VERSION 5.8 ;
BUSBITCHARS "[]" ;
DIVIDERCHAR "/" ;
UNITS
    DATABASE MICRONS 1000 ;
END UNITS

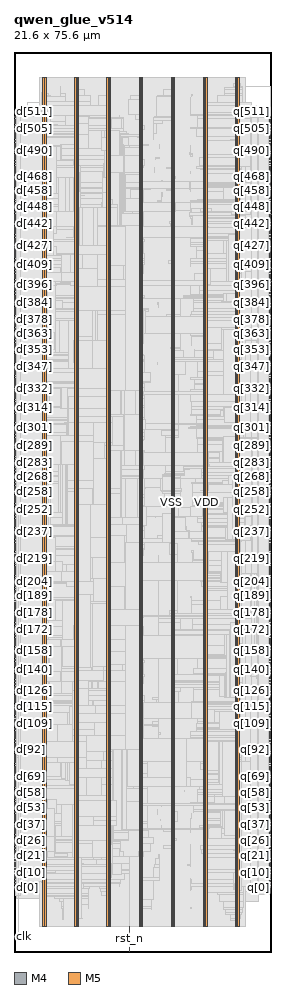
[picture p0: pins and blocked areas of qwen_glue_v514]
MACRO qwen_glue_v514
  FOREIGN qwen_glue_v514 0 0 ;
  CLASS BLOCK ;
  SIZE 21.6 BY 75.6 ;
  PIN clk
    DIRECTION INPUT ;
    USE SIGNAL ;
    PORT
      LAYER M4 ;
        RECT  0.054 1.296 0.138 1.32 ;
    END
    PORT
      LAYER M4 ;
        RECT  0.108 1.296 0.371 1.32 ;
    END
  END clk
  PIN d[0]
    DIRECTION INPUT ;
    USE SIGNAL ;
    PORT
      LAYER M4 ;
        RECT  0.054 5.424 0.138 5.448 ;
    END
  END d[0]
  PIN d[100]
    DIRECTION INPUT ;
    USE SIGNAL ;
    PORT
      LAYER M4 ;
        RECT  0.054 18 0.138 18.024 ;
    END
  END d[100]
  PIN d[101]
    DIRECTION INPUT ;
    USE SIGNAL ;
    PORT
      LAYER M4 ;
        RECT  0.054 18.144 0.138 18.168 ;
    END
  END d[101]
  PIN d[102]
    DIRECTION INPUT ;
    USE SIGNAL ;
    PORT
      LAYER M4 ;
        RECT  0.054 18.288 0.138 18.312 ;
    END
  END d[102]
  PIN d[103]
    DIRECTION INPUT ;
    USE SIGNAL ;
    PORT
      LAYER M4 ;
        RECT  0.054 18.384 0.138 18.408 ;
    END
  END d[103]
  PIN d[104]
    DIRECTION INPUT ;
    USE SIGNAL ;
    PORT
      LAYER M4 ;
        RECT  0.054 18.528 0.138 18.552 ;
    END
  END d[104]
  PIN d[105]
    DIRECTION INPUT ;
    USE SIGNAL ;
    PORT
      LAYER M4 ;
        RECT  0.054 18.672 0.138 18.696 ;
    END
  END d[105]
  PIN d[106]
    DIRECTION INPUT ;
    USE SIGNAL ;
    PORT
      LAYER M4 ;
        RECT  0.054 18.768 0.138 18.792 ;
    END
  END d[106]
  PIN d[107]
    DIRECTION INPUT ;
    USE SIGNAL ;
    PORT
      LAYER M4 ;
        RECT  0.054 18.912 0.138 18.936 ;
    END
  END d[107]
  PIN d[108]
    DIRECTION INPUT ;
    USE SIGNAL ;
    PORT
      LAYER M4 ;
        RECT  0.054 19.008 0.138 19.032 ;
    END
  END d[108]
  PIN d[109]
    DIRECTION INPUT ;
    USE SIGNAL ;
    PORT
      LAYER M4 ;
        RECT  0.054 19.152 0.138 19.176 ;
    END
  END d[109]
  PIN d[10]
    DIRECTION INPUT ;
    USE SIGNAL ;
    PORT
      LAYER M4 ;
        RECT  0.054 6.672 0.138 6.696 ;
    END
  END d[10]
  PIN d[110]
    DIRECTION INPUT ;
    USE SIGNAL ;
    PORT
      LAYER M4 ;
        RECT  0.054 19.296 0.138 19.32 ;
    END
  END d[110]
  PIN d[111]
    DIRECTION INPUT ;
    USE SIGNAL ;
    PORT
      LAYER M4 ;
        RECT  0.054 19.392 0.138 19.416 ;
    END
  END d[111]
  PIN d[112]
    DIRECTION INPUT ;
    USE SIGNAL ;
    PORT
      LAYER M4 ;
        RECT  0.054 19.536 0.138 19.56 ;
    END
    PORT
      LAYER M4 ;
        RECT  0.025 19.536 0.108 19.56 ;
    END
  END d[112]
  PIN d[113]
    DIRECTION INPUT ;
    USE SIGNAL ;
    PORT
      LAYER M4 ;
        RECT  0.054 19.68 0.138 19.704 ;
    END
  END d[113]
  PIN d[114]
    DIRECTION INPUT ;
    USE SIGNAL ;
    PORT
      LAYER M4 ;
        RECT  0.054 19.776 0.138 19.8 ;
    END
  END d[114]
  PIN d[115]
    DIRECTION INPUT ;
    USE SIGNAL ;
    PORT
      LAYER M4 ;
        RECT  0.054 19.92 0.138 19.944 ;
    END
  END d[115]
  PIN d[116]
    DIRECTION INPUT ;
    USE SIGNAL ;
    PORT
      LAYER M4 ;
        RECT  0.054 20.064 0.138 20.088 ;
    END
  END d[116]
  PIN d[117]
    DIRECTION INPUT ;
    USE SIGNAL ;
    PORT
      LAYER M4 ;
        RECT  0.054 20.16 0.138 20.184 ;
    END
  END d[117]
  PIN d[118]
    DIRECTION INPUT ;
    USE SIGNAL ;
    PORT
      LAYER M4 ;
        RECT  0.054 20.304 0.138 20.328 ;
    END
  END d[118]
  PIN d[119]
    DIRECTION INPUT ;
    USE SIGNAL ;
    PORT
      LAYER M4 ;
        RECT  0.054 20.4 0.138 20.424 ;
    END
  END d[119]
  PIN d[11]
    DIRECTION INPUT ;
    USE SIGNAL ;
    PORT
      LAYER M4 ;
        RECT  0.054 6.768 0.138 6.792 ;
    END
  END d[11]
  PIN d[120]
    DIRECTION INPUT ;
    USE SIGNAL ;
    PORT
      LAYER M4 ;
        RECT  0.054 20.544 0.138 20.568 ;
    END
  END d[120]
  PIN d[121]
    DIRECTION INPUT ;
    USE SIGNAL ;
    PORT
      LAYER M4 ;
        RECT  0.054 20.688 0.138 20.712 ;
    END
  END d[121]
  PIN d[122]
    DIRECTION INPUT ;
    USE SIGNAL ;
    PORT
      LAYER M4 ;
        RECT  0.054 20.784 0.138 20.808 ;
    END
  END d[122]
  PIN d[123]
    DIRECTION INPUT ;
    USE SIGNAL ;
    PORT
      LAYER M4 ;
        RECT  0.054 20.928 0.138 20.952 ;
    END
  END d[123]
  PIN d[124]
    DIRECTION INPUT ;
    USE SIGNAL ;
    PORT
      LAYER M4 ;
        RECT  0.054 21.072 0.138 21.096 ;
    END
  END d[124]
  PIN d[125]
    DIRECTION INPUT ;
    USE SIGNAL ;
    PORT
      LAYER M4 ;
        RECT  0.054 21.168 0.138 21.192 ;
    END
  END d[125]
  PIN d[126]
    DIRECTION INPUT ;
    USE SIGNAL ;
    PORT
      LAYER M4 ;
        RECT  0.054 21.312 0.138 21.336 ;
    END
  END d[126]
  PIN d[127]
    DIRECTION INPUT ;
    USE SIGNAL ;
    PORT
      LAYER M4 ;
        RECT  0.054 21.408 0.138 21.432 ;
    END
  END d[127]
  PIN d[128]
    DIRECTION INPUT ;
    USE SIGNAL ;
    PORT
      LAYER M4 ;
        RECT  0.054 21.552 0.138 21.576 ;
    END
  END d[128]
  PIN d[129]
    DIRECTION INPUT ;
    USE SIGNAL ;
    PORT
      LAYER M4 ;
        RECT  0.054 21.696 0.138 21.72 ;
    END
  END d[129]
  PIN d[12]
    DIRECTION INPUT ;
    USE SIGNAL ;
    PORT
      LAYER M4 ;
        RECT  0.054 6.912 0.138 6.936 ;
    END
  END d[12]
  PIN d[130]
    DIRECTION INPUT ;
    USE SIGNAL ;
    PORT
      LAYER M4 ;
        RECT  0.054 21.792 0.138 21.816 ;
    END
  END d[130]
  PIN d[131]
    DIRECTION INPUT ;
    USE SIGNAL ;
    PORT
      LAYER M4 ;
        RECT  0.054 21.936 0.138 21.96 ;
    END
  END d[131]
  PIN d[132]
    DIRECTION INPUT ;
    USE SIGNAL ;
    PORT
      LAYER M4 ;
        RECT  0.054 22.08 0.138 22.104 ;
    END
  END d[132]
  PIN d[133]
    DIRECTION INPUT ;
    USE SIGNAL ;
    PORT
      LAYER M4 ;
        RECT  0.054 22.176 0.138 22.2 ;
    END
  END d[133]
  PIN d[134]
    DIRECTION INPUT ;
    USE SIGNAL ;
    PORT
      LAYER M4 ;
        RECT  0.054 22.32 0.138 22.344 ;
    END
  END d[134]
  PIN d[135]
    DIRECTION INPUT ;
    USE SIGNAL ;
    PORT
      LAYER M4 ;
        RECT  0.054 22.464 0.138 22.488 ;
    END
  END d[135]
  PIN d[136]
    DIRECTION INPUT ;
    USE SIGNAL ;
    PORT
      LAYER M4 ;
        RECT  0.054 22.56 0.138 22.584 ;
    END
  END d[136]
  PIN d[137]
    DIRECTION INPUT ;
    USE SIGNAL ;
    PORT
      LAYER M4 ;
        RECT  0.054 22.704 0.138 22.728 ;
    END
  END d[137]
  PIN d[138]
    DIRECTION INPUT ;
    USE SIGNAL ;
    PORT
      LAYER M4 ;
        RECT  0.054 22.8 0.138 22.824 ;
    END
  END d[138]
  PIN d[139]
    DIRECTION INPUT ;
    USE SIGNAL ;
    PORT
      LAYER M4 ;
        RECT  0.054 22.944 0.138 22.968 ;
    END
  END d[139]
  PIN d[13]
    DIRECTION INPUT ;
    USE SIGNAL ;
    PORT
      LAYER M4 ;
        RECT  0.054 7.008 0.138 7.032 ;
    END
  END d[13]
  PIN d[140]
    DIRECTION INPUT ;
    USE SIGNAL ;
    PORT
      LAYER M4 ;
        RECT  0.054 23.088 0.138 23.112 ;
    END
  END d[140]
  PIN d[141]
    DIRECTION INPUT ;
    USE SIGNAL ;
    PORT
      LAYER M4 ;
        RECT  0.054 23.184 0.138 23.208 ;
    END
  END d[141]
  PIN d[142]
    DIRECTION INPUT ;
    USE SIGNAL ;
    PORT
      LAYER M4 ;
        RECT  0.054 23.328 0.138 23.352 ;
    END
  END d[142]
  PIN d[143]
    DIRECTION INPUT ;
    USE SIGNAL ;
    PORT
      LAYER M4 ;
        RECT  0.054 23.472 0.138 23.496 ;
    END
  END d[143]
  PIN d[144]
    DIRECTION INPUT ;
    USE SIGNAL ;
    PORT
      LAYER M4 ;
        RECT  0.054 23.568 0.138 23.592 ;
    END
  END d[144]
  PIN d[145]
    DIRECTION INPUT ;
    USE SIGNAL ;
    PORT
      LAYER M4 ;
        RECT  0.054 23.712 0.138 23.736 ;
    END
  END d[145]
  PIN d[146]
    DIRECTION INPUT ;
    USE SIGNAL ;
    PORT
      LAYER M4 ;
        RECT  0.054 23.808 0.138 23.832 ;
    END
  END d[146]
  PIN d[147]
    DIRECTION INPUT ;
    USE SIGNAL ;
    PORT
      LAYER M4 ;
        RECT  0.054 23.952 0.138 23.976 ;
    END
  END d[147]
  PIN d[148]
    DIRECTION INPUT ;
    USE SIGNAL ;
    PORT
      LAYER M4 ;
        RECT  0.054 24.096 0.138 24.12 ;
    END
  END d[148]
  PIN d[149]
    DIRECTION INPUT ;
    USE SIGNAL ;
    PORT
      LAYER M4 ;
        RECT  0.054 24.192 0.138 24.216 ;
    END
  END d[149]
  PIN d[14]
    DIRECTION INPUT ;
    USE SIGNAL ;
    PORT
      LAYER M4 ;
        RECT  0.054 7.152 0.138 7.176 ;
    END
  END d[14]
  PIN d[150]
    DIRECTION INPUT ;
    USE SIGNAL ;
    PORT
      LAYER M4 ;
        RECT  0.054 24.336 0.138 24.36 ;
    END
  END d[150]
  PIN d[151]
    DIRECTION INPUT ;
    USE SIGNAL ;
    PORT
      LAYER M4 ;
        RECT  0.054 24.48 0.138 24.504 ;
    END
  END d[151]
  PIN d[152]
    DIRECTION INPUT ;
    USE SIGNAL ;
    PORT
      LAYER M4 ;
        RECT  0.054 24.576 0.138 24.6 ;
    END
  END d[152]
  PIN d[153]
    DIRECTION INPUT ;
    USE SIGNAL ;
    PORT
      LAYER M4 ;
        RECT  0.054 24.72 0.138 24.744 ;
    END
  END d[153]
  PIN d[154]
    DIRECTION INPUT ;
    USE SIGNAL ;
    PORT
      LAYER M4 ;
        RECT  0.054 24.864 0.138 24.888 ;
    END
  END d[154]
  PIN d[155]
    DIRECTION INPUT ;
    USE SIGNAL ;
    PORT
      LAYER M4 ;
        RECT  0.054 24.96 0.138 24.984 ;
    END
    PORT
      LAYER M4 ;
        RECT  0.025 24.96 0.108 24.984 ;
    END
  END d[155]
  PIN d[156]
    DIRECTION INPUT ;
    USE SIGNAL ;
    PORT
      LAYER M4 ;
        RECT  0.054 25.104 0.138 25.128 ;
    END
  END d[156]
  PIN d[157]
    DIRECTION INPUT ;
    USE SIGNAL ;
    PORT
      LAYER M4 ;
        RECT  0.054 25.2 0.138 25.224 ;
    END
  END d[157]
  PIN d[158]
    DIRECTION INPUT ;
    USE SIGNAL ;
    PORT
      LAYER M4 ;
        RECT  0.054 25.344 0.138 25.368 ;
    END
  END d[158]
  PIN d[159]
    DIRECTION INPUT ;
    USE SIGNAL ;
    PORT
      LAYER M4 ;
        RECT  0.054 25.488 0.138 25.512 ;
    END
  END d[159]
  PIN d[15]
    DIRECTION INPUT ;
    USE SIGNAL ;
    PORT
      LAYER M4 ;
        RECT  0.054 7.296 0.138 7.32 ;
    END
  END d[15]
  PIN d[160]
    DIRECTION INPUT ;
    USE SIGNAL ;
    PORT
      LAYER M4 ;
        RECT  0.054 25.584 0.138 25.608 ;
    END
  END d[160]
  PIN d[161]
    DIRECTION INPUT ;
    USE SIGNAL ;
    PORT
      LAYER M4 ;
        RECT  0.054 25.728 0.138 25.752 ;
    END
  END d[161]
  PIN d[162]
    DIRECTION INPUT ;
    USE SIGNAL ;
    PORT
      LAYER M4 ;
        RECT  0.054 25.872 0.138 25.896 ;
    END
  END d[162]
  PIN d[163]
    DIRECTION INPUT ;
    USE SIGNAL ;
    PORT
      LAYER M4 ;
        RECT  0.054 25.968 0.138 25.992 ;
    END
  END d[163]
  PIN d[164]
    DIRECTION INPUT ;
    USE SIGNAL ;
    PORT
      LAYER M4 ;
        RECT  0.054 26.112 0.138 26.136 ;
    END
  END d[164]
  PIN d[165]
    DIRECTION INPUT ;
    USE SIGNAL ;
    PORT
      LAYER M4 ;
        RECT  0.054 26.208 0.138 26.232 ;
    END
  END d[165]
  PIN d[166]
    DIRECTION INPUT ;
    USE SIGNAL ;
    PORT
      LAYER M4 ;
        RECT  0.054 26.352 0.138 26.376 ;
    END
  END d[166]
  PIN d[167]
    DIRECTION INPUT ;
    USE SIGNAL ;
    PORT
      LAYER M4 ;
        RECT  0.054 26.496 0.138 26.52 ;
    END
  END d[167]
  PIN d[168]
    DIRECTION INPUT ;
    USE SIGNAL ;
    PORT
      LAYER M4 ;
        RECT  0.054 26.592 0.138 26.616 ;
    END
  END d[168]
  PIN d[169]
    DIRECTION INPUT ;
    USE SIGNAL ;
    PORT
      LAYER M4 ;
        RECT  0.054 26.736 0.138 26.76 ;
    END
  END d[169]
  PIN d[16]
    DIRECTION INPUT ;
    USE SIGNAL ;
    PORT
      LAYER M4 ;
        RECT  0.054 7.392 0.138 7.416 ;
    END
  END d[16]
  PIN d[170]
    DIRECTION INPUT ;
    USE SIGNAL ;
    PORT
      LAYER M4 ;
        RECT  0.054 26.88 0.138 26.904 ;
    END
  END d[170]
  PIN d[171]
    DIRECTION INPUT ;
    USE SIGNAL ;
    PORT
      LAYER M4 ;
        RECT  0.054 26.976 0.138 27 ;
    END
  END d[171]
  PIN d[172]
    DIRECTION INPUT ;
    USE SIGNAL ;
    PORT
      LAYER M4 ;
        RECT  0.054 27.12 0.138 27.144 ;
    END
  END d[172]
  PIN d[173]
    DIRECTION INPUT ;
    USE SIGNAL ;
    PORT
      LAYER M4 ;
        RECT  0.054 27.264 0.138 27.288 ;
    END
  END d[173]
  PIN d[174]
    DIRECTION INPUT ;
    USE SIGNAL ;
    PORT
      LAYER M4 ;
        RECT  0.054 27.36 0.138 27.384 ;
    END
  END d[174]
  PIN d[175]
    DIRECTION INPUT ;
    USE SIGNAL ;
    PORT
      LAYER M4 ;
        RECT  0.054 27.504 0.138 27.528 ;
    END
  END d[175]
  PIN d[176]
    DIRECTION INPUT ;
    USE SIGNAL ;
    PORT
      LAYER M4 ;
        RECT  0.054 27.6 0.138 27.624 ;
    END
  END d[176]
  PIN d[177]
    DIRECTION INPUT ;
    USE SIGNAL ;
    PORT
      LAYER M4 ;
        RECT  0.054 27.744 0.138 27.768 ;
    END
  END d[177]
  PIN d[178]
    DIRECTION INPUT ;
    USE SIGNAL ;
    PORT
      LAYER M4 ;
        RECT  0.054 27.888 0.138 27.912 ;
    END
  END d[178]
  PIN d[179]
    DIRECTION INPUT ;
    USE SIGNAL ;
    PORT
      LAYER M4 ;
        RECT  0.054 27.984 0.138 28.008 ;
    END
  END d[179]
  PIN d[17]
    DIRECTION INPUT ;
    USE SIGNAL ;
    PORT
      LAYER M4 ;
        RECT  0.054 7.536 0.138 7.56 ;
    END
  END d[17]
  PIN d[180]
    DIRECTION INPUT ;
    USE SIGNAL ;
    PORT
      LAYER M4 ;
        RECT  0.054 28.128 0.138 28.152 ;
    END
  END d[180]
  PIN d[181]
    DIRECTION INPUT ;
    USE SIGNAL ;
    PORT
      LAYER M4 ;
        RECT  0.054 28.272 0.138 28.296 ;
    END
  END d[181]
  PIN d[182]
    DIRECTION INPUT ;
    USE SIGNAL ;
    PORT
      LAYER M4 ;
        RECT  0.054 28.368 0.138 28.392 ;
    END
  END d[182]
  PIN d[183]
    DIRECTION INPUT ;
    USE SIGNAL ;
    PORT
      LAYER M4 ;
        RECT  0.054 28.512 0.138 28.536 ;
    END
  END d[183]
  PIN d[184]
    DIRECTION INPUT ;
    USE SIGNAL ;
    PORT
      LAYER M4 ;
        RECT  0.054 28.608 0.138 28.632 ;
    END
  END d[184]
  PIN d[185]
    DIRECTION INPUT ;
    USE SIGNAL ;
    PORT
      LAYER M4 ;
        RECT  0.054 28.752 0.138 28.776 ;
    END
  END d[185]
  PIN d[186]
    DIRECTION INPUT ;
    USE SIGNAL ;
    PORT
      LAYER M4 ;
        RECT  0.054 28.896 0.138 28.92 ;
    END
  END d[186]
  PIN d[187]
    DIRECTION INPUT ;
    USE SIGNAL ;
    PORT
      LAYER M4 ;
        RECT  0.054 28.992 0.138 29.016 ;
    END
  END d[187]
  PIN d[188]
    DIRECTION INPUT ;
    USE SIGNAL ;
    PORT
      LAYER M4 ;
        RECT  0.054 29.136 0.138 29.16 ;
    END
  END d[188]
  PIN d[189]
    DIRECTION INPUT ;
    USE SIGNAL ;
    PORT
      LAYER M4 ;
        RECT  0.054 29.28 0.138 29.304 ;
    END
  END d[189]
  PIN d[18]
    DIRECTION INPUT ;
    USE SIGNAL ;
    PORT
      LAYER M4 ;
        RECT  0.054 7.68 0.138 7.704 ;
    END
  END d[18]
  PIN d[190]
    DIRECTION INPUT ;
    USE SIGNAL ;
    PORT
      LAYER M4 ;
        RECT  0.054 29.376 0.138 29.4 ;
    END
  END d[190]
  PIN d[191]
    DIRECTION INPUT ;
    USE SIGNAL ;
    PORT
      LAYER M4 ;
        RECT  0.054 29.52 0.138 29.544 ;
    END
  END d[191]
  PIN d[192]
    DIRECTION INPUT ;
    USE SIGNAL ;
    PORT
      LAYER M4 ;
        RECT  0.054 29.664 0.138 29.688 ;
    END
  END d[192]
  PIN d[193]
    DIRECTION INPUT ;
    USE SIGNAL ;
    PORT
      LAYER M4 ;
        RECT  0.054 29.76 0.138 29.784 ;
    END
  END d[193]
  PIN d[194]
    DIRECTION INPUT ;
    USE SIGNAL ;
    PORT
      LAYER M4 ;
        RECT  0.054 29.904 0.138 29.928 ;
    END
  END d[194]
  PIN d[195]
    DIRECTION INPUT ;
    USE SIGNAL ;
    PORT
      LAYER M4 ;
        RECT  0.054 30 0.138 30.024 ;
    END
  END d[195]
  PIN d[196]
    DIRECTION INPUT ;
    USE SIGNAL ;
    PORT
      LAYER M4 ;
        RECT  0.054 30.144 0.138 30.168 ;
    END
  END d[196]
  PIN d[197]
    DIRECTION INPUT ;
    USE SIGNAL ;
    PORT
      LAYER M4 ;
        RECT  0.054 30.288 0.138 30.312 ;
    END
  END d[197]
  PIN d[198]
    DIRECTION INPUT ;
    USE SIGNAL ;
    PORT
      LAYER M4 ;
        RECT  0.054 30.384 0.138 30.408 ;
    END
  END d[198]
  PIN d[199]
    DIRECTION INPUT ;
    USE SIGNAL ;
    PORT
      LAYER M4 ;
        RECT  0.054 30.528 0.138 30.552 ;
    END
  END d[199]
  PIN d[19]
    DIRECTION INPUT ;
    USE SIGNAL ;
    PORT
      LAYER M4 ;
        RECT  0.054 7.776 0.138 7.8 ;
    END
  END d[19]
  PIN d[1]
    DIRECTION INPUT ;
    USE SIGNAL ;
    PORT
      LAYER M4 ;
        RECT  0.054 5.52 0.138 5.544 ;
    END
  END d[1]
  PIN d[200]
    DIRECTION INPUT ;
    USE SIGNAL ;
    PORT
      LAYER M4 ;
        RECT  0.054 30.672 0.138 30.696 ;
    END
  END d[200]
  PIN d[201]
    DIRECTION INPUT ;
    USE SIGNAL ;
    PORT
      LAYER M4 ;
        RECT  0.054 30.768 0.138 30.792 ;
    END
  END d[201]
  PIN d[202]
    DIRECTION INPUT ;
    USE SIGNAL ;
    PORT
      LAYER M4 ;
        RECT  0.054 30.912 0.138 30.936 ;
    END
  END d[202]
  PIN d[203]
    DIRECTION INPUT ;
    USE SIGNAL ;
    PORT
      LAYER M4 ;
        RECT  0.054 31.008 0.138 31.032 ;
    END
  END d[203]
  PIN d[204]
    DIRECTION INPUT ;
    USE SIGNAL ;
    PORT
      LAYER M4 ;
        RECT  0.054 31.152 0.138 31.176 ;
    END
  END d[204]
  PIN d[205]
    DIRECTION INPUT ;
    USE SIGNAL ;
    PORT
      LAYER M4 ;
        RECT  0.054 31.296 0.138 31.32 ;
    END
  END d[205]
  PIN d[206]
    DIRECTION INPUT ;
    USE SIGNAL ;
    PORT
      LAYER M4 ;
        RECT  0.054 31.392 0.138 31.416 ;
    END
  END d[206]
  PIN d[207]
    DIRECTION INPUT ;
    USE SIGNAL ;
    PORT
      LAYER M4 ;
        RECT  0.054 31.536 0.138 31.56 ;
    END
  END d[207]
  PIN d[208]
    DIRECTION INPUT ;
    USE SIGNAL ;
    PORT
      LAYER M4 ;
        RECT  0.054 31.68 0.138 31.704 ;
    END
  END d[208]
  PIN d[209]
    DIRECTION INPUT ;
    USE SIGNAL ;
    PORT
      LAYER M4 ;
        RECT  0.054 31.776 0.138 31.8 ;
    END
  END d[209]
  PIN d[20]
    DIRECTION INPUT ;
    USE SIGNAL ;
    PORT
      LAYER M4 ;
        RECT  0.054 7.92 0.138 7.944 ;
    END
    PORT
      LAYER M4 ;
        RECT  0.025 7.92 0.108 7.944 ;
    END
  END d[20]
  PIN d[210]
    DIRECTION INPUT ;
    USE SIGNAL ;
    PORT
      LAYER M4 ;
        RECT  0.054 31.92 0.138 31.944 ;
    END
  END d[210]
  PIN d[211]
    DIRECTION INPUT ;
    USE SIGNAL ;
    PORT
      LAYER M4 ;
        RECT  0.054 32.064 0.138 32.088 ;
    END
  END d[211]
  PIN d[212]
    DIRECTION INPUT ;
    USE SIGNAL ;
    PORT
      LAYER M4 ;
        RECT  0.054 32.16 0.138 32.184 ;
    END
  END d[212]
  PIN d[213]
    DIRECTION INPUT ;
    USE SIGNAL ;
    PORT
      LAYER M4 ;
        RECT  0.054 32.304 0.138 32.328 ;
    END
  END d[213]
  PIN d[214]
    DIRECTION INPUT ;
    USE SIGNAL ;
    PORT
      LAYER M4 ;
        RECT  0.054 32.4 0.138 32.424 ;
    END
  END d[214]
  PIN d[215]
    DIRECTION INPUT ;
    USE SIGNAL ;
    PORT
      LAYER M4 ;
        RECT  0.054 32.544 0.138 32.568 ;
    END
  END d[215]
  PIN d[216]
    DIRECTION INPUT ;
    USE SIGNAL ;
    PORT
      LAYER M4 ;
        RECT  0.054 32.688 0.138 32.712 ;
    END
  END d[216]
  PIN d[217]
    DIRECTION INPUT ;
    USE SIGNAL ;
    PORT
      LAYER M4 ;
        RECT  0.054 32.784 0.138 32.808 ;
    END
  END d[217]
  PIN d[218]
    DIRECTION INPUT ;
    USE SIGNAL ;
    PORT
      LAYER M4 ;
        RECT  0.054 32.928 0.138 32.952 ;
    END
  END d[218]
  PIN d[219]
    DIRECTION INPUT ;
    USE SIGNAL ;
    PORT
      LAYER M4 ;
        RECT  0.054 33.072 0.138 33.096 ;
    END
  END d[219]
  PIN d[21]
    DIRECTION INPUT ;
    USE SIGNAL ;
    PORT
      LAYER M4 ;
        RECT  0.054 8.064 0.138 8.088 ;
    END
  END d[21]
  PIN d[220]
    DIRECTION INPUT ;
    USE SIGNAL ;
    PORT
      LAYER M4 ;
        RECT  0.054 33.168 0.138 33.192 ;
    END
  END d[220]
  PIN d[221]
    DIRECTION INPUT ;
    USE SIGNAL ;
    PORT
      LAYER M4 ;
        RECT  0.054 33.312 0.138 33.336 ;
    END
  END d[221]
  PIN d[222]
    DIRECTION INPUT ;
    USE SIGNAL ;
    PORT
      LAYER M4 ;
        RECT  0.054 33.408 0.138 33.432 ;
    END
  END d[222]
  PIN d[223]
    DIRECTION INPUT ;
    USE SIGNAL ;
    PORT
      LAYER M4 ;
        RECT  0.054 33.552 0.138 33.576 ;
    END
  END d[223]
  PIN d[224]
    DIRECTION INPUT ;
    USE SIGNAL ;
    PORT
      LAYER M4 ;
        RECT  0.054 33.696 0.138 33.72 ;
    END
  END d[224]
  PIN d[225]
    DIRECTION INPUT ;
    USE SIGNAL ;
    PORT
      LAYER M4 ;
        RECT  0.054 33.792 0.138 33.816 ;
    END
  END d[225]
  PIN d[226]
    DIRECTION INPUT ;
    USE SIGNAL ;
    PORT
      LAYER M4 ;
        RECT  0.054 33.936 0.138 33.96 ;
    END
  END d[226]
  PIN d[227]
    DIRECTION INPUT ;
    USE SIGNAL ;
    PORT
      LAYER M4 ;
        RECT  0.054 34.08 0.138 34.104 ;
    END
  END d[227]
  PIN d[228]
    DIRECTION INPUT ;
    USE SIGNAL ;
    PORT
      LAYER M4 ;
        RECT  0.054 34.176 0.138 34.2 ;
    END
  END d[228]
  PIN d[229]
    DIRECTION INPUT ;
    USE SIGNAL ;
    PORT
      LAYER M4 ;
        RECT  0.054 34.32 0.138 34.344 ;
    END
  END d[229]
  PIN d[22]
    DIRECTION INPUT ;
    USE SIGNAL ;
    PORT
      LAYER M4 ;
        RECT  0.054 8.16 0.138 8.184 ;
    END
  END d[22]
  PIN d[230]
    DIRECTION INPUT ;
    USE SIGNAL ;
    PORT
      LAYER M4 ;
        RECT  0.054 34.464 0.138 34.488 ;
    END
  END d[230]
  PIN d[231]
    DIRECTION INPUT ;
    USE SIGNAL ;
    PORT
      LAYER M4 ;
        RECT  0.054 34.56 0.138 34.584 ;
    END
  END d[231]
  PIN d[232]
    DIRECTION INPUT ;
    USE SIGNAL ;
    PORT
      LAYER M4 ;
        RECT  0.054 34.704 0.138 34.728 ;
    END
  END d[232]
  PIN d[233]
    DIRECTION INPUT ;
    USE SIGNAL ;
    PORT
      LAYER M4 ;
        RECT  0.054 34.8 0.138 34.824 ;
    END
  END d[233]
  PIN d[234]
    DIRECTION INPUT ;
    USE SIGNAL ;
    PORT
      LAYER M4 ;
        RECT  0.054 34.944 0.138 34.968 ;
    END
  END d[234]
  PIN d[235]
    DIRECTION INPUT ;
    USE SIGNAL ;
    PORT
      LAYER M4 ;
        RECT  0.054 35.088 0.138 35.112 ;
    END
  END d[235]
  PIN d[236]
    DIRECTION INPUT ;
    USE SIGNAL ;
    PORT
      LAYER M4 ;
        RECT  0.054 35.184 0.138 35.208 ;
    END
  END d[236]
  PIN d[237]
    DIRECTION INPUT ;
    USE SIGNAL ;
    PORT
      LAYER M4 ;
        RECT  0.054 35.328 0.138 35.352 ;
    END
  END d[237]
  PIN d[238]
    DIRECTION INPUT ;
    USE SIGNAL ;
    PORT
      LAYER M4 ;
        RECT  0.054 35.472 0.138 35.496 ;
    END
  END d[238]
  PIN d[239]
    DIRECTION INPUT ;
    USE SIGNAL ;
    PORT
      LAYER M4 ;
        RECT  0.054 35.568 0.138 35.592 ;
    END
  END d[239]
  PIN d[23]
    DIRECTION INPUT ;
    USE SIGNAL ;
    PORT
      LAYER M4 ;
        RECT  0.054 8.304 0.138 8.328 ;
    END
  END d[23]
  PIN d[240]
    DIRECTION INPUT ;
    USE SIGNAL ;
    PORT
      LAYER M4 ;
        RECT  0.054 35.712 0.138 35.736 ;
    END
  END d[240]
  PIN d[241]
    DIRECTION INPUT ;
    USE SIGNAL ;
    PORT
      LAYER M4 ;
        RECT  0.054 35.808 0.138 35.832 ;
    END
  END d[241]
  PIN d[242]
    DIRECTION INPUT ;
    USE SIGNAL ;
    PORT
      LAYER M4 ;
        RECT  0.054 35.952 0.138 35.976 ;
    END
  END d[242]
  PIN d[243]
    DIRECTION INPUT ;
    USE SIGNAL ;
    PORT
      LAYER M4 ;
        RECT  0.054 36.096 0.138 36.12 ;
    END
  END d[243]
  PIN d[244]
    DIRECTION INPUT ;
    USE SIGNAL ;
    PORT
      LAYER M4 ;
        RECT  0.054 36.192 0.138 36.216 ;
    END
  END d[244]
  PIN d[245]
    DIRECTION INPUT ;
    USE SIGNAL ;
    PORT
      LAYER M4 ;
        RECT  0.054 36.336 0.138 36.36 ;
    END
  END d[245]
  PIN d[246]
    DIRECTION INPUT ;
    USE SIGNAL ;
    PORT
      LAYER M4 ;
        RECT  0.054 36.48 0.138 36.504 ;
    END
  END d[246]
  PIN d[247]
    DIRECTION INPUT ;
    USE SIGNAL ;
    PORT
      LAYER M4 ;
        RECT  0.054 36.576 0.138 36.6 ;
    END
  END d[247]
  PIN d[248]
    DIRECTION INPUT ;
    USE SIGNAL ;
    PORT
      LAYER M4 ;
        RECT  0.054 36.72 0.138 36.744 ;
    END
  END d[248]
  PIN d[249]
    DIRECTION INPUT ;
    USE SIGNAL ;
    PORT
      LAYER M4 ;
        RECT  0.054 36.864 0.138 36.888 ;
    END
  END d[249]
  PIN d[24]
    DIRECTION INPUT ;
    USE SIGNAL ;
    PORT
      LAYER M4 ;
        RECT  0.054 8.4 0.138 8.424 ;
    END
  END d[24]
  PIN d[250]
    DIRECTION INPUT ;
    USE SIGNAL ;
    PORT
      LAYER M4 ;
        RECT  0.054 36.96 0.138 36.984 ;
    END
  END d[250]
  PIN d[251]
    DIRECTION INPUT ;
    USE SIGNAL ;
    PORT
      LAYER M4 ;
        RECT  0.054 37.104 0.138 37.128 ;
    END
  END d[251]
  PIN d[252]
    DIRECTION INPUT ;
    USE SIGNAL ;
    PORT
      LAYER M4 ;
        RECT  0.054 37.2 0.138 37.224 ;
    END
  END d[252]
  PIN d[253]
    DIRECTION INPUT ;
    USE SIGNAL ;
    PORT
      LAYER M4 ;
        RECT  0.054 37.344 0.138 37.368 ;
    END
    PORT
      LAYER M4 ;
        RECT  0.025 37.344 0.108 37.368 ;
    END
  END d[253]
  PIN d[254]
    DIRECTION INPUT ;
    USE SIGNAL ;
    PORT
      LAYER M4 ;
        RECT  0.054 37.488 0.138 37.512 ;
    END
  END d[254]
  PIN d[255]
    DIRECTION INPUT ;
    USE SIGNAL ;
    PORT
      LAYER M4 ;
        RECT  0.054 37.584 0.138 37.608 ;
    END
  END d[255]
  PIN d[256]
    DIRECTION INPUT ;
    USE SIGNAL ;
    PORT
      LAYER M4 ;
        RECT  0.054 37.728 0.138 37.752 ;
    END
  END d[256]
  PIN d[257]
    DIRECTION INPUT ;
    USE SIGNAL ;
    PORT
      LAYER M4 ;
        RECT  0.054 37.872 0.138 37.896 ;
    END
  END d[257]
  PIN d[258]
    DIRECTION INPUT ;
    USE SIGNAL ;
    PORT
      LAYER M4 ;
        RECT  0.054 37.968 0.138 37.992 ;
    END
  END d[258]
  PIN d[259]
    DIRECTION INPUT ;
    USE SIGNAL ;
    PORT
      LAYER M4 ;
        RECT  0.054 38.112 0.138 38.136 ;
    END
  END d[259]
  PIN d[25]
    DIRECTION INPUT ;
    USE SIGNAL ;
    PORT
      LAYER M4 ;
        RECT  0.054 8.544 0.138 8.568 ;
    END
  END d[25]
  PIN d[260]
    DIRECTION INPUT ;
    USE SIGNAL ;
    PORT
      LAYER M4 ;
        RECT  0.054 38.208 0.138 38.232 ;
    END
  END d[260]
  PIN d[261]
    DIRECTION INPUT ;
    USE SIGNAL ;
    PORT
      LAYER M4 ;
        RECT  0.054 38.352 0.138 38.376 ;
    END
  END d[261]
  PIN d[262]
    DIRECTION INPUT ;
    USE SIGNAL ;
    PORT
      LAYER M4 ;
        RECT  0.054 38.496 0.138 38.52 ;
    END
  END d[262]
  PIN d[263]
    DIRECTION INPUT ;
    USE SIGNAL ;
    PORT
      LAYER M4 ;
        RECT  0.054 38.592 0.138 38.616 ;
    END
  END d[263]
  PIN d[264]
    DIRECTION INPUT ;
    USE SIGNAL ;
    PORT
      LAYER M4 ;
        RECT  0.054 38.736 0.138 38.76 ;
    END
  END d[264]
  PIN d[265]
    DIRECTION INPUT ;
    USE SIGNAL ;
    PORT
      LAYER M4 ;
        RECT  0.054 38.88 0.138 38.904 ;
    END
  END d[265]
  PIN d[266]
    DIRECTION INPUT ;
    USE SIGNAL ;
    PORT
      LAYER M4 ;
        RECT  0.054 38.976 0.138 39 ;
    END
    PORT
      LAYER M4 ;
        RECT  0.025 38.976 0.108 39 ;
    END
  END d[266]
  PIN d[267]
    DIRECTION INPUT ;
    USE SIGNAL ;
    PORT
      LAYER M4 ;
        RECT  0.054 39.12 0.138 39.144 ;
    END
  END d[267]
  PIN d[268]
    DIRECTION INPUT ;
    USE SIGNAL ;
    PORT
      LAYER M4 ;
        RECT  0.054 39.264 0.138 39.288 ;
    END
  END d[268]
  PIN d[269]
    DIRECTION INPUT ;
    USE SIGNAL ;
    PORT
      LAYER M4 ;
        RECT  0.054 39.36 0.138 39.384 ;
    END
  END d[269]
  PIN d[26]
    DIRECTION INPUT ;
    USE SIGNAL ;
    PORT
      LAYER M4 ;
        RECT  0.054 8.688 0.138 8.712 ;
    END
  END d[26]
  PIN d[270]
    DIRECTION INPUT ;
    USE SIGNAL ;
    PORT
      LAYER M4 ;
        RECT  0.054 39.504 0.138 39.528 ;
    END
  END d[270]
  PIN d[271]
    DIRECTION INPUT ;
    USE SIGNAL ;
    PORT
      LAYER M4 ;
        RECT  0.054 39.6 0.138 39.624 ;
    END
  END d[271]
  PIN d[272]
    DIRECTION INPUT ;
    USE SIGNAL ;
    PORT
      LAYER M4 ;
        RECT  0.054 39.744 0.138 39.768 ;
    END
  END d[272]
  PIN d[273]
    DIRECTION INPUT ;
    USE SIGNAL ;
    PORT
      LAYER M4 ;
        RECT  0.054 39.888 0.138 39.912 ;
    END
  END d[273]
  PIN d[274]
    DIRECTION INPUT ;
    USE SIGNAL ;
    PORT
      LAYER M4 ;
        RECT  0.054 39.984 0.138 40.008 ;
    END
  END d[274]
  PIN d[275]
    DIRECTION INPUT ;
    USE SIGNAL ;
    PORT
      LAYER M4 ;
        RECT  0.054 40.128 0.138 40.152 ;
    END
  END d[275]
  PIN d[276]
    DIRECTION INPUT ;
    USE SIGNAL ;
    PORT
      LAYER M4 ;
        RECT  0.054 40.272 0.138 40.296 ;
    END
  END d[276]
  PIN d[277]
    DIRECTION INPUT ;
    USE SIGNAL ;
    PORT
      LAYER M4 ;
        RECT  0.054 40.368 0.138 40.392 ;
    END
  END d[277]
  PIN d[278]
    DIRECTION INPUT ;
    USE SIGNAL ;
    PORT
      LAYER M4 ;
        RECT  0.054 40.512 0.138 40.536 ;
    END
  END d[278]
  PIN d[279]
    DIRECTION INPUT ;
    USE SIGNAL ;
    PORT
      LAYER M4 ;
        RECT  0.054 40.608 0.138 40.632 ;
    END
  END d[279]
  PIN d[27]
    DIRECTION INPUT ;
    USE SIGNAL ;
    PORT
      LAYER M4 ;
        RECT  0.054 8.784 0.138 8.808 ;
    END
  END d[27]
  PIN d[280]
    DIRECTION INPUT ;
    USE SIGNAL ;
    PORT
      LAYER M4 ;
        RECT  0.054 40.752 0.138 40.776 ;
    END
  END d[280]
  PIN d[281]
    DIRECTION INPUT ;
    USE SIGNAL ;
    PORT
      LAYER M4 ;
        RECT  0.054 40.896 0.138 40.92 ;
    END
  END d[281]
  PIN d[282]
    DIRECTION INPUT ;
    USE SIGNAL ;
    PORT
      LAYER M4 ;
        RECT  0.054 40.992 0.138 41.016 ;
    END
  END d[282]
  PIN d[283]
    DIRECTION INPUT ;
    USE SIGNAL ;
    PORT
      LAYER M4 ;
        RECT  0.054 41.136 0.138 41.16 ;
    END
  END d[283]
  PIN d[284]
    DIRECTION INPUT ;
    USE SIGNAL ;
    PORT
      LAYER M4 ;
        RECT  0.054 41.28 0.138 41.304 ;
    END
  END d[284]
  PIN d[285]
    DIRECTION INPUT ;
    USE SIGNAL ;
    PORT
      LAYER M4 ;
        RECT  0.054 41.376 0.138 41.4 ;
    END
  END d[285]
  PIN d[286]
    DIRECTION INPUT ;
    USE SIGNAL ;
    PORT
      LAYER M4 ;
        RECT  0.054 41.52 0.138 41.544 ;
    END
  END d[286]
  PIN d[287]
    DIRECTION INPUT ;
    USE SIGNAL ;
    PORT
      LAYER M4 ;
        RECT  0.054 41.664 0.138 41.688 ;
    END
  END d[287]
  PIN d[288]
    DIRECTION INPUT ;
    USE SIGNAL ;
    PORT
      LAYER M4 ;
        RECT  0.054 41.76 0.138 41.784 ;
    END
  END d[288]
  PIN d[289]
    DIRECTION INPUT ;
    USE SIGNAL ;
    PORT
      LAYER M4 ;
        RECT  0.054 41.904 0.138 41.928 ;
    END
  END d[289]
  PIN d[28]
    DIRECTION INPUT ;
    USE SIGNAL ;
    PORT
      LAYER M4 ;
        RECT  0.054 8.928 0.138 8.952 ;
    END
  END d[28]
  PIN d[290]
    DIRECTION INPUT ;
    USE SIGNAL ;
    PORT
      LAYER M4 ;
        RECT  0.054 42 0.138 42.024 ;
    END
  END d[290]
  PIN d[291]
    DIRECTION INPUT ;
    USE SIGNAL ;
    PORT
      LAYER M4 ;
        RECT  0.054 42.144 0.138 42.168 ;
    END
  END d[291]
  PIN d[292]
    DIRECTION INPUT ;
    USE SIGNAL ;
    PORT
      LAYER M4 ;
        RECT  0.054 42.288 0.138 42.312 ;
    END
  END d[292]
  PIN d[293]
    DIRECTION INPUT ;
    USE SIGNAL ;
    PORT
      LAYER M4 ;
        RECT  0.054 42.384 0.138 42.408 ;
    END
  END d[293]
  PIN d[294]
    DIRECTION INPUT ;
    USE SIGNAL ;
    PORT
      LAYER M4 ;
        RECT  0.054 42.528 0.138 42.552 ;
    END
  END d[294]
  PIN d[295]
    DIRECTION INPUT ;
    USE SIGNAL ;
    PORT
      LAYER M4 ;
        RECT  0.054 42.672 0.138 42.696 ;
    END
  END d[295]
  PIN d[296]
    DIRECTION INPUT ;
    USE SIGNAL ;
    PORT
      LAYER M4 ;
        RECT  0.054 42.768 0.138 42.792 ;
    END
  END d[296]
  PIN d[297]
    DIRECTION INPUT ;
    USE SIGNAL ;
    PORT
      LAYER M4 ;
        RECT  0.054 42.912 0.138 42.936 ;
    END
  END d[297]
  PIN d[298]
    DIRECTION INPUT ;
    USE SIGNAL ;
    PORT
      LAYER M4 ;
        RECT  0.054 43.008 0.138 43.032 ;
    END
  END d[298]
  PIN d[299]
    DIRECTION INPUT ;
    USE SIGNAL ;
    PORT
      LAYER M4 ;
        RECT  0.054 43.152 0.138 43.176 ;
    END
  END d[299]
  PIN d[29]
    DIRECTION INPUT ;
    USE SIGNAL ;
    PORT
      LAYER M4 ;
        RECT  0.054 9.072 0.138 9.096 ;
    END
  END d[29]
  PIN d[2]
    DIRECTION INPUT ;
    USE SIGNAL ;
    PORT
      LAYER M4 ;
        RECT  0.054 5.664 0.138 5.688 ;
    END
  END d[2]
  PIN d[300]
    DIRECTION INPUT ;
    USE SIGNAL ;
    PORT
      LAYER M4 ;
        RECT  0.054 43.296 0.138 43.32 ;
    END
    PORT
      LAYER M4 ;
        RECT  0.025 43.296 0.108 43.32 ;
    END
  END d[300]
  PIN d[301]
    DIRECTION INPUT ;
    USE SIGNAL ;
    PORT
      LAYER M4 ;
        RECT  0.054 43.392 0.138 43.416 ;
    END
  END d[301]
  PIN d[302]
    DIRECTION INPUT ;
    USE SIGNAL ;
    PORT
      LAYER M4 ;
        RECT  0.054 43.536 0.138 43.56 ;
    END
  END d[302]
  PIN d[303]
    DIRECTION INPUT ;
    USE SIGNAL ;
    PORT
      LAYER M4 ;
        RECT  0.054 43.68 0.138 43.704 ;
    END
  END d[303]
  PIN d[304]
    DIRECTION INPUT ;
    USE SIGNAL ;
    PORT
      LAYER M4 ;
        RECT  0.054 43.776 0.138 43.8 ;
    END
  END d[304]
  PIN d[305]
    DIRECTION INPUT ;
    USE SIGNAL ;
    PORT
      LAYER M4 ;
        RECT  0.054 43.92 0.138 43.944 ;
    END
  END d[305]
  PIN d[306]
    DIRECTION INPUT ;
    USE SIGNAL ;
    PORT
      LAYER M4 ;
        RECT  0.054 44.064 0.138 44.088 ;
    END
  END d[306]
  PIN d[307]
    DIRECTION INPUT ;
    USE SIGNAL ;
    PORT
      LAYER M4 ;
        RECT  0.054 44.16 0.138 44.184 ;
    END
  END d[307]
  PIN d[308]
    DIRECTION INPUT ;
    USE SIGNAL ;
    PORT
      LAYER M4 ;
        RECT  0.054 44.304 0.138 44.328 ;
    END
  END d[308]
  PIN d[309]
    DIRECTION INPUT ;
    USE SIGNAL ;
    PORT
      LAYER M4 ;
        RECT  0.054 44.4 0.138 44.424 ;
    END
  END d[309]
  PIN d[30]
    DIRECTION INPUT ;
    USE SIGNAL ;
    PORT
      LAYER M4 ;
        RECT  0.054 9.168 0.138 9.192 ;
    END
  END d[30]
  PIN d[310]
    DIRECTION INPUT ;
    USE SIGNAL ;
    PORT
      LAYER M4 ;
        RECT  0.054 44.544 0.138 44.568 ;
    END
  END d[310]
  PIN d[311]
    DIRECTION INPUT ;
    USE SIGNAL ;
    PORT
      LAYER M4 ;
        RECT  0.054 44.688 0.138 44.712 ;
    END
  END d[311]
  PIN d[312]
    DIRECTION INPUT ;
    USE SIGNAL ;
    PORT
      LAYER M4 ;
        RECT  0.054 44.784 0.138 44.808 ;
    END
  END d[312]
  PIN d[313]
    DIRECTION INPUT ;
    USE SIGNAL ;
    PORT
      LAYER M4 ;
        RECT  0.054 44.928 0.138 44.952 ;
    END
  END d[313]
  PIN d[314]
    DIRECTION INPUT ;
    USE SIGNAL ;
    PORT
      LAYER M4 ;
        RECT  0.054 45.072 0.138 45.096 ;
    END
  END d[314]
  PIN d[315]
    DIRECTION INPUT ;
    USE SIGNAL ;
    PORT
      LAYER M4 ;
        RECT  0.054 45.168 0.138 45.192 ;
    END
  END d[315]
  PIN d[316]
    DIRECTION INPUT ;
    USE SIGNAL ;
    PORT
      LAYER M4 ;
        RECT  0.054 45.312 0.138 45.336 ;
    END
  END d[316]
  PIN d[317]
    DIRECTION INPUT ;
    USE SIGNAL ;
    PORT
      LAYER M4 ;
        RECT  0.054 45.408 0.138 45.432 ;
    END
  END d[317]
  PIN d[318]
    DIRECTION INPUT ;
    USE SIGNAL ;
    PORT
      LAYER M4 ;
        RECT  0.054 45.552 0.138 45.576 ;
    END
  END d[318]
  PIN d[319]
    DIRECTION INPUT ;
    USE SIGNAL ;
    PORT
      LAYER M4 ;
        RECT  0.054 45.696 0.138 45.72 ;
    END
  END d[319]
  PIN d[31]
    DIRECTION INPUT ;
    USE SIGNAL ;
    PORT
      LAYER M4 ;
        RECT  0.054 9.312 0.138 9.336 ;
    END
  END d[31]
  PIN d[320]
    DIRECTION INPUT ;
    USE SIGNAL ;
    PORT
      LAYER M4 ;
        RECT  0.054 45.792 0.138 45.816 ;
    END
  END d[320]
  PIN d[321]
    DIRECTION INPUT ;
    USE SIGNAL ;
    PORT
      LAYER M4 ;
        RECT  0.054 45.936 0.138 45.96 ;
    END
  END d[321]
  PIN d[322]
    DIRECTION INPUT ;
    USE SIGNAL ;
    PORT
      LAYER M4 ;
        RECT  0.054 46.08 0.138 46.104 ;
    END
  END d[322]
  PIN d[323]
    DIRECTION INPUT ;
    USE SIGNAL ;
    PORT
      LAYER M4 ;
        RECT  0.054 46.176 0.138 46.2 ;
    END
  END d[323]
  PIN d[324]
    DIRECTION INPUT ;
    USE SIGNAL ;
    PORT
      LAYER M4 ;
        RECT  0.054 46.32 0.138 46.344 ;
    END
  END d[324]
  PIN d[325]
    DIRECTION INPUT ;
    USE SIGNAL ;
    PORT
      LAYER M4 ;
        RECT  0.054 46.464 0.138 46.488 ;
    END
  END d[325]
  PIN d[326]
    DIRECTION INPUT ;
    USE SIGNAL ;
    PORT
      LAYER M4 ;
        RECT  0.054 46.56 0.138 46.584 ;
    END
  END d[326]
  PIN d[327]
    DIRECTION INPUT ;
    USE SIGNAL ;
    PORT
      LAYER M4 ;
        RECT  0.054 46.704 0.138 46.728 ;
    END
  END d[327]
  PIN d[328]
    DIRECTION INPUT ;
    USE SIGNAL ;
    PORT
      LAYER M4 ;
        RECT  0.054 46.8 0.138 46.824 ;
    END
  END d[328]
  PIN d[329]
    DIRECTION INPUT ;
    USE SIGNAL ;
    PORT
      LAYER M4 ;
        RECT  0.054 46.944 0.138 46.968 ;
    END
  END d[329]
  PIN d[32]
    DIRECTION INPUT ;
    USE SIGNAL ;
    PORT
      LAYER M4 ;
        RECT  0.054 9.408 0.138 9.432 ;
    END
  END d[32]
  PIN d[330]
    DIRECTION INPUT ;
    USE SIGNAL ;
    PORT
      LAYER M4 ;
        RECT  0.054 47.088 0.138 47.112 ;
    END
  END d[330]
  PIN d[331]
    DIRECTION INPUT ;
    USE SIGNAL ;
    PORT
      LAYER M4 ;
        RECT  0.054 47.184 0.138 47.208 ;
    END
  END d[331]
  PIN d[332]
    DIRECTION INPUT ;
    USE SIGNAL ;
    PORT
      LAYER M4 ;
        RECT  0.054 47.328 0.138 47.352 ;
    END
  END d[332]
  PIN d[333]
    DIRECTION INPUT ;
    USE SIGNAL ;
    PORT
      LAYER M4 ;
        RECT  0.054 47.472 0.138 47.496 ;
    END
  END d[333]
  PIN d[334]
    DIRECTION INPUT ;
    USE SIGNAL ;
    PORT
      LAYER M4 ;
        RECT  0.054 47.568 0.138 47.592 ;
    END
  END d[334]
  PIN d[335]
    DIRECTION INPUT ;
    USE SIGNAL ;
    PORT
      LAYER M4 ;
        RECT  0.054 47.712 0.138 47.736 ;
    END
  END d[335]
  PIN d[336]
    DIRECTION INPUT ;
    USE SIGNAL ;
    PORT
      LAYER M4 ;
        RECT  0.054 47.808 0.138 47.832 ;
    END
  END d[336]
  PIN d[337]
    DIRECTION INPUT ;
    USE SIGNAL ;
    PORT
      LAYER M4 ;
        RECT  0.054 47.952 0.138 47.976 ;
    END
  END d[337]
  PIN d[338]
    DIRECTION INPUT ;
    USE SIGNAL ;
    PORT
      LAYER M4 ;
        RECT  0.054 48.096 0.138 48.12 ;
    END
  END d[338]
  PIN d[339]
    DIRECTION INPUT ;
    USE SIGNAL ;
    PORT
      LAYER M4 ;
        RECT  0.054 48.192 0.138 48.216 ;
    END
  END d[339]
  PIN d[33]
    DIRECTION INPUT ;
    USE SIGNAL ;
    PORT
      LAYER M4 ;
        RECT  0.054 9.552 0.138 9.576 ;
    END
  END d[33]
  PIN d[340]
    DIRECTION INPUT ;
    USE SIGNAL ;
    PORT
      LAYER M4 ;
        RECT  0.054 48.336 0.138 48.36 ;
    END
  END d[340]
  PIN d[341]
    DIRECTION INPUT ;
    USE SIGNAL ;
    PORT
      LAYER M4 ;
        RECT  0.054 48.48 0.138 48.504 ;
    END
  END d[341]
  PIN d[342]
    DIRECTION INPUT ;
    USE SIGNAL ;
    PORT
      LAYER M4 ;
        RECT  0.054 48.576 0.138 48.6 ;
    END
  END d[342]
  PIN d[343]
    DIRECTION INPUT ;
    USE SIGNAL ;
    PORT
      LAYER M4 ;
        RECT  0.054 48.72 0.138 48.744 ;
    END
  END d[343]
  PIN d[344]
    DIRECTION INPUT ;
    USE SIGNAL ;
    PORT
      LAYER M4 ;
        RECT  0.054 48.864 0.138 48.888 ;
    END
  END d[344]
  PIN d[345]
    DIRECTION INPUT ;
    USE SIGNAL ;
    PORT
      LAYER M4 ;
        RECT  0.054 48.96 0.138 48.984 ;
    END
  END d[345]
  PIN d[346]
    DIRECTION INPUT ;
    USE SIGNAL ;
    PORT
      LAYER M4 ;
        RECT  0.054 49.104 0.138 49.128 ;
    END
  END d[346]
  PIN d[347]
    DIRECTION INPUT ;
    USE SIGNAL ;
    PORT
      LAYER M4 ;
        RECT  0.054 49.2 0.138 49.224 ;
    END
  END d[347]
  PIN d[348]
    DIRECTION INPUT ;
    USE SIGNAL ;
    PORT
      LAYER M4 ;
        RECT  0.054 49.344 0.138 49.368 ;
    END
  END d[348]
  PIN d[349]
    DIRECTION INPUT ;
    USE SIGNAL ;
    PORT
      LAYER M4 ;
        RECT  0.054 49.488 0.138 49.512 ;
    END
  END d[349]
  PIN d[34]
    DIRECTION INPUT ;
    USE SIGNAL ;
    PORT
      LAYER M4 ;
        RECT  0.054 9.696 0.138 9.72 ;
    END
  END d[34]
  PIN d[350]
    DIRECTION INPUT ;
    USE SIGNAL ;
    PORT
      LAYER M4 ;
        RECT  0.054 49.584 0.138 49.608 ;
    END
  END d[350]
  PIN d[351]
    DIRECTION INPUT ;
    USE SIGNAL ;
    PORT
      LAYER M4 ;
        RECT  0.054 49.728 0.138 49.752 ;
    END
  END d[351]
  PIN d[352]
    DIRECTION INPUT ;
    USE SIGNAL ;
    PORT
      LAYER M4 ;
        RECT  0.054 49.872 0.138 49.896 ;
    END
  END d[352]
  PIN d[353]
    DIRECTION INPUT ;
    USE SIGNAL ;
    PORT
      LAYER M4 ;
        RECT  0.054 49.968 0.138 49.992 ;
    END
  END d[353]
  PIN d[354]
    DIRECTION INPUT ;
    USE SIGNAL ;
    PORT
      LAYER M4 ;
        RECT  0.054 50.112 0.138 50.136 ;
    END
  END d[354]
  PIN d[355]
    DIRECTION INPUT ;
    USE SIGNAL ;
    PORT
      LAYER M4 ;
        RECT  0.054 50.208 0.138 50.232 ;
    END
  END d[355]
  PIN d[356]
    DIRECTION INPUT ;
    USE SIGNAL ;
    PORT
      LAYER M4 ;
        RECT  0.054 50.352 0.138 50.376 ;
    END
  END d[356]
  PIN d[357]
    DIRECTION INPUT ;
    USE SIGNAL ;
    PORT
      LAYER M4 ;
        RECT  0.054 50.496 0.138 50.52 ;
    END
  END d[357]
  PIN d[358]
    DIRECTION INPUT ;
    USE SIGNAL ;
    PORT
      LAYER M4 ;
        RECT  0.054 50.592 0.138 50.616 ;
    END
  END d[358]
  PIN d[359]
    DIRECTION INPUT ;
    USE SIGNAL ;
    PORT
      LAYER M4 ;
        RECT  0.054 50.736 0.138 50.76 ;
    END
  END d[359]
  PIN d[35]
    DIRECTION INPUT ;
    USE SIGNAL ;
    PORT
      LAYER M4 ;
        RECT  0.054 9.792 0.138 9.816 ;
    END
  END d[35]
  PIN d[360]
    DIRECTION INPUT ;
    USE SIGNAL ;
    PORT
      LAYER M4 ;
        RECT  0.054 50.88 0.138 50.904 ;
    END
  END d[360]
  PIN d[361]
    DIRECTION INPUT ;
    USE SIGNAL ;
    PORT
      LAYER M4 ;
        RECT  0.054 50.976 0.138 51 ;
    END
  END d[361]
  PIN d[362]
    DIRECTION INPUT ;
    USE SIGNAL ;
    PORT
      LAYER M4 ;
        RECT  0.054 51.12 0.138 51.144 ;
    END
  END d[362]
  PIN d[363]
    DIRECTION INPUT ;
    USE SIGNAL ;
    PORT
      LAYER M4 ;
        RECT  0.054 51.264 0.138 51.288 ;
    END
  END d[363]
  PIN d[364]
    DIRECTION INPUT ;
    USE SIGNAL ;
    PORT
      LAYER M4 ;
        RECT  0.054 51.36 0.138 51.384 ;
    END
  END d[364]
  PIN d[365]
    DIRECTION INPUT ;
    USE SIGNAL ;
    PORT
      LAYER M4 ;
        RECT  0.054 51.504 0.138 51.528 ;
    END
  END d[365]
  PIN d[366]
    DIRECTION INPUT ;
    USE SIGNAL ;
    PORT
      LAYER M4 ;
        RECT  0.054 51.6 0.138 51.624 ;
    END
  END d[366]
  PIN d[367]
    DIRECTION INPUT ;
    USE SIGNAL ;
    PORT
      LAYER M4 ;
        RECT  0.054 51.744 0.138 51.768 ;
    END
  END d[367]
  PIN d[368]
    DIRECTION INPUT ;
    USE SIGNAL ;
    PORT
      LAYER M4 ;
        RECT  0.054 51.888 0.138 51.912 ;
    END
  END d[368]
  PIN d[369]
    DIRECTION INPUT ;
    USE SIGNAL ;
    PORT
      LAYER M4 ;
        RECT  0.054 51.984 0.138 52.008 ;
    END
  END d[369]
  PIN d[36]
    DIRECTION INPUT ;
    USE SIGNAL ;
    PORT
      LAYER M4 ;
        RECT  0.054 9.936 0.138 9.96 ;
    END
  END d[36]
  PIN d[370]
    DIRECTION INPUT ;
    USE SIGNAL ;
    PORT
      LAYER M4 ;
        RECT  0.054 52.128 0.138 52.152 ;
    END
  END d[370]
  PIN d[371]
    DIRECTION INPUT ;
    USE SIGNAL ;
    PORT
      LAYER M4 ;
        RECT  0.054 52.272 0.138 52.296 ;
    END
  END d[371]
  PIN d[372]
    DIRECTION INPUT ;
    USE SIGNAL ;
    PORT
      LAYER M4 ;
        RECT  0.054 52.368 0.138 52.392 ;
    END
  END d[372]
  PIN d[373]
    DIRECTION INPUT ;
    USE SIGNAL ;
    PORT
      LAYER M4 ;
        RECT  0.054 52.512 0.138 52.536 ;
    END
  END d[373]
  PIN d[374]
    DIRECTION INPUT ;
    USE SIGNAL ;
    PORT
      LAYER M4 ;
        RECT  0.054 52.608 0.138 52.632 ;
    END
  END d[374]
  PIN d[375]
    DIRECTION INPUT ;
    USE SIGNAL ;
    PORT
      LAYER M4 ;
        RECT  0.054 52.752 0.138 52.776 ;
    END
  END d[375]
  PIN d[376]
    DIRECTION INPUT ;
    USE SIGNAL ;
    PORT
      LAYER M4 ;
        RECT  0.054 52.896 0.138 52.92 ;
    END
  END d[376]
  PIN d[377]
    DIRECTION INPUT ;
    USE SIGNAL ;
    PORT
      LAYER M4 ;
        RECT  0.054 52.992 0.138 53.016 ;
    END
    PORT
      LAYER M4 ;
        RECT  0.025 52.992 0.108 53.016 ;
    END
  END d[377]
  PIN d[378]
    DIRECTION INPUT ;
    USE SIGNAL ;
    PORT
      LAYER M4 ;
        RECT  0.054 53.136 0.138 53.16 ;
    END
  END d[378]
  PIN d[379]
    DIRECTION INPUT ;
    USE SIGNAL ;
    PORT
      LAYER M4 ;
        RECT  0.054 53.28 0.138 53.304 ;
    END
  END d[379]
  PIN d[37]
    DIRECTION INPUT ;
    USE SIGNAL ;
    PORT
      LAYER M4 ;
        RECT  0.054 10.08 0.138 10.104 ;
    END
  END d[37]
  PIN d[380]
    DIRECTION INPUT ;
    USE SIGNAL ;
    PORT
      LAYER M4 ;
        RECT  0.054 53.376 0.138 53.4 ;
    END
  END d[380]
  PIN d[381]
    DIRECTION INPUT ;
    USE SIGNAL ;
    PORT
      LAYER M4 ;
        RECT  0.054 53.52 0.138 53.544 ;
    END
  END d[381]
  PIN d[382]
    DIRECTION INPUT ;
    USE SIGNAL ;
    PORT
      LAYER M4 ;
        RECT  0.054 53.664 0.138 53.688 ;
    END
  END d[382]
  PIN d[383]
    DIRECTION INPUT ;
    USE SIGNAL ;
    PORT
      LAYER M4 ;
        RECT  0.054 53.76 0.138 53.784 ;
    END
  END d[383]
  PIN d[384]
    DIRECTION INPUT ;
    USE SIGNAL ;
    PORT
      LAYER M4 ;
        RECT  0.054 53.904 0.138 53.928 ;
    END
  END d[384]
  PIN d[385]
    DIRECTION INPUT ;
    USE SIGNAL ;
    PORT
      LAYER M4 ;
        RECT  0.054 54 0.138 54.024 ;
    END
  END d[385]
  PIN d[386]
    DIRECTION INPUT ;
    USE SIGNAL ;
    PORT
      LAYER M4 ;
        RECT  0.054 54.144 0.138 54.168 ;
    END
  END d[386]
  PIN d[387]
    DIRECTION INPUT ;
    USE SIGNAL ;
    PORT
      LAYER M4 ;
        RECT  0.054 54.288 0.138 54.312 ;
    END
  END d[387]
  PIN d[388]
    DIRECTION INPUT ;
    USE SIGNAL ;
    PORT
      LAYER M4 ;
        RECT  0.054 54.384 0.138 54.408 ;
    END
  END d[388]
  PIN d[389]
    DIRECTION INPUT ;
    USE SIGNAL ;
    PORT
      LAYER M4 ;
        RECT  0.054 54.528 0.138 54.552 ;
    END
  END d[389]
  PIN d[38]
    DIRECTION INPUT ;
    USE SIGNAL ;
    PORT
      LAYER M4 ;
        RECT  0.054 10.176 0.138 10.2 ;
    END
  END d[38]
  PIN d[390]
    DIRECTION INPUT ;
    USE SIGNAL ;
    PORT
      LAYER M4 ;
        RECT  0.054 54.672 0.138 54.696 ;
    END
  END d[390]
  PIN d[391]
    DIRECTION INPUT ;
    USE SIGNAL ;
    PORT
      LAYER M4 ;
        RECT  0.054 54.768 0.138 54.792 ;
    END
  END d[391]
  PIN d[392]
    DIRECTION INPUT ;
    USE SIGNAL ;
    PORT
      LAYER M4 ;
        RECT  0.054 54.912 0.138 54.936 ;
    END
  END d[392]
  PIN d[393]
    DIRECTION INPUT ;
    USE SIGNAL ;
    PORT
      LAYER M4 ;
        RECT  0.054 55.008 0.138 55.032 ;
    END
  END d[393]
  PIN d[394]
    DIRECTION INPUT ;
    USE SIGNAL ;
    PORT
      LAYER M4 ;
        RECT  0.054 55.152 0.138 55.176 ;
    END
  END d[394]
  PIN d[395]
    DIRECTION INPUT ;
    USE SIGNAL ;
    PORT
      LAYER M4 ;
        RECT  0.054 55.296 0.138 55.32 ;
    END
  END d[395]
  PIN d[396]
    DIRECTION INPUT ;
    USE SIGNAL ;
    PORT
      LAYER M4 ;
        RECT  0.054 55.392 0.138 55.416 ;
    END
  END d[396]
  PIN d[397]
    DIRECTION INPUT ;
    USE SIGNAL ;
    PORT
      LAYER M4 ;
        RECT  0.054 55.536 0.138 55.56 ;
    END
  END d[397]
  PIN d[398]
    DIRECTION INPUT ;
    USE SIGNAL ;
    PORT
      LAYER M4 ;
        RECT  0.054 55.68 0.138 55.704 ;
    END
  END d[398]
  PIN d[399]
    DIRECTION INPUT ;
    USE SIGNAL ;
    PORT
      LAYER M4 ;
        RECT  0.054 55.776 0.138 55.8 ;
    END
  END d[399]
  PIN d[39]
    DIRECTION INPUT ;
    USE SIGNAL ;
    PORT
      LAYER M4 ;
        RECT  0.054 10.32 0.138 10.344 ;
    END
  END d[39]
  PIN d[3]
    DIRECTION INPUT ;
    USE SIGNAL ;
    PORT
      LAYER M4 ;
        RECT  0.054 5.76 0.138 5.784 ;
    END
  END d[3]
  PIN d[400]
    DIRECTION INPUT ;
    USE SIGNAL ;
    PORT
      LAYER M4 ;
        RECT  0.054 55.92 0.138 55.944 ;
    END
  END d[400]
  PIN d[401]
    DIRECTION INPUT ;
    USE SIGNAL ;
    PORT
      LAYER M4 ;
        RECT  0.054 56.064 0.138 56.088 ;
    END
  END d[401]
  PIN d[402]
    DIRECTION INPUT ;
    USE SIGNAL ;
    PORT
      LAYER M4 ;
        RECT  0.054 56.16 0.138 56.184 ;
    END
  END d[402]
  PIN d[403]
    DIRECTION INPUT ;
    USE SIGNAL ;
    PORT
      LAYER M4 ;
        RECT  0.054 56.304 0.138 56.328 ;
    END
  END d[403]
  PIN d[404]
    DIRECTION INPUT ;
    USE SIGNAL ;
    PORT
      LAYER M4 ;
        RECT  0.054 56.4 0.138 56.424 ;
    END
  END d[404]
  PIN d[405]
    DIRECTION INPUT ;
    USE SIGNAL ;
    PORT
      LAYER M4 ;
        RECT  0.054 56.544 0.138 56.568 ;
    END
  END d[405]
  PIN d[406]
    DIRECTION INPUT ;
    USE SIGNAL ;
    PORT
      LAYER M4 ;
        RECT  0.054 56.688 0.138 56.712 ;
    END
  END d[406]
  PIN d[407]
    DIRECTION INPUT ;
    USE SIGNAL ;
    PORT
      LAYER M4 ;
        RECT  0.054 56.784 0.138 56.808 ;
    END
  END d[407]
  PIN d[408]
    DIRECTION INPUT ;
    USE SIGNAL ;
    PORT
      LAYER M4 ;
        RECT  0.054 56.928 0.138 56.952 ;
    END
  END d[408]
  PIN d[409]
    DIRECTION INPUT ;
    USE SIGNAL ;
    PORT
      LAYER M4 ;
        RECT  0.054 57.072 0.138 57.096 ;
    END
  END d[409]
  PIN d[40]
    DIRECTION INPUT ;
    USE SIGNAL ;
    PORT
      LAYER M4 ;
        RECT  0.054 10.464 0.138 10.488 ;
    END
  END d[40]
  PIN d[410]
    DIRECTION INPUT ;
    USE SIGNAL ;
    PORT
      LAYER M4 ;
        RECT  0.054 57.168 0.138 57.192 ;
    END
  END d[410]
  PIN d[411]
    DIRECTION INPUT ;
    USE SIGNAL ;
    PORT
      LAYER M4 ;
        RECT  0.054 57.312 0.138 57.336 ;
    END
  END d[411]
  PIN d[412]
    DIRECTION INPUT ;
    USE SIGNAL ;
    PORT
      LAYER M4 ;
        RECT  0.054 57.408 0.138 57.432 ;
    END
  END d[412]
  PIN d[413]
    DIRECTION INPUT ;
    USE SIGNAL ;
    PORT
      LAYER M4 ;
        RECT  0.054 57.552 0.138 57.576 ;
    END
  END d[413]
  PIN d[414]
    DIRECTION INPUT ;
    USE SIGNAL ;
    PORT
      LAYER M4 ;
        RECT  0.054 57.696 0.138 57.72 ;
    END
  END d[414]
  PIN d[415]
    DIRECTION INPUT ;
    USE SIGNAL ;
    PORT
      LAYER M4 ;
        RECT  0.054 57.792 0.138 57.816 ;
    END
  END d[415]
  PIN d[416]
    DIRECTION INPUT ;
    USE SIGNAL ;
    PORT
      LAYER M4 ;
        RECT  0.054 57.936 0.138 57.96 ;
    END
  END d[416]
  PIN d[417]
    DIRECTION INPUT ;
    USE SIGNAL ;
    PORT
      LAYER M4 ;
        RECT  0.054 58.08 0.138 58.104 ;
    END
  END d[417]
  PIN d[418]
    DIRECTION INPUT ;
    USE SIGNAL ;
    PORT
      LAYER M4 ;
        RECT  0.054 58.176 0.138 58.2 ;
    END
  END d[418]
  PIN d[419]
    DIRECTION INPUT ;
    USE SIGNAL ;
    PORT
      LAYER M4 ;
        RECT  0.054 58.32 0.138 58.344 ;
    END
  END d[419]
  PIN d[41]
    DIRECTION INPUT ;
    USE SIGNAL ;
    PORT
      LAYER M4 ;
        RECT  0.054 10.56 0.138 10.584 ;
    END
  END d[41]
  PIN d[420]
    DIRECTION INPUT ;
    USE SIGNAL ;
    PORT
      LAYER M4 ;
        RECT  0.054 58.464 0.138 58.488 ;
    END
  END d[420]
  PIN d[421]
    DIRECTION INPUT ;
    USE SIGNAL ;
    PORT
      LAYER M4 ;
        RECT  0.054 58.56 0.138 58.584 ;
    END
  END d[421]
  PIN d[422]
    DIRECTION INPUT ;
    USE SIGNAL ;
    PORT
      LAYER M4 ;
        RECT  0.054 58.704 0.138 58.728 ;
    END
  END d[422]
  PIN d[423]
    DIRECTION INPUT ;
    USE SIGNAL ;
    PORT
      LAYER M4 ;
        RECT  0.054 58.8 0.138 58.824 ;
    END
  END d[423]
  PIN d[424]
    DIRECTION INPUT ;
    USE SIGNAL ;
    PORT
      LAYER M4 ;
        RECT  0.054 58.944 0.138 58.968 ;
    END
  END d[424]
  PIN d[425]
    DIRECTION INPUT ;
    USE SIGNAL ;
    PORT
      LAYER M4 ;
        RECT  0.054 59.088 0.138 59.112 ;
    END
  END d[425]
  PIN d[426]
    DIRECTION INPUT ;
    USE SIGNAL ;
    PORT
      LAYER M4 ;
        RECT  0.054 59.184 0.138 59.208 ;
    END
  END d[426]
  PIN d[427]
    DIRECTION INPUT ;
    USE SIGNAL ;
    PORT
      LAYER M4 ;
        RECT  0.054 59.328 0.138 59.352 ;
    END
  END d[427]
  PIN d[428]
    DIRECTION INPUT ;
    USE SIGNAL ;
    PORT
      LAYER M4 ;
        RECT  0.054 59.472 0.138 59.496 ;
    END
  END d[428]
  PIN d[429]
    DIRECTION INPUT ;
    USE SIGNAL ;
    PORT
      LAYER M4 ;
        RECT  0.054 59.568 0.138 59.592 ;
    END
  END d[429]
  PIN d[42]
    DIRECTION INPUT ;
    USE SIGNAL ;
    PORT
      LAYER M4 ;
        RECT  0.054 10.704 0.138 10.728 ;
    END
  END d[42]
  PIN d[430]
    DIRECTION INPUT ;
    USE SIGNAL ;
    PORT
      LAYER M4 ;
        RECT  0.054 59.712 0.138 59.736 ;
    END
  END d[430]
  PIN d[431]
    DIRECTION INPUT ;
    USE SIGNAL ;
    PORT
      LAYER M4 ;
        RECT  0.054 59.808 0.138 59.832 ;
    END
  END d[431]
  PIN d[432]
    DIRECTION INPUT ;
    USE SIGNAL ;
    PORT
      LAYER M4 ;
        RECT  0.054 59.952 0.138 59.976 ;
    END
  END d[432]
  PIN d[433]
    DIRECTION INPUT ;
    USE SIGNAL ;
    PORT
      LAYER M4 ;
        RECT  0.054 60.096 0.138 60.12 ;
    END
  END d[433]
  PIN d[434]
    DIRECTION INPUT ;
    USE SIGNAL ;
    PORT
      LAYER M4 ;
        RECT  0.054 60.192 0.138 60.216 ;
    END
  END d[434]
  PIN d[435]
    DIRECTION INPUT ;
    USE SIGNAL ;
    PORT
      LAYER M4 ;
        RECT  0.054 60.336 0.138 60.36 ;
    END
  END d[435]
  PIN d[436]
    DIRECTION INPUT ;
    USE SIGNAL ;
    PORT
      LAYER M4 ;
        RECT  0.054 60.48 0.138 60.504 ;
    END
  END d[436]
  PIN d[437]
    DIRECTION INPUT ;
    USE SIGNAL ;
    PORT
      LAYER M4 ;
        RECT  0.054 60.576 0.138 60.6 ;
    END
  END d[437]
  PIN d[438]
    DIRECTION INPUT ;
    USE SIGNAL ;
    PORT
      LAYER M4 ;
        RECT  0.054 60.72 0.138 60.744 ;
    END
  END d[438]
  PIN d[439]
    DIRECTION INPUT ;
    USE SIGNAL ;
    PORT
      LAYER M4 ;
        RECT  0.054 60.864 0.138 60.888 ;
    END
  END d[439]
  PIN d[43]
    DIRECTION INPUT ;
    USE SIGNAL ;
    PORT
      LAYER M4 ;
        RECT  0.054 10.8 0.138 10.824 ;
    END
  END d[43]
  PIN d[440]
    DIRECTION INPUT ;
    USE SIGNAL ;
    PORT
      LAYER M4 ;
        RECT  0.054 60.96 0.138 60.984 ;
    END
  END d[440]
  PIN d[441]
    DIRECTION INPUT ;
    USE SIGNAL ;
    PORT
      LAYER M4 ;
        RECT  0.054 61.104 0.138 61.128 ;
    END
  END d[441]
  PIN d[442]
    DIRECTION INPUT ;
    USE SIGNAL ;
    PORT
      LAYER M4 ;
        RECT  0.054 61.2 0.138 61.224 ;
    END
  END d[442]
  PIN d[443]
    DIRECTION INPUT ;
    USE SIGNAL ;
    PORT
      LAYER M4 ;
        RECT  0.054 61.344 0.138 61.368 ;
    END
  END d[443]
  PIN d[444]
    DIRECTION INPUT ;
    USE SIGNAL ;
    PORT
      LAYER M4 ;
        RECT  0.054 61.488 0.138 61.512 ;
    END
  END d[444]
  PIN d[445]
    DIRECTION INPUT ;
    USE SIGNAL ;
    PORT
      LAYER M4 ;
        RECT  0.054 61.584 0.138 61.608 ;
    END
  END d[445]
  PIN d[446]
    DIRECTION INPUT ;
    USE SIGNAL ;
    PORT
      LAYER M4 ;
        RECT  0.054 61.728 0.138 61.752 ;
    END
  END d[446]
  PIN d[447]
    DIRECTION INPUT ;
    USE SIGNAL ;
    PORT
      LAYER M4 ;
        RECT  0.054 61.872 0.138 61.896 ;
    END
  END d[447]
  PIN d[448]
    DIRECTION INPUT ;
    USE SIGNAL ;
    PORT
      LAYER M4 ;
        RECT  0.054 61.968 0.138 61.992 ;
    END
  END d[448]
  PIN d[449]
    DIRECTION INPUT ;
    USE SIGNAL ;
    PORT
      LAYER M4 ;
        RECT  0.054 62.112 0.138 62.136 ;
    END
  END d[449]
  PIN d[44]
    DIRECTION INPUT ;
    USE SIGNAL ;
    PORT
      LAYER M4 ;
        RECT  0.054 10.944 0.138 10.968 ;
    END
  END d[44]
  PIN d[450]
    DIRECTION INPUT ;
    USE SIGNAL ;
    PORT
      LAYER M4 ;
        RECT  0.054 62.208 0.138 62.232 ;
    END
  END d[450]
  PIN d[451]
    DIRECTION INPUT ;
    USE SIGNAL ;
    PORT
      LAYER M4 ;
        RECT  0.054 62.352 0.138 62.376 ;
    END
  END d[451]
  PIN d[452]
    DIRECTION INPUT ;
    USE SIGNAL ;
    PORT
      LAYER M4 ;
        RECT  0.054 62.496 0.138 62.52 ;
    END
  END d[452]
  PIN d[453]
    DIRECTION INPUT ;
    USE SIGNAL ;
    PORT
      LAYER M4 ;
        RECT  0.054 62.592 0.138 62.616 ;
    END
  END d[453]
  PIN d[454]
    DIRECTION INPUT ;
    USE SIGNAL ;
    PORT
      LAYER M4 ;
        RECT  0.054 62.736 0.138 62.76 ;
    END
  END d[454]
  PIN d[455]
    DIRECTION INPUT ;
    USE SIGNAL ;
    PORT
      LAYER M4 ;
        RECT  0.054 62.88 0.138 62.904 ;
    END
  END d[455]
  PIN d[456]
    DIRECTION INPUT ;
    USE SIGNAL ;
    PORT
      LAYER M4 ;
        RECT  0.054 62.976 0.138 63 ;
    END
  END d[456]
  PIN d[457]
    DIRECTION INPUT ;
    USE SIGNAL ;
    PORT
      LAYER M4 ;
        RECT  0.054 63.12 0.138 63.144 ;
    END
  END d[457]
  PIN d[458]
    DIRECTION INPUT ;
    USE SIGNAL ;
    PORT
      LAYER M4 ;
        RECT  0.054 63.264 0.138 63.288 ;
    END
  END d[458]
  PIN d[459]
    DIRECTION INPUT ;
    USE SIGNAL ;
    PORT
      LAYER M4 ;
        RECT  0.054 63.36 0.138 63.384 ;
    END
  END d[459]
  PIN d[45]
    DIRECTION INPUT ;
    USE SIGNAL ;
    PORT
      LAYER M4 ;
        RECT  0.054 11.088 0.138 11.112 ;
    END
  END d[45]
  PIN d[460]
    DIRECTION INPUT ;
    USE SIGNAL ;
    PORT
      LAYER M4 ;
        RECT  0.054 63.504 0.138 63.528 ;
    END
  END d[460]
  PIN d[461]
    DIRECTION INPUT ;
    USE SIGNAL ;
    PORT
      LAYER M4 ;
        RECT  0.054 63.6 0.138 63.624 ;
    END
  END d[461]
  PIN d[462]
    DIRECTION INPUT ;
    USE SIGNAL ;
    PORT
      LAYER M4 ;
        RECT  0.054 63.744 0.138 63.768 ;
    END
  END d[462]
  PIN d[463]
    DIRECTION INPUT ;
    USE SIGNAL ;
    PORT
      LAYER M4 ;
        RECT  0.054 63.888 0.138 63.912 ;
    END
  END d[463]
  PIN d[464]
    DIRECTION INPUT ;
    USE SIGNAL ;
    PORT
      LAYER M4 ;
        RECT  0.054 63.984 0.138 64.008 ;
    END
  END d[464]
  PIN d[465]
    DIRECTION INPUT ;
    USE SIGNAL ;
    PORT
      LAYER M4 ;
        RECT  0.054 64.128 0.138 64.152 ;
    END
  END d[465]
  PIN d[466]
    DIRECTION INPUT ;
    USE SIGNAL ;
    PORT
      LAYER M4 ;
        RECT  0.054 64.272 0.138 64.296 ;
    END
  END d[466]
  PIN d[467]
    DIRECTION INPUT ;
    USE SIGNAL ;
    PORT
      LAYER M4 ;
        RECT  0.054 64.368 0.138 64.392 ;
    END
  END d[467]
  PIN d[468]
    DIRECTION INPUT ;
    USE SIGNAL ;
    PORT
      LAYER M4 ;
        RECT  0.054 64.512 0.138 64.536 ;
    END
  END d[468]
  PIN d[469]
    DIRECTION INPUT ;
    USE SIGNAL ;
    PORT
      LAYER M4 ;
        RECT  0.054 64.608 0.138 64.632 ;
    END
  END d[469]
  PIN d[46]
    DIRECTION INPUT ;
    USE SIGNAL ;
    PORT
      LAYER M4 ;
        RECT  0.054 11.184 0.138 11.208 ;
    END
  END d[46]
  PIN d[470]
    DIRECTION INPUT ;
    USE SIGNAL ;
    PORT
      LAYER M4 ;
        RECT  0.054 64.752 0.138 64.776 ;
    END
  END d[470]
  PIN d[471]
    DIRECTION INPUT ;
    USE SIGNAL ;
    PORT
      LAYER M4 ;
        RECT  0.054 64.896 0.138 64.92 ;
    END
  END d[471]
  PIN d[472]
    DIRECTION INPUT ;
    USE SIGNAL ;
    PORT
      LAYER M4 ;
        RECT  0.054 64.992 0.138 65.016 ;
    END
  END d[472]
  PIN d[473]
    DIRECTION INPUT ;
    USE SIGNAL ;
    PORT
      LAYER M4 ;
        RECT  0.054 65.136 0.138 65.16 ;
    END
  END d[473]
  PIN d[474]
    DIRECTION INPUT ;
    USE SIGNAL ;
    PORT
      LAYER M4 ;
        RECT  0.054 65.28 0.138 65.304 ;
    END
  END d[474]
  PIN d[475]
    DIRECTION INPUT ;
    USE SIGNAL ;
    PORT
      LAYER M4 ;
        RECT  0.054 65.376 0.138 65.4 ;
    END
  END d[475]
  PIN d[476]
    DIRECTION INPUT ;
    USE SIGNAL ;
    PORT
      LAYER M4 ;
        RECT  0.054 65.52 0.138 65.544 ;
    END
  END d[476]
  PIN d[477]
    DIRECTION INPUT ;
    USE SIGNAL ;
    PORT
      LAYER M4 ;
        RECT  0.054 65.664 0.138 65.688 ;
    END
  END d[477]
  PIN d[478]
    DIRECTION INPUT ;
    USE SIGNAL ;
    PORT
      LAYER M4 ;
        RECT  0.054 65.76 0.138 65.784 ;
    END
  END d[478]
  PIN d[479]
    DIRECTION INPUT ;
    USE SIGNAL ;
    PORT
      LAYER M4 ;
        RECT  0.054 65.904 0.138 65.928 ;
    END
  END d[479]
  PIN d[47]
    DIRECTION INPUT ;
    USE SIGNAL ;
    PORT
      LAYER M4 ;
        RECT  0.054 11.328 0.138 11.352 ;
    END
  END d[47]
  PIN d[480]
    DIRECTION INPUT ;
    USE SIGNAL ;
    PORT
      LAYER M4 ;
        RECT  0.054 66 0.138 66.024 ;
    END
  END d[480]
  PIN d[481]
    DIRECTION INPUT ;
    USE SIGNAL ;
    PORT
      LAYER M4 ;
        RECT  0.054 66.144 0.138 66.168 ;
    END
  END d[481]
  PIN d[482]
    DIRECTION INPUT ;
    USE SIGNAL ;
    PORT
      LAYER M4 ;
        RECT  0.054 66.288 0.138 66.312 ;
    END
  END d[482]
  PIN d[483]
    DIRECTION INPUT ;
    USE SIGNAL ;
    PORT
      LAYER M4 ;
        RECT  0.054 66.384 0.138 66.408 ;
    END
  END d[483]
  PIN d[484]
    DIRECTION INPUT ;
    USE SIGNAL ;
    PORT
      LAYER M4 ;
        RECT  0.054 66.528 0.138 66.552 ;
    END
  END d[484]
  PIN d[485]
    DIRECTION INPUT ;
    USE SIGNAL ;
    PORT
      LAYER M4 ;
        RECT  0.054 66.672 0.138 66.696 ;
    END
  END d[485]
  PIN d[486]
    DIRECTION INPUT ;
    USE SIGNAL ;
    PORT
      LAYER M4 ;
        RECT  0.054 66.768 0.138 66.792 ;
    END
  END d[486]
  PIN d[487]
    DIRECTION INPUT ;
    USE SIGNAL ;
    PORT
      LAYER M4 ;
        RECT  0.054 66.912 0.138 66.936 ;
    END
  END d[487]
  PIN d[488]
    DIRECTION INPUT ;
    USE SIGNAL ;
    PORT
      LAYER M4 ;
        RECT  0.054 67.008 0.138 67.032 ;
    END
  END d[488]
  PIN d[489]
    DIRECTION INPUT ;
    USE SIGNAL ;
    PORT
      LAYER M4 ;
        RECT  0.054 67.152 0.138 67.176 ;
    END
  END d[489]
  PIN d[48]
    DIRECTION INPUT ;
    USE SIGNAL ;
    PORT
      LAYER M4 ;
        RECT  0.054 11.472 0.138 11.496 ;
    END
  END d[48]
  PIN d[490]
    DIRECTION INPUT ;
    USE SIGNAL ;
    PORT
      LAYER M4 ;
        RECT  0.054 67.296 0.138 67.32 ;
    END
  END d[490]
  PIN d[491]
    DIRECTION INPUT ;
    USE SIGNAL ;
    PORT
      LAYER M4 ;
        RECT  0.054 67.392 0.138 67.416 ;
    END
  END d[491]
  PIN d[492]
    DIRECTION INPUT ;
    USE SIGNAL ;
    PORT
      LAYER M4 ;
        RECT  0.054 67.536 0.138 67.56 ;
    END
  END d[492]
  PIN d[493]
    DIRECTION INPUT ;
    USE SIGNAL ;
    PORT
      LAYER M4 ;
        RECT  0.054 67.68 0.138 67.704 ;
    END
  END d[493]
  PIN d[494]
    DIRECTION INPUT ;
    USE SIGNAL ;
    PORT
      LAYER M4 ;
        RECT  0.054 67.776 0.138 67.8 ;
    END
  END d[494]
  PIN d[495]
    DIRECTION INPUT ;
    USE SIGNAL ;
    PORT
      LAYER M4 ;
        RECT  0.054 67.92 0.138 67.944 ;
    END
  END d[495]
  PIN d[496]
    DIRECTION INPUT ;
    USE SIGNAL ;
    PORT
      LAYER M4 ;
        RECT  0.054 68.064 0.138 68.088 ;
    END
  END d[496]
  PIN d[497]
    DIRECTION INPUT ;
    USE SIGNAL ;
    PORT
      LAYER M4 ;
        RECT  0.054 68.16 0.138 68.184 ;
    END
  END d[497]
  PIN d[498]
    DIRECTION INPUT ;
    USE SIGNAL ;
    PORT
      LAYER M4 ;
        RECT  0.054 68.304 0.138 68.328 ;
    END
  END d[498]
  PIN d[499]
    DIRECTION INPUT ;
    USE SIGNAL ;
    PORT
      LAYER M4 ;
        RECT  0.054 68.4 0.138 68.424 ;
    END
  END d[499]
  PIN d[49]
    DIRECTION INPUT ;
    USE SIGNAL ;
    PORT
      LAYER M4 ;
        RECT  0.054 11.568 0.138 11.592 ;
    END
  END d[49]
  PIN d[4]
    DIRECTION INPUT ;
    USE SIGNAL ;
    PORT
      LAYER M4 ;
        RECT  0.054 5.904 0.138 5.928 ;
    END
  END d[4]
  PIN d[500]
    DIRECTION INPUT ;
    USE SIGNAL ;
    PORT
      LAYER M4 ;
        RECT  0.054 68.544 0.138 68.568 ;
    END
  END d[500]
  PIN d[501]
    DIRECTION INPUT ;
    USE SIGNAL ;
    PORT
      LAYER M4 ;
        RECT  0.054 68.688 0.138 68.712 ;
    END
  END d[501]
  PIN d[502]
    DIRECTION INPUT ;
    USE SIGNAL ;
    PORT
      LAYER M4 ;
        RECT  0.054 68.784 0.138 68.808 ;
    END
  END d[502]
  PIN d[503]
    DIRECTION INPUT ;
    USE SIGNAL ;
    PORT
      LAYER M4 ;
        RECT  0.054 68.928 0.138 68.952 ;
    END
  END d[503]
  PIN d[504]
    DIRECTION INPUT ;
    USE SIGNAL ;
    PORT
      LAYER M4 ;
        RECT  0.054 69.072 0.138 69.096 ;
    END
  END d[504]
  PIN d[505]
    DIRECTION INPUT ;
    USE SIGNAL ;
    PORT
      LAYER M4 ;
        RECT  0.054 69.168 0.138 69.192 ;
    END
  END d[505]
  PIN d[506]
    DIRECTION INPUT ;
    USE SIGNAL ;
    PORT
      LAYER M4 ;
        RECT  0.054 69.312 0.138 69.336 ;
    END
  END d[506]
  PIN d[507]
    DIRECTION INPUT ;
    USE SIGNAL ;
    PORT
      LAYER M4 ;
        RECT  0.054 69.408 0.138 69.432 ;
    END
  END d[507]
  PIN d[508]
    DIRECTION INPUT ;
    USE SIGNAL ;
    PORT
      LAYER M4 ;
        RECT  0.054 69.552 0.138 69.576 ;
    END
  END d[508]
  PIN d[509]
    DIRECTION INPUT ;
    USE SIGNAL ;
    PORT
      LAYER M4 ;
        RECT  0.054 69.696 0.138 69.72 ;
    END
  END d[509]
  PIN d[50]
    DIRECTION INPUT ;
    USE SIGNAL ;
    PORT
      LAYER M4 ;
        RECT  0.054 11.712 0.138 11.736 ;
    END
  END d[50]
  PIN d[510]
    DIRECTION INPUT ;
    USE SIGNAL ;
    PORT
      LAYER M4 ;
        RECT  0.054 69.792 0.138 69.816 ;
    END
    PORT
      LAYER M4 ;
        RECT  0.025 69.792 0.108 69.816 ;
    END
  END d[510]
  PIN d[511]
    DIRECTION INPUT ;
    USE SIGNAL ;
    PORT
      LAYER M4 ;
        RECT  0.054 69.936 0.138 69.96 ;
    END
  END d[511]
  PIN d[512]
    DIRECTION INPUT ;
    USE SIGNAL ;
    PORT
      LAYER M4 ;
        RECT  0.054 70.08 0.138 70.104 ;
    END
  END d[512]
  PIN d[513]
    DIRECTION INPUT ;
    USE SIGNAL ;
    PORT
      LAYER M4 ;
        RECT  0.054 70.176 0.138 70.2 ;
    END
  END d[513]
  PIN d[51]
    DIRECTION INPUT ;
    USE SIGNAL ;
    PORT
      LAYER M4 ;
        RECT  0.054 11.808 0.138 11.832 ;
    END
  END d[51]
  PIN d[52]
    DIRECTION INPUT ;
    USE SIGNAL ;
    PORT
      LAYER M4 ;
        RECT  0.054 11.952 0.138 11.976 ;
    END
    PORT
      LAYER M4 ;
        RECT  0.025 11.952 0.108 11.976 ;
    END
  END d[52]
  PIN d[53]
    DIRECTION INPUT ;
    USE SIGNAL ;
    PORT
      LAYER M4 ;
        RECT  0.054 12.096 0.138 12.12 ;
    END
  END d[53]
  PIN d[54]
    DIRECTION INPUT ;
    USE SIGNAL ;
    PORT
      LAYER M4 ;
        RECT  0.054 12.192 0.138 12.216 ;
    END
  END d[54]
  PIN d[55]
    DIRECTION INPUT ;
    USE SIGNAL ;
    PORT
      LAYER M4 ;
        RECT  0.054 12.336 0.138 12.36 ;
    END
  END d[55]
  PIN d[56]
    DIRECTION INPUT ;
    USE SIGNAL ;
    PORT
      LAYER M4 ;
        RECT  0.054 12.48 0.138 12.504 ;
    END
  END d[56]
  PIN d[57]
    DIRECTION INPUT ;
    USE SIGNAL ;
    PORT
      LAYER M4 ;
        RECT  0.054 12.576 0.138 12.6 ;
    END
  END d[57]
  PIN d[58]
    DIRECTION INPUT ;
    USE SIGNAL ;
    PORT
      LAYER M4 ;
        RECT  0.054 12.72 0.138 12.744 ;
    END
  END d[58]
  PIN d[59]
    DIRECTION INPUT ;
    USE SIGNAL ;
    PORT
      LAYER M4 ;
        RECT  0.054 12.864 0.138 12.888 ;
    END
  END d[59]
  PIN d[5]
    DIRECTION INPUT ;
    USE SIGNAL ;
    PORT
      LAYER M4 ;
        RECT  0.054 6 0.138 6.024 ;
    END
  END d[5]
  PIN d[60]
    DIRECTION INPUT ;
    USE SIGNAL ;
    PORT
      LAYER M4 ;
        RECT  0.054 12.96 0.138 12.984 ;
    END
  END d[60]
  PIN d[61]
    DIRECTION INPUT ;
    USE SIGNAL ;
    PORT
      LAYER M4 ;
        RECT  0.054 13.104 0.138 13.128 ;
    END
  END d[61]
  PIN d[62]
    DIRECTION INPUT ;
    USE SIGNAL ;
    PORT
      LAYER M4 ;
        RECT  0.054 13.2 0.138 13.224 ;
    END
  END d[62]
  PIN d[63]
    DIRECTION INPUT ;
    USE SIGNAL ;
    PORT
      LAYER M4 ;
        RECT  0.054 13.344 0.138 13.368 ;
    END
  END d[63]
  PIN d[64]
    DIRECTION INPUT ;
    USE SIGNAL ;
    PORT
      LAYER M4 ;
        RECT  0.054 13.488 0.138 13.512 ;
    END
  END d[64]
  PIN d[65]
    DIRECTION INPUT ;
    USE SIGNAL ;
    PORT
      LAYER M4 ;
        RECT  0.054 13.584 0.138 13.608 ;
    END
  END d[65]
  PIN d[66]
    DIRECTION INPUT ;
    USE SIGNAL ;
    PORT
      LAYER M4 ;
        RECT  0.054 13.728 0.138 13.752 ;
    END
  END d[66]
  PIN d[67]
    DIRECTION INPUT ;
    USE SIGNAL ;
    PORT
      LAYER M4 ;
        RECT  0.054 13.872 0.138 13.896 ;
    END
  END d[67]
  PIN d[68]
    DIRECTION INPUT ;
    USE SIGNAL ;
    PORT
      LAYER M4 ;
        RECT  0.054 13.968 0.138 13.992 ;
    END
  END d[68]
  PIN d[69]
    DIRECTION INPUT ;
    USE SIGNAL ;
    PORT
      LAYER M4 ;
        RECT  0.054 14.112 0.138 14.136 ;
    END
  END d[69]
  PIN d[6]
    DIRECTION INPUT ;
    USE SIGNAL ;
    PORT
      LAYER M4 ;
        RECT  0.054 6.144 0.138 6.168 ;
    END
  END d[6]
  PIN d[70]
    DIRECTION INPUT ;
    USE SIGNAL ;
    PORT
      LAYER M4 ;
        RECT  0.054 14.208 0.138 14.232 ;
    END
  END d[70]
  PIN d[71]
    DIRECTION INPUT ;
    USE SIGNAL ;
    PORT
      LAYER M4 ;
        RECT  0.054 14.352 0.138 14.376 ;
    END
  END d[71]
  PIN d[72]
    DIRECTION INPUT ;
    USE SIGNAL ;
    PORT
      LAYER M4 ;
        RECT  0.054 14.496 0.138 14.52 ;
    END
  END d[72]
  PIN d[73]
    DIRECTION INPUT ;
    USE SIGNAL ;
    PORT
      LAYER M4 ;
        RECT  0.054 14.592 0.138 14.616 ;
    END
  END d[73]
  PIN d[74]
    DIRECTION INPUT ;
    USE SIGNAL ;
    PORT
      LAYER M4 ;
        RECT  0.054 14.736 0.138 14.76 ;
    END
  END d[74]
  PIN d[75]
    DIRECTION INPUT ;
    USE SIGNAL ;
    PORT
      LAYER M4 ;
        RECT  0.054 14.88 0.138 14.904 ;
    END
  END d[75]
  PIN d[76]
    DIRECTION INPUT ;
    USE SIGNAL ;
    PORT
      LAYER M4 ;
        RECT  0.054 14.976 0.138 15 ;
    END
  END d[76]
  PIN d[77]
    DIRECTION INPUT ;
    USE SIGNAL ;
    PORT
      LAYER M4 ;
        RECT  0.054 15.12 0.138 15.144 ;
    END
  END d[77]
  PIN d[78]
    DIRECTION INPUT ;
    USE SIGNAL ;
    PORT
      LAYER M4 ;
        RECT  0.054 15.264 0.138 15.288 ;
    END
  END d[78]
  PIN d[79]
    DIRECTION INPUT ;
    USE SIGNAL ;
    PORT
      LAYER M4 ;
        RECT  0.054 15.36 0.138 15.384 ;
    END
  END d[79]
  PIN d[7]
    DIRECTION INPUT ;
    USE SIGNAL ;
    PORT
      LAYER M4 ;
        RECT  0.054 6.288 0.138 6.312 ;
    END
  END d[7]
  PIN d[80]
    DIRECTION INPUT ;
    USE SIGNAL ;
    PORT
      LAYER M4 ;
        RECT  0.054 15.504 0.138 15.528 ;
    END
  END d[80]
  PIN d[81]
    DIRECTION INPUT ;
    USE SIGNAL ;
    PORT
      LAYER M4 ;
        RECT  0.054 15.6 0.138 15.624 ;
    END
  END d[81]
  PIN d[82]
    DIRECTION INPUT ;
    USE SIGNAL ;
    PORT
      LAYER M4 ;
        RECT  0.054 15.744 0.138 15.768 ;
    END
  END d[82]
  PIN d[83]
    DIRECTION INPUT ;
    USE SIGNAL ;
    PORT
      LAYER M4 ;
        RECT  0.054 15.888 0.138 15.912 ;
    END
  END d[83]
  PIN d[84]
    DIRECTION INPUT ;
    USE SIGNAL ;
    PORT
      LAYER M4 ;
        RECT  0.054 15.984 0.138 16.008 ;
    END
  END d[84]
  PIN d[85]
    DIRECTION INPUT ;
    USE SIGNAL ;
    PORT
      LAYER M4 ;
        RECT  0.054 16.128 0.138 16.152 ;
    END
  END d[85]
  PIN d[86]
    DIRECTION INPUT ;
    USE SIGNAL ;
    PORT
      LAYER M4 ;
        RECT  0.054 16.272 0.138 16.296 ;
    END
    PORT
      LAYER M4 ;
        RECT  0.025 16.272 0.108 16.296 ;
    END
  END d[86]
  PIN d[87]
    DIRECTION INPUT ;
    USE SIGNAL ;
    PORT
      LAYER M4 ;
        RECT  0.054 16.368 0.138 16.392 ;
    END
  END d[87]
  PIN d[88]
    DIRECTION INPUT ;
    USE SIGNAL ;
    PORT
      LAYER M4 ;
        RECT  0.054 16.512 0.138 16.536 ;
    END
  END d[88]
  PIN d[89]
    DIRECTION INPUT ;
    USE SIGNAL ;
    PORT
      LAYER M4 ;
        RECT  0.054 16.608 0.138 16.632 ;
    END
  END d[89]
  PIN d[8]
    DIRECTION INPUT ;
    USE SIGNAL ;
    PORT
      LAYER M4 ;
        RECT  0.054 6.384 0.138 6.408 ;
    END
  END d[8]
  PIN d[90]
    DIRECTION INPUT ;
    USE SIGNAL ;
    PORT
      LAYER M4 ;
        RECT  0.054 16.752 0.138 16.776 ;
    END
  END d[90]
  PIN d[91]
    DIRECTION INPUT ;
    USE SIGNAL ;
    PORT
      LAYER M4 ;
        RECT  0.054 16.896 0.138 16.92 ;
    END
  END d[91]
  PIN d[92]
    DIRECTION INPUT ;
    USE SIGNAL ;
    PORT
      LAYER M4 ;
        RECT  0.054 16.992 0.138 17.016 ;
    END
  END d[92]
  PIN d[93]
    DIRECTION INPUT ;
    USE SIGNAL ;
    PORT
      LAYER M4 ;
        RECT  0.054 17.136 0.138 17.16 ;
    END
  END d[93]
  PIN d[94]
    DIRECTION INPUT ;
    USE SIGNAL ;
    PORT
      LAYER M4 ;
        RECT  0.054 17.28 0.138 17.304 ;
    END
  END d[94]
  PIN d[95]
    DIRECTION INPUT ;
    USE SIGNAL ;
    PORT
      LAYER M4 ;
        RECT  0.054 17.376 0.138 17.4 ;
    END
  END d[95]
  PIN d[96]
    DIRECTION INPUT ;
    USE SIGNAL ;
    PORT
      LAYER M4 ;
        RECT  0.054 17.52 0.138 17.544 ;
    END
  END d[96]
  PIN d[97]
    DIRECTION INPUT ;
    USE SIGNAL ;
    PORT
      LAYER M4 ;
        RECT  0.054 17.664 0.138 17.688 ;
    END
  END d[97]
  PIN d[98]
    DIRECTION INPUT ;
    USE SIGNAL ;
    PORT
      LAYER M4 ;
        RECT  0.054 17.76 0.138 17.784 ;
    END
  END d[98]
  PIN d[99]
    DIRECTION INPUT ;
    USE SIGNAL ;
    PORT
      LAYER M4 ;
        RECT  0.054 17.904 0.138 17.928 ;
    END
  END d[99]
  PIN d[9]
    DIRECTION INPUT ;
    USE SIGNAL ;
    PORT
      LAYER M4 ;
        RECT  0.054 6.528 0.138 6.552 ;
    END
  END d[9]
  PIN q[0]
    DIRECTION OUTPUT ;
    USE SIGNAL ;
    PORT
      LAYER M4 ;
        RECT  21.462 5.424 21.546 5.448 ;
    END
  END q[0]
  PIN q[100]
    DIRECTION OUTPUT ;
    USE SIGNAL ;
    PORT
      LAYER M4 ;
        RECT  21.462 18 21.546 18.024 ;
    END
  END q[100]
  PIN q[101]
    DIRECTION OUTPUT ;
    USE SIGNAL ;
    PORT
      LAYER M4 ;
        RECT  21.462 18.144 21.546 18.168 ;
    END
  END q[101]
  PIN q[102]
    DIRECTION OUTPUT ;
    USE SIGNAL ;
    PORT
      LAYER M4 ;
        RECT  21.462 18.288 21.546 18.312 ;
    END
  END q[102]
  PIN q[103]
    DIRECTION OUTPUT ;
    USE SIGNAL ;
    PORT
      LAYER M4 ;
        RECT  21.462 18.384 21.546 18.408 ;
    END
  END q[103]
  PIN q[104]
    DIRECTION OUTPUT ;
    USE SIGNAL ;
    PORT
      LAYER M4 ;
        RECT  21.462 18.528 21.546 18.552 ;
    END
  END q[104]
  PIN q[105]
    DIRECTION OUTPUT ;
    USE SIGNAL ;
    PORT
      LAYER M4 ;
        RECT  21.462 18.672 21.546 18.696 ;
    END
  END q[105]
  PIN q[106]
    DIRECTION OUTPUT ;
    USE SIGNAL ;
    PORT
      LAYER M4 ;
        RECT  21.462 18.768 21.546 18.792 ;
    END
  END q[106]
  PIN q[107]
    DIRECTION OUTPUT ;
    USE SIGNAL ;
    PORT
      LAYER M4 ;
        RECT  21.462 18.912 21.546 18.936 ;
    END
  END q[107]
  PIN q[108]
    DIRECTION OUTPUT ;
    USE SIGNAL ;
    PORT
      LAYER M4 ;
        RECT  21.462 19.008 21.546 19.032 ;
    END
  END q[108]
  PIN q[109]
    DIRECTION OUTPUT ;
    USE SIGNAL ;
    PORT
      LAYER M4 ;
        RECT  21.462 19.152 21.546 19.176 ;
    END
  END q[109]
  PIN q[10]
    DIRECTION OUTPUT ;
    USE SIGNAL ;
    PORT
      LAYER M4 ;
        RECT  21.462 6.672 21.546 6.696 ;
    END
  END q[10]
  PIN q[110]
    DIRECTION OUTPUT ;
    USE SIGNAL ;
    PORT
      LAYER M4 ;
        RECT  21.462 19.296 21.546 19.32 ;
    END
  END q[110]
  PIN q[111]
    DIRECTION OUTPUT ;
    USE SIGNAL ;
    PORT
      LAYER M4 ;
        RECT  21.462 19.392 21.546 19.416 ;
    END
  END q[111]
  PIN q[112]
    DIRECTION OUTPUT ;
    USE SIGNAL ;
    PORT
      LAYER M4 ;
        RECT  21.462 19.536 21.546 19.56 ;
    END
  END q[112]
  PIN q[113]
    DIRECTION OUTPUT ;
    USE SIGNAL ;
    PORT
      LAYER M4 ;
        RECT  21.462 19.68 21.546 19.704 ;
    END
  END q[113]
  PIN q[114]
    DIRECTION OUTPUT ;
    USE SIGNAL ;
    PORT
      LAYER M4 ;
        RECT  21.462 19.776 21.546 19.8 ;
    END
  END q[114]
  PIN q[115]
    DIRECTION OUTPUT ;
    USE SIGNAL ;
    PORT
      LAYER M4 ;
        RECT  21.462 19.92 21.546 19.944 ;
    END
  END q[115]
  PIN q[116]
    DIRECTION OUTPUT ;
    USE SIGNAL ;
    PORT
      LAYER M4 ;
        RECT  21.462 20.064 21.546 20.088 ;
    END
  END q[116]
  PIN q[117]
    DIRECTION OUTPUT ;
    USE SIGNAL ;
    PORT
      LAYER M4 ;
        RECT  21.462 20.16 21.546 20.184 ;
    END
  END q[117]
  PIN q[118]
    DIRECTION OUTPUT ;
    USE SIGNAL ;
    PORT
      LAYER M4 ;
        RECT  21.462 20.304 21.546 20.328 ;
    END
  END q[118]
  PIN q[119]
    DIRECTION OUTPUT ;
    USE SIGNAL ;
    PORT
      LAYER M4 ;
        RECT  21.462 20.4 21.546 20.424 ;
    END
  END q[119]
  PIN q[11]
    DIRECTION OUTPUT ;
    USE SIGNAL ;
    PORT
      LAYER M4 ;
        RECT  21.462 6.768 21.546 6.792 ;
    END
  END q[11]
  PIN q[120]
    DIRECTION OUTPUT ;
    USE SIGNAL ;
    PORT
      LAYER M4 ;
        RECT  21.462 20.544 21.546 20.568 ;
    END
  END q[120]
  PIN q[121]
    DIRECTION OUTPUT ;
    USE SIGNAL ;
    PORT
      LAYER M4 ;
        RECT  21.462 20.688 21.546 20.712 ;
    END
  END q[121]
  PIN q[122]
    DIRECTION OUTPUT ;
    USE SIGNAL ;
    PORT
      LAYER M4 ;
        RECT  21.462 20.784 21.546 20.808 ;
    END
  END q[122]
  PIN q[123]
    DIRECTION OUTPUT ;
    USE SIGNAL ;
    PORT
      LAYER M4 ;
        RECT  21.462 20.928 21.546 20.952 ;
    END
  END q[123]
  PIN q[124]
    DIRECTION OUTPUT ;
    USE SIGNAL ;
    PORT
      LAYER M4 ;
        RECT  21.462 21.072 21.546 21.096 ;
    END
  END q[124]
  PIN q[125]
    DIRECTION OUTPUT ;
    USE SIGNAL ;
    PORT
      LAYER M4 ;
        RECT  21.462 21.168 21.546 21.192 ;
    END
  END q[125]
  PIN q[126]
    DIRECTION OUTPUT ;
    USE SIGNAL ;
    PORT
      LAYER M4 ;
        RECT  21.462 21.312 21.546 21.336 ;
    END
  END q[126]
  PIN q[127]
    DIRECTION OUTPUT ;
    USE SIGNAL ;
    PORT
      LAYER M4 ;
        RECT  21.462 21.408 21.546 21.432 ;
    END
  END q[127]
  PIN q[128]
    DIRECTION OUTPUT ;
    USE SIGNAL ;
    PORT
      LAYER M4 ;
        RECT  21.462 21.552 21.546 21.576 ;
    END
  END q[128]
  PIN q[129]
    DIRECTION OUTPUT ;
    USE SIGNAL ;
    PORT
      LAYER M4 ;
        RECT  21.462 21.696 21.546 21.72 ;
    END
  END q[129]
  PIN q[12]
    DIRECTION OUTPUT ;
    USE SIGNAL ;
    PORT
      LAYER M4 ;
        RECT  21.462 6.912 21.546 6.936 ;
    END
  END q[12]
  PIN q[130]
    DIRECTION OUTPUT ;
    USE SIGNAL ;
    PORT
      LAYER M4 ;
        RECT  21.462 21.792 21.546 21.816 ;
    END
  END q[130]
  PIN q[131]
    DIRECTION OUTPUT ;
    USE SIGNAL ;
    PORT
      LAYER M4 ;
        RECT  21.462 21.936 21.546 21.96 ;
    END
  END q[131]
  PIN q[132]
    DIRECTION OUTPUT ;
    USE SIGNAL ;
    PORT
      LAYER M4 ;
        RECT  21.462 22.08 21.546 22.104 ;
    END
  END q[132]
  PIN q[133]
    DIRECTION OUTPUT ;
    USE SIGNAL ;
    PORT
      LAYER M4 ;
        RECT  21.462 22.176 21.546 22.2 ;
    END
  END q[133]
  PIN q[134]
    DIRECTION OUTPUT ;
    USE SIGNAL ;
    PORT
      LAYER M4 ;
        RECT  21.462 22.32 21.546 22.344 ;
    END
  END q[134]
  PIN q[135]
    DIRECTION OUTPUT ;
    USE SIGNAL ;
    PORT
      LAYER M4 ;
        RECT  21.462 22.464 21.546 22.488 ;
    END
  END q[135]
  PIN q[136]
    DIRECTION OUTPUT ;
    USE SIGNAL ;
    PORT
      LAYER M4 ;
        RECT  21.462 22.56 21.546 22.584 ;
    END
  END q[136]
  PIN q[137]
    DIRECTION OUTPUT ;
    USE SIGNAL ;
    PORT
      LAYER M4 ;
        RECT  21.462 22.704 21.546 22.728 ;
    END
  END q[137]
  PIN q[138]
    DIRECTION OUTPUT ;
    USE SIGNAL ;
    PORT
      LAYER M4 ;
        RECT  21.462 22.8 21.546 22.824 ;
    END
  END q[138]
  PIN q[139]
    DIRECTION OUTPUT ;
    USE SIGNAL ;
    PORT
      LAYER M4 ;
        RECT  21.462 22.944 21.546 22.968 ;
    END
  END q[139]
  PIN q[13]
    DIRECTION OUTPUT ;
    USE SIGNAL ;
    PORT
      LAYER M4 ;
        RECT  21.462 7.008 21.546 7.032 ;
    END
  END q[13]
  PIN q[140]
    DIRECTION OUTPUT ;
    USE SIGNAL ;
    PORT
      LAYER M4 ;
        RECT  21.462 23.088 21.546 23.112 ;
    END
  END q[140]
  PIN q[141]
    DIRECTION OUTPUT ;
    USE SIGNAL ;
    PORT
      LAYER M4 ;
        RECT  21.462 23.184 21.546 23.208 ;
    END
  END q[141]
  PIN q[142]
    DIRECTION OUTPUT ;
    USE SIGNAL ;
    PORT
      LAYER M4 ;
        RECT  21.462 23.328 21.546 23.352 ;
    END
  END q[142]
  PIN q[143]
    DIRECTION OUTPUT ;
    USE SIGNAL ;
    PORT
      LAYER M4 ;
        RECT  21.462 23.472 21.546 23.496 ;
    END
  END q[143]
  PIN q[144]
    DIRECTION OUTPUT ;
    USE SIGNAL ;
    PORT
      LAYER M4 ;
        RECT  21.462 23.568 21.546 23.592 ;
    END
  END q[144]
  PIN q[145]
    DIRECTION OUTPUT ;
    USE SIGNAL ;
    PORT
      LAYER M4 ;
        RECT  21.462 23.712 21.546 23.736 ;
    END
  END q[145]
  PIN q[146]
    DIRECTION OUTPUT ;
    USE SIGNAL ;
    PORT
      LAYER M4 ;
        RECT  21.462 23.808 21.546 23.832 ;
    END
  END q[146]
  PIN q[147]
    DIRECTION OUTPUT ;
    USE SIGNAL ;
    PORT
      LAYER M4 ;
        RECT  21.462 23.952 21.546 23.976 ;
    END
  END q[147]
  PIN q[148]
    DIRECTION OUTPUT ;
    USE SIGNAL ;
    PORT
      LAYER M4 ;
        RECT  21.462 24.096 21.546 24.12 ;
    END
  END q[148]
  PIN q[149]
    DIRECTION OUTPUT ;
    USE SIGNAL ;
    PORT
      LAYER M4 ;
        RECT  21.462 24.192 21.546 24.216 ;
    END
  END q[149]
  PIN q[14]
    DIRECTION OUTPUT ;
    USE SIGNAL ;
    PORT
      LAYER M4 ;
        RECT  21.462 7.152 21.546 7.176 ;
    END
  END q[14]
  PIN q[150]
    DIRECTION OUTPUT ;
    USE SIGNAL ;
    PORT
      LAYER M4 ;
        RECT  21.462 24.336 21.546 24.36 ;
    END
  END q[150]
  PIN q[151]
    DIRECTION OUTPUT ;
    USE SIGNAL ;
    PORT
      LAYER M4 ;
        RECT  21.462 24.48 21.546 24.504 ;
    END
  END q[151]
  PIN q[152]
    DIRECTION OUTPUT ;
    USE SIGNAL ;
    PORT
      LAYER M4 ;
        RECT  21.462 24.576 21.546 24.6 ;
    END
  END q[152]
  PIN q[153]
    DIRECTION OUTPUT ;
    USE SIGNAL ;
    PORT
      LAYER M4 ;
        RECT  21.462 24.72 21.546 24.744 ;
    END
  END q[153]
  PIN q[154]
    DIRECTION OUTPUT ;
    USE SIGNAL ;
    PORT
      LAYER M4 ;
        RECT  21.462 24.864 21.546 24.888 ;
    END
  END q[154]
  PIN q[155]
    DIRECTION OUTPUT ;
    USE SIGNAL ;
    PORT
      LAYER M4 ;
        RECT  21.462 24.96 21.546 24.984 ;
    END
  END q[155]
  PIN q[156]
    DIRECTION OUTPUT ;
    USE SIGNAL ;
    PORT
      LAYER M4 ;
        RECT  21.462 25.104 21.546 25.128 ;
    END
  END q[156]
  PIN q[157]
    DIRECTION OUTPUT ;
    USE SIGNAL ;
    PORT
      LAYER M4 ;
        RECT  21.462 25.2 21.546 25.224 ;
    END
  END q[157]
  PIN q[158]
    DIRECTION OUTPUT ;
    USE SIGNAL ;
    PORT
      LAYER M4 ;
        RECT  21.462 25.344 21.546 25.368 ;
    END
  END q[158]
  PIN q[159]
    DIRECTION OUTPUT ;
    USE SIGNAL ;
    PORT
      LAYER M4 ;
        RECT  21.462 25.488 21.546 25.512 ;
    END
  END q[159]
  PIN q[15]
    DIRECTION OUTPUT ;
    USE SIGNAL ;
    PORT
      LAYER M4 ;
        RECT  21.462 7.296 21.546 7.32 ;
    END
  END q[15]
  PIN q[160]
    DIRECTION OUTPUT ;
    USE SIGNAL ;
    PORT
      LAYER M4 ;
        RECT  21.462 25.584 21.546 25.608 ;
    END
  END q[160]
  PIN q[161]
    DIRECTION OUTPUT ;
    USE SIGNAL ;
    PORT
      LAYER M4 ;
        RECT  21.462 25.728 21.546 25.752 ;
    END
  END q[161]
  PIN q[162]
    DIRECTION OUTPUT ;
    USE SIGNAL ;
    PORT
      LAYER M4 ;
        RECT  21.462 25.872 21.546 25.896 ;
    END
  END q[162]
  PIN q[163]
    DIRECTION OUTPUT ;
    USE SIGNAL ;
    PORT
      LAYER M4 ;
        RECT  21.462 25.968 21.546 25.992 ;
    END
  END q[163]
  PIN q[164]
    DIRECTION OUTPUT ;
    USE SIGNAL ;
    PORT
      LAYER M4 ;
        RECT  21.462 26.112 21.546 26.136 ;
    END
  END q[164]
  PIN q[165]
    DIRECTION OUTPUT ;
    USE SIGNAL ;
    PORT
      LAYER M4 ;
        RECT  21.462 26.208 21.546 26.232 ;
    END
  END q[165]
  PIN q[166]
    DIRECTION OUTPUT ;
    USE SIGNAL ;
    PORT
      LAYER M4 ;
        RECT  21.462 26.352 21.546 26.376 ;
    END
  END q[166]
  PIN q[167]
    DIRECTION OUTPUT ;
    USE SIGNAL ;
    PORT
      LAYER M4 ;
        RECT  21.462 26.496 21.546 26.52 ;
    END
  END q[167]
  PIN q[168]
    DIRECTION OUTPUT ;
    USE SIGNAL ;
    PORT
      LAYER M4 ;
        RECT  21.462 26.592 21.546 26.616 ;
    END
  END q[168]
  PIN q[169]
    DIRECTION OUTPUT ;
    USE SIGNAL ;
    PORT
      LAYER M4 ;
        RECT  21.462 26.736 21.546 26.76 ;
    END
  END q[169]
  PIN q[16]
    DIRECTION OUTPUT ;
    USE SIGNAL ;
    PORT
      LAYER M4 ;
        RECT  21.462 7.392 21.546 7.416 ;
    END
  END q[16]
  PIN q[170]
    DIRECTION OUTPUT ;
    USE SIGNAL ;
    PORT
      LAYER M4 ;
        RECT  21.462 26.88 21.546 26.904 ;
    END
  END q[170]
  PIN q[171]
    DIRECTION OUTPUT ;
    USE SIGNAL ;
    PORT
      LAYER M4 ;
        RECT  21.462 26.976 21.546 27 ;
    END
  END q[171]
  PIN q[172]
    DIRECTION OUTPUT ;
    USE SIGNAL ;
    PORT
      LAYER M4 ;
        RECT  21.462 27.12 21.546 27.144 ;
    END
  END q[172]
  PIN q[173]
    DIRECTION OUTPUT ;
    USE SIGNAL ;
    PORT
      LAYER M4 ;
        RECT  21.462 27.264 21.546 27.288 ;
    END
  END q[173]
  PIN q[174]
    DIRECTION OUTPUT ;
    USE SIGNAL ;
    PORT
      LAYER M4 ;
        RECT  21.462 27.36 21.546 27.384 ;
    END
  END q[174]
  PIN q[175]
    DIRECTION OUTPUT ;
    USE SIGNAL ;
    PORT
      LAYER M4 ;
        RECT  21.462 27.504 21.546 27.528 ;
    END
  END q[175]
  PIN q[176]
    DIRECTION OUTPUT ;
    USE SIGNAL ;
    PORT
      LAYER M4 ;
        RECT  21.462 27.6 21.546 27.624 ;
    END
  END q[176]
  PIN q[177]
    DIRECTION OUTPUT ;
    USE SIGNAL ;
    PORT
      LAYER M4 ;
        RECT  21.462 27.744 21.546 27.768 ;
    END
  END q[177]
  PIN q[178]
    DIRECTION OUTPUT ;
    USE SIGNAL ;
    PORT
      LAYER M4 ;
        RECT  21.462 27.888 21.546 27.912 ;
    END
  END q[178]
  PIN q[179]
    DIRECTION OUTPUT ;
    USE SIGNAL ;
    PORT
      LAYER M4 ;
        RECT  21.462 27.984 21.546 28.008 ;
    END
  END q[179]
  PIN q[17]
    DIRECTION OUTPUT ;
    USE SIGNAL ;
    PORT
      LAYER M4 ;
        RECT  21.462 7.536 21.546 7.56 ;
    END
  END q[17]
  PIN q[180]
    DIRECTION OUTPUT ;
    USE SIGNAL ;
    PORT
      LAYER M4 ;
        RECT  21.462 28.128 21.546 28.152 ;
    END
  END q[180]
  PIN q[181]
    DIRECTION OUTPUT ;
    USE SIGNAL ;
    PORT
      LAYER M4 ;
        RECT  21.462 28.272 21.546 28.296 ;
    END
  END q[181]
  PIN q[182]
    DIRECTION OUTPUT ;
    USE SIGNAL ;
    PORT
      LAYER M4 ;
        RECT  21.462 28.368 21.546 28.392 ;
    END
  END q[182]
  PIN q[183]
    DIRECTION OUTPUT ;
    USE SIGNAL ;
    PORT
      LAYER M4 ;
        RECT  21.462 28.512 21.546 28.536 ;
    END
  END q[183]
  PIN q[184]
    DIRECTION OUTPUT ;
    USE SIGNAL ;
    PORT
      LAYER M4 ;
        RECT  21.462 28.608 21.546 28.632 ;
    END
  END q[184]
  PIN q[185]
    DIRECTION OUTPUT ;
    USE SIGNAL ;
    PORT
      LAYER M4 ;
        RECT  21.462 28.752 21.546 28.776 ;
    END
  END q[185]
  PIN q[186]
    DIRECTION OUTPUT ;
    USE SIGNAL ;
    PORT
      LAYER M4 ;
        RECT  21.462 28.896 21.546 28.92 ;
    END
  END q[186]
  PIN q[187]
    DIRECTION OUTPUT ;
    USE SIGNAL ;
    PORT
      LAYER M4 ;
        RECT  21.462 28.992 21.546 29.016 ;
    END
  END q[187]
  PIN q[188]
    DIRECTION OUTPUT ;
    USE SIGNAL ;
    PORT
      LAYER M4 ;
        RECT  21.462 29.136 21.546 29.16 ;
    END
  END q[188]
  PIN q[189]
    DIRECTION OUTPUT ;
    USE SIGNAL ;
    PORT
      LAYER M4 ;
        RECT  21.462 29.28 21.546 29.304 ;
    END
  END q[189]
  PIN q[18]
    DIRECTION OUTPUT ;
    USE SIGNAL ;
    PORT
      LAYER M4 ;
        RECT  21.462 7.68 21.546 7.704 ;
    END
  END q[18]
  PIN q[190]
    DIRECTION OUTPUT ;
    USE SIGNAL ;
    PORT
      LAYER M4 ;
        RECT  21.462 29.376 21.546 29.4 ;
    END
  END q[190]
  PIN q[191]
    DIRECTION OUTPUT ;
    USE SIGNAL ;
    PORT
      LAYER M4 ;
        RECT  21.462 29.52 21.546 29.544 ;
    END
  END q[191]
  PIN q[192]
    DIRECTION OUTPUT ;
    USE SIGNAL ;
    PORT
      LAYER M4 ;
        RECT  21.462 29.664 21.546 29.688 ;
    END
  END q[192]
  PIN q[193]
    DIRECTION OUTPUT ;
    USE SIGNAL ;
    PORT
      LAYER M4 ;
        RECT  21.462 29.76 21.546 29.784 ;
    END
  END q[193]
  PIN q[194]
    DIRECTION OUTPUT ;
    USE SIGNAL ;
    PORT
      LAYER M4 ;
        RECT  21.462 29.904 21.546 29.928 ;
    END
  END q[194]
  PIN q[195]
    DIRECTION OUTPUT ;
    USE SIGNAL ;
    PORT
      LAYER M4 ;
        RECT  21.462 30 21.546 30.024 ;
    END
  END q[195]
  PIN q[196]
    DIRECTION OUTPUT ;
    USE SIGNAL ;
    PORT
      LAYER M4 ;
        RECT  21.462 30.144 21.546 30.168 ;
    END
  END q[196]
  PIN q[197]
    DIRECTION OUTPUT ;
    USE SIGNAL ;
    PORT
      LAYER M4 ;
        RECT  21.462 30.288 21.546 30.312 ;
    END
  END q[197]
  PIN q[198]
    DIRECTION OUTPUT ;
    USE SIGNAL ;
    PORT
      LAYER M4 ;
        RECT  21.462 30.384 21.546 30.408 ;
    END
  END q[198]
  PIN q[199]
    DIRECTION OUTPUT ;
    USE SIGNAL ;
    PORT
      LAYER M4 ;
        RECT  21.462 30.528 21.546 30.552 ;
    END
  END q[199]
  PIN q[19]
    DIRECTION OUTPUT ;
    USE SIGNAL ;
    PORT
      LAYER M4 ;
        RECT  21.462 7.776 21.546 7.8 ;
    END
  END q[19]
  PIN q[1]
    DIRECTION OUTPUT ;
    USE SIGNAL ;
    PORT
      LAYER M4 ;
        RECT  21.462 5.52 21.546 5.544 ;
    END
  END q[1]
  PIN q[200]
    DIRECTION OUTPUT ;
    USE SIGNAL ;
    PORT
      LAYER M4 ;
        RECT  21.462 30.672 21.546 30.696 ;
    END
  END q[200]
  PIN q[201]
    DIRECTION OUTPUT ;
    USE SIGNAL ;
    PORT
      LAYER M4 ;
        RECT  21.462 30.768 21.546 30.792 ;
    END
  END q[201]
  PIN q[202]
    DIRECTION OUTPUT ;
    USE SIGNAL ;
    PORT
      LAYER M4 ;
        RECT  21.462 30.912 21.546 30.936 ;
    END
  END q[202]
  PIN q[203]
    DIRECTION OUTPUT ;
    USE SIGNAL ;
    PORT
      LAYER M4 ;
        RECT  21.462 31.008 21.546 31.032 ;
    END
  END q[203]
  PIN q[204]
    DIRECTION OUTPUT ;
    USE SIGNAL ;
    PORT
      LAYER M4 ;
        RECT  21.462 31.152 21.546 31.176 ;
    END
  END q[204]
  PIN q[205]
    DIRECTION OUTPUT ;
    USE SIGNAL ;
    PORT
      LAYER M4 ;
        RECT  21.462 31.296 21.546 31.32 ;
    END
  END q[205]
  PIN q[206]
    DIRECTION OUTPUT ;
    USE SIGNAL ;
    PORT
      LAYER M4 ;
        RECT  21.462 31.392 21.546 31.416 ;
    END
  END q[206]
  PIN q[207]
    DIRECTION OUTPUT ;
    USE SIGNAL ;
    PORT
      LAYER M4 ;
        RECT  21.462 31.536 21.546 31.56 ;
    END
  END q[207]
  PIN q[208]
    DIRECTION OUTPUT ;
    USE SIGNAL ;
    PORT
      LAYER M4 ;
        RECT  21.462 31.68 21.546 31.704 ;
    END
  END q[208]
  PIN q[209]
    DIRECTION OUTPUT ;
    USE SIGNAL ;
    PORT
      LAYER M4 ;
        RECT  21.462 31.776 21.546 31.8 ;
    END
  END q[209]
  PIN q[20]
    DIRECTION OUTPUT ;
    USE SIGNAL ;
    PORT
      LAYER M4 ;
        RECT  21.462 7.92 21.546 7.944 ;
    END
  END q[20]
  PIN q[210]
    DIRECTION OUTPUT ;
    USE SIGNAL ;
    PORT
      LAYER M4 ;
        RECT  21.462 31.92 21.546 31.944 ;
    END
  END q[210]
  PIN q[211]
    DIRECTION OUTPUT ;
    USE SIGNAL ;
    PORT
      LAYER M4 ;
        RECT  21.462 32.064 21.546 32.088 ;
    END
  END q[211]
  PIN q[212]
    DIRECTION OUTPUT ;
    USE SIGNAL ;
    PORT
      LAYER M4 ;
        RECT  21.462 32.16 21.546 32.184 ;
    END
  END q[212]
  PIN q[213]
    DIRECTION OUTPUT ;
    USE SIGNAL ;
    PORT
      LAYER M4 ;
        RECT  21.462 32.304 21.546 32.328 ;
    END
  END q[213]
  PIN q[214]
    DIRECTION OUTPUT ;
    USE SIGNAL ;
    PORT
      LAYER M4 ;
        RECT  21.462 32.4 21.546 32.424 ;
    END
  END q[214]
  PIN q[215]
    DIRECTION OUTPUT ;
    USE SIGNAL ;
    PORT
      LAYER M4 ;
        RECT  21.462 32.544 21.546 32.568 ;
    END
  END q[215]
  PIN q[216]
    DIRECTION OUTPUT ;
    USE SIGNAL ;
    PORT
      LAYER M4 ;
        RECT  21.462 32.688 21.546 32.712 ;
    END
  END q[216]
  PIN q[217]
    DIRECTION OUTPUT ;
    USE SIGNAL ;
    PORT
      LAYER M4 ;
        RECT  21.462 32.784 21.546 32.808 ;
    END
  END q[217]
  PIN q[218]
    DIRECTION OUTPUT ;
    USE SIGNAL ;
    PORT
      LAYER M4 ;
        RECT  21.462 32.928 21.546 32.952 ;
    END
  END q[218]
  PIN q[219]
    DIRECTION OUTPUT ;
    USE SIGNAL ;
    PORT
      LAYER M4 ;
        RECT  21.462 33.072 21.546 33.096 ;
    END
  END q[219]
  PIN q[21]
    DIRECTION OUTPUT ;
    USE SIGNAL ;
    PORT
      LAYER M4 ;
        RECT  21.462 8.064 21.546 8.088 ;
    END
  END q[21]
  PIN q[220]
    DIRECTION OUTPUT ;
    USE SIGNAL ;
    PORT
      LAYER M4 ;
        RECT  21.462 33.168 21.546 33.192 ;
    END
  END q[220]
  PIN q[221]
    DIRECTION OUTPUT ;
    USE SIGNAL ;
    PORT
      LAYER M4 ;
        RECT  21.462 33.312 21.546 33.336 ;
    END
  END q[221]
  PIN q[222]
    DIRECTION OUTPUT ;
    USE SIGNAL ;
    PORT
      LAYER M4 ;
        RECT  21.462 33.408 21.546 33.432 ;
    END
  END q[222]
  PIN q[223]
    DIRECTION OUTPUT ;
    USE SIGNAL ;
    PORT
      LAYER M4 ;
        RECT  21.462 33.552 21.546 33.576 ;
    END
  END q[223]
  PIN q[224]
    DIRECTION OUTPUT ;
    USE SIGNAL ;
    PORT
      LAYER M4 ;
        RECT  21.462 33.696 21.546 33.72 ;
    END
  END q[224]
  PIN q[225]
    DIRECTION OUTPUT ;
    USE SIGNAL ;
    PORT
      LAYER M4 ;
        RECT  21.462 33.792 21.546 33.816 ;
    END
  END q[225]
  PIN q[226]
    DIRECTION OUTPUT ;
    USE SIGNAL ;
    PORT
      LAYER M4 ;
        RECT  21.462 33.936 21.546 33.96 ;
    END
  END q[226]
  PIN q[227]
    DIRECTION OUTPUT ;
    USE SIGNAL ;
    PORT
      LAYER M4 ;
        RECT  21.462 34.08 21.546 34.104 ;
    END
  END q[227]
  PIN q[228]
    DIRECTION OUTPUT ;
    USE SIGNAL ;
    PORT
      LAYER M4 ;
        RECT  21.462 34.176 21.546 34.2 ;
    END
  END q[228]
  PIN q[229]
    DIRECTION OUTPUT ;
    USE SIGNAL ;
    PORT
      LAYER M4 ;
        RECT  21.462 34.32 21.546 34.344 ;
    END
  END q[229]
  PIN q[22]
    DIRECTION OUTPUT ;
    USE SIGNAL ;
    PORT
      LAYER M4 ;
        RECT  21.462 8.16 21.546 8.184 ;
    END
  END q[22]
  PIN q[230]
    DIRECTION OUTPUT ;
    USE SIGNAL ;
    PORT
      LAYER M4 ;
        RECT  21.462 34.464 21.546 34.488 ;
    END
  END q[230]
  PIN q[231]
    DIRECTION OUTPUT ;
    USE SIGNAL ;
    PORT
      LAYER M4 ;
        RECT  21.462 34.56 21.546 34.584 ;
    END
  END q[231]
  PIN q[232]
    DIRECTION OUTPUT ;
    USE SIGNAL ;
    PORT
      LAYER M4 ;
        RECT  21.462 34.704 21.546 34.728 ;
    END
  END q[232]
  PIN q[233]
    DIRECTION OUTPUT ;
    USE SIGNAL ;
    PORT
      LAYER M4 ;
        RECT  21.462 34.8 21.546 34.824 ;
    END
  END q[233]
  PIN q[234]
    DIRECTION OUTPUT ;
    USE SIGNAL ;
    PORT
      LAYER M4 ;
        RECT  21.462 34.944 21.546 34.968 ;
    END
  END q[234]
  PIN q[235]
    DIRECTION OUTPUT ;
    USE SIGNAL ;
    PORT
      LAYER M4 ;
        RECT  21.462 35.088 21.546 35.112 ;
    END
  END q[235]
  PIN q[236]
    DIRECTION OUTPUT ;
    USE SIGNAL ;
    PORT
      LAYER M4 ;
        RECT  21.462 35.184 21.546 35.208 ;
    END
  END q[236]
  PIN q[237]
    DIRECTION OUTPUT ;
    USE SIGNAL ;
    PORT
      LAYER M4 ;
        RECT  21.462 35.328 21.546 35.352 ;
    END
  END q[237]
  PIN q[238]
    DIRECTION OUTPUT ;
    USE SIGNAL ;
    PORT
      LAYER M4 ;
        RECT  21.462 35.472 21.546 35.496 ;
    END
  END q[238]
  PIN q[239]
    DIRECTION OUTPUT ;
    USE SIGNAL ;
    PORT
      LAYER M4 ;
        RECT  21.462 35.568 21.546 35.592 ;
    END
  END q[239]
  PIN q[23]
    DIRECTION OUTPUT ;
    USE SIGNAL ;
    PORT
      LAYER M4 ;
        RECT  21.462 8.304 21.546 8.328 ;
    END
  END q[23]
  PIN q[240]
    DIRECTION OUTPUT ;
    USE SIGNAL ;
    PORT
      LAYER M4 ;
        RECT  21.462 35.712 21.546 35.736 ;
    END
  END q[240]
  PIN q[241]
    DIRECTION OUTPUT ;
    USE SIGNAL ;
    PORT
      LAYER M4 ;
        RECT  21.462 35.808 21.546 35.832 ;
    END
  END q[241]
  PIN q[242]
    DIRECTION OUTPUT ;
    USE SIGNAL ;
    PORT
      LAYER M4 ;
        RECT  21.462 35.952 21.546 35.976 ;
    END
  END q[242]
  PIN q[243]
    DIRECTION OUTPUT ;
    USE SIGNAL ;
    PORT
      LAYER M4 ;
        RECT  21.462 36.096 21.546 36.12 ;
    END
  END q[243]
  PIN q[244]
    DIRECTION OUTPUT ;
    USE SIGNAL ;
    PORT
      LAYER M4 ;
        RECT  21.462 36.192 21.546 36.216 ;
    END
  END q[244]
  PIN q[245]
    DIRECTION OUTPUT ;
    USE SIGNAL ;
    PORT
      LAYER M4 ;
        RECT  21.462 36.336 21.546 36.36 ;
    END
  END q[245]
  PIN q[246]
    DIRECTION OUTPUT ;
    USE SIGNAL ;
    PORT
      LAYER M4 ;
        RECT  21.462 36.48 21.546 36.504 ;
    END
  END q[246]
  PIN q[247]
    DIRECTION OUTPUT ;
    USE SIGNAL ;
    PORT
      LAYER M4 ;
        RECT  21.462 36.576 21.546 36.6 ;
    END
  END q[247]
  PIN q[248]
    DIRECTION OUTPUT ;
    USE SIGNAL ;
    PORT
      LAYER M4 ;
        RECT  21.462 36.72 21.546 36.744 ;
    END
  END q[248]
  PIN q[249]
    DIRECTION OUTPUT ;
    USE SIGNAL ;
    PORT
      LAYER M4 ;
        RECT  21.462 36.864 21.546 36.888 ;
    END
  END q[249]
  PIN q[24]
    DIRECTION OUTPUT ;
    USE SIGNAL ;
    PORT
      LAYER M4 ;
        RECT  21.462 8.4 21.546 8.424 ;
    END
  END q[24]
  PIN q[250]
    DIRECTION OUTPUT ;
    USE SIGNAL ;
    PORT
      LAYER M4 ;
        RECT  21.462 36.96 21.546 36.984 ;
    END
  END q[250]
  PIN q[251]
    DIRECTION OUTPUT ;
    USE SIGNAL ;
    PORT
      LAYER M4 ;
        RECT  21.462 37.104 21.546 37.128 ;
    END
  END q[251]
  PIN q[252]
    DIRECTION OUTPUT ;
    USE SIGNAL ;
    PORT
      LAYER M4 ;
        RECT  21.462 37.2 21.546 37.224 ;
    END
  END q[252]
  PIN q[253]
    DIRECTION OUTPUT ;
    USE SIGNAL ;
    PORT
      LAYER M4 ;
        RECT  21.462 37.344 21.546 37.368 ;
    END
  END q[253]
  PIN q[254]
    DIRECTION OUTPUT ;
    USE SIGNAL ;
    PORT
      LAYER M4 ;
        RECT  21.462 37.488 21.546 37.512 ;
    END
  END q[254]
  PIN q[255]
    DIRECTION OUTPUT ;
    USE SIGNAL ;
    PORT
      LAYER M4 ;
        RECT  21.462 37.584 21.546 37.608 ;
    END
  END q[255]
  PIN q[256]
    DIRECTION OUTPUT ;
    USE SIGNAL ;
    PORT
      LAYER M4 ;
        RECT  21.462 37.728 21.546 37.752 ;
    END
  END q[256]
  PIN q[257]
    DIRECTION OUTPUT ;
    USE SIGNAL ;
    PORT
      LAYER M4 ;
        RECT  21.462 37.872 21.546 37.896 ;
    END
  END q[257]
  PIN q[258]
    DIRECTION OUTPUT ;
    USE SIGNAL ;
    PORT
      LAYER M4 ;
        RECT  21.462 37.968 21.546 37.992 ;
    END
  END q[258]
  PIN q[259]
    DIRECTION OUTPUT ;
    USE SIGNAL ;
    PORT
      LAYER M4 ;
        RECT  21.462 38.112 21.546 38.136 ;
    END
  END q[259]
  PIN q[25]
    DIRECTION OUTPUT ;
    USE SIGNAL ;
    PORT
      LAYER M4 ;
        RECT  21.462 8.544 21.546 8.568 ;
    END
  END q[25]
  PIN q[260]
    DIRECTION OUTPUT ;
    USE SIGNAL ;
    PORT
      LAYER M4 ;
        RECT  21.462 38.208 21.546 38.232 ;
    END
  END q[260]
  PIN q[261]
    DIRECTION OUTPUT ;
    USE SIGNAL ;
    PORT
      LAYER M4 ;
        RECT  21.462 38.352 21.546 38.376 ;
    END
  END q[261]
  PIN q[262]
    DIRECTION OUTPUT ;
    USE SIGNAL ;
    PORT
      LAYER M4 ;
        RECT  21.462 38.496 21.546 38.52 ;
    END
  END q[262]
  PIN q[263]
    DIRECTION OUTPUT ;
    USE SIGNAL ;
    PORT
      LAYER M4 ;
        RECT  21.462 38.592 21.546 38.616 ;
    END
  END q[263]
  PIN q[264]
    DIRECTION OUTPUT ;
    USE SIGNAL ;
    PORT
      LAYER M4 ;
        RECT  21.462 38.736 21.546 38.76 ;
    END
  END q[264]
  PIN q[265]
    DIRECTION OUTPUT ;
    USE SIGNAL ;
    PORT
      LAYER M4 ;
        RECT  21.462 38.88 21.546 38.904 ;
    END
  END q[265]
  PIN q[266]
    DIRECTION OUTPUT ;
    USE SIGNAL ;
    PORT
      LAYER M4 ;
        RECT  21.462 38.976 21.546 39 ;
    END
    PORT
      LAYER M4 ;
        RECT  21.516 38.976 21.593 39 ;
    END
  END q[266]
  PIN q[267]
    DIRECTION OUTPUT ;
    USE SIGNAL ;
    PORT
      LAYER M4 ;
        RECT  21.462 39.12 21.546 39.144 ;
    END
  END q[267]
  PIN q[268]
    DIRECTION OUTPUT ;
    USE SIGNAL ;
    PORT
      LAYER M4 ;
        RECT  21.462 39.264 21.546 39.288 ;
    END
  END q[268]
  PIN q[269]
    DIRECTION OUTPUT ;
    USE SIGNAL ;
    PORT
      LAYER M4 ;
        RECT  21.462 39.36 21.546 39.384 ;
    END
  END q[269]
  PIN q[26]
    DIRECTION OUTPUT ;
    USE SIGNAL ;
    PORT
      LAYER M4 ;
        RECT  21.462 8.688 21.546 8.712 ;
    END
  END q[26]
  PIN q[270]
    DIRECTION OUTPUT ;
    USE SIGNAL ;
    PORT
      LAYER M4 ;
        RECT  21.462 39.504 21.546 39.528 ;
    END
  END q[270]
  PIN q[271]
    DIRECTION OUTPUT ;
    USE SIGNAL ;
    PORT
      LAYER M4 ;
        RECT  21.462 39.6 21.546 39.624 ;
    END
  END q[271]
  PIN q[272]
    DIRECTION OUTPUT ;
    USE SIGNAL ;
    PORT
      LAYER M4 ;
        RECT  21.462 39.744 21.546 39.768 ;
    END
  END q[272]
  PIN q[273]
    DIRECTION OUTPUT ;
    USE SIGNAL ;
    PORT
      LAYER M4 ;
        RECT  21.462 39.888 21.546 39.912 ;
    END
  END q[273]
  PIN q[274]
    DIRECTION OUTPUT ;
    USE SIGNAL ;
    PORT
      LAYER M4 ;
        RECT  21.462 39.984 21.546 40.008 ;
    END
  END q[274]
  PIN q[275]
    DIRECTION OUTPUT ;
    USE SIGNAL ;
    PORT
      LAYER M4 ;
        RECT  21.462 40.128 21.546 40.152 ;
    END
  END q[275]
  PIN q[276]
    DIRECTION OUTPUT ;
    USE SIGNAL ;
    PORT
      LAYER M4 ;
        RECT  21.462 40.272 21.546 40.296 ;
    END
  END q[276]
  PIN q[277]
    DIRECTION OUTPUT ;
    USE SIGNAL ;
    PORT
      LAYER M4 ;
        RECT  21.462 40.368 21.546 40.392 ;
    END
  END q[277]
  PIN q[278]
    DIRECTION OUTPUT ;
    USE SIGNAL ;
    PORT
      LAYER M4 ;
        RECT  21.462 40.512 21.546 40.536 ;
    END
  END q[278]
  PIN q[279]
    DIRECTION OUTPUT ;
    USE SIGNAL ;
    PORT
      LAYER M4 ;
        RECT  21.462 40.608 21.546 40.632 ;
    END
  END q[279]
  PIN q[27]
    DIRECTION OUTPUT ;
    USE SIGNAL ;
    PORT
      LAYER M4 ;
        RECT  21.462 8.784 21.546 8.808 ;
    END
  END q[27]
  PIN q[280]
    DIRECTION OUTPUT ;
    USE SIGNAL ;
    PORT
      LAYER M4 ;
        RECT  21.462 40.752 21.546 40.776 ;
    END
  END q[280]
  PIN q[281]
    DIRECTION OUTPUT ;
    USE SIGNAL ;
    PORT
      LAYER M4 ;
        RECT  21.462 40.896 21.546 40.92 ;
    END
  END q[281]
  PIN q[282]
    DIRECTION OUTPUT ;
    USE SIGNAL ;
    PORT
      LAYER M4 ;
        RECT  21.462 40.992 21.546 41.016 ;
    END
  END q[282]
  PIN q[283]
    DIRECTION OUTPUT ;
    USE SIGNAL ;
    PORT
      LAYER M4 ;
        RECT  21.462 41.136 21.546 41.16 ;
    END
  END q[283]
  PIN q[284]
    DIRECTION OUTPUT ;
    USE SIGNAL ;
    PORT
      LAYER M4 ;
        RECT  21.462 41.28 21.546 41.304 ;
    END
  END q[284]
  PIN q[285]
    DIRECTION OUTPUT ;
    USE SIGNAL ;
    PORT
      LAYER M4 ;
        RECT  21.462 41.376 21.546 41.4 ;
    END
  END q[285]
  PIN q[286]
    DIRECTION OUTPUT ;
    USE SIGNAL ;
    PORT
      LAYER M4 ;
        RECT  21.462 41.52 21.546 41.544 ;
    END
  END q[286]
  PIN q[287]
    DIRECTION OUTPUT ;
    USE SIGNAL ;
    PORT
      LAYER M4 ;
        RECT  21.462 41.664 21.546 41.688 ;
    END
  END q[287]
  PIN q[288]
    DIRECTION OUTPUT ;
    USE SIGNAL ;
    PORT
      LAYER M4 ;
        RECT  21.462 41.76 21.546 41.784 ;
    END
  END q[288]
  PIN q[289]
    DIRECTION OUTPUT ;
    USE SIGNAL ;
    PORT
      LAYER M4 ;
        RECT  21.462 41.904 21.546 41.928 ;
    END
  END q[289]
  PIN q[28]
    DIRECTION OUTPUT ;
    USE SIGNAL ;
    PORT
      LAYER M4 ;
        RECT  21.462 8.928 21.546 8.952 ;
    END
  END q[28]
  PIN q[290]
    DIRECTION OUTPUT ;
    USE SIGNAL ;
    PORT
      LAYER M4 ;
        RECT  21.462 42 21.546 42.024 ;
    END
  END q[290]
  PIN q[291]
    DIRECTION OUTPUT ;
    USE SIGNAL ;
    PORT
      LAYER M4 ;
        RECT  21.462 42.144 21.546 42.168 ;
    END
  END q[291]
  PIN q[292]
    DIRECTION OUTPUT ;
    USE SIGNAL ;
    PORT
      LAYER M4 ;
        RECT  21.462 42.288 21.546 42.312 ;
    END
  END q[292]
  PIN q[293]
    DIRECTION OUTPUT ;
    USE SIGNAL ;
    PORT
      LAYER M4 ;
        RECT  21.462 42.384 21.546 42.408 ;
    END
  END q[293]
  PIN q[294]
    DIRECTION OUTPUT ;
    USE SIGNAL ;
    PORT
      LAYER M4 ;
        RECT  21.462 42.528 21.546 42.552 ;
    END
  END q[294]
  PIN q[295]
    DIRECTION OUTPUT ;
    USE SIGNAL ;
    PORT
      LAYER M4 ;
        RECT  21.462 42.672 21.546 42.696 ;
    END
  END q[295]
  PIN q[296]
    DIRECTION OUTPUT ;
    USE SIGNAL ;
    PORT
      LAYER M4 ;
        RECT  21.462 42.768 21.546 42.792 ;
    END
  END q[296]
  PIN q[297]
    DIRECTION OUTPUT ;
    USE SIGNAL ;
    PORT
      LAYER M4 ;
        RECT  21.462 42.912 21.546 42.936 ;
    END
  END q[297]
  PIN q[298]
    DIRECTION OUTPUT ;
    USE SIGNAL ;
    PORT
      LAYER M4 ;
        RECT  21.462 43.008 21.546 43.032 ;
    END
  END q[298]
  PIN q[299]
    DIRECTION OUTPUT ;
    USE SIGNAL ;
    PORT
      LAYER M4 ;
        RECT  21.462 43.152 21.546 43.176 ;
    END
  END q[299]
  PIN q[29]
    DIRECTION OUTPUT ;
    USE SIGNAL ;
    PORT
      LAYER M4 ;
        RECT  21.462 9.072 21.546 9.096 ;
    END
  END q[29]
  PIN q[2]
    DIRECTION OUTPUT ;
    USE SIGNAL ;
    PORT
      LAYER M4 ;
        RECT  21.462 5.664 21.546 5.688 ;
    END
  END q[2]
  PIN q[300]
    DIRECTION OUTPUT ;
    USE SIGNAL ;
    PORT
      LAYER M4 ;
        RECT  21.462 43.296 21.546 43.32 ;
    END
  END q[300]
  PIN q[301]
    DIRECTION OUTPUT ;
    USE SIGNAL ;
    PORT
      LAYER M4 ;
        RECT  21.462 43.392 21.546 43.416 ;
    END
  END q[301]
  PIN q[302]
    DIRECTION OUTPUT ;
    USE SIGNAL ;
    PORT
      LAYER M4 ;
        RECT  21.462 43.536 21.546 43.56 ;
    END
  END q[302]
  PIN q[303]
    DIRECTION OUTPUT ;
    USE SIGNAL ;
    PORT
      LAYER M4 ;
        RECT  21.462 43.68 21.546 43.704 ;
    END
  END q[303]
  PIN q[304]
    DIRECTION OUTPUT ;
    USE SIGNAL ;
    PORT
      LAYER M4 ;
        RECT  21.462 43.776 21.546 43.8 ;
    END
  END q[304]
  PIN q[305]
    DIRECTION OUTPUT ;
    USE SIGNAL ;
    PORT
      LAYER M4 ;
        RECT  21.462 43.92 21.546 43.944 ;
    END
  END q[305]
  PIN q[306]
    DIRECTION OUTPUT ;
    USE SIGNAL ;
    PORT
      LAYER M4 ;
        RECT  21.462 44.064 21.546 44.088 ;
    END
  END q[306]
  PIN q[307]
    DIRECTION OUTPUT ;
    USE SIGNAL ;
    PORT
      LAYER M4 ;
        RECT  21.462 44.16 21.546 44.184 ;
    END
  END q[307]
  PIN q[308]
    DIRECTION OUTPUT ;
    USE SIGNAL ;
    PORT
      LAYER M4 ;
        RECT  21.462 44.304 21.546 44.328 ;
    END
  END q[308]
  PIN q[309]
    DIRECTION OUTPUT ;
    USE SIGNAL ;
    PORT
      LAYER M4 ;
        RECT  21.462 44.4 21.546 44.424 ;
    END
  END q[309]
  PIN q[30]
    DIRECTION OUTPUT ;
    USE SIGNAL ;
    PORT
      LAYER M4 ;
        RECT  21.462 9.168 21.546 9.192 ;
    END
  END q[30]
  PIN q[310]
    DIRECTION OUTPUT ;
    USE SIGNAL ;
    PORT
      LAYER M4 ;
        RECT  21.462 44.544 21.546 44.568 ;
    END
  END q[310]
  PIN q[311]
    DIRECTION OUTPUT ;
    USE SIGNAL ;
    PORT
      LAYER M4 ;
        RECT  21.462 44.688 21.546 44.712 ;
    END
  END q[311]
  PIN q[312]
    DIRECTION OUTPUT ;
    USE SIGNAL ;
    PORT
      LAYER M4 ;
        RECT  21.462 44.784 21.546 44.808 ;
    END
  END q[312]
  PIN q[313]
    DIRECTION OUTPUT ;
    USE SIGNAL ;
    PORT
      LAYER M4 ;
        RECT  21.462 44.928 21.546 44.952 ;
    END
  END q[313]
  PIN q[314]
    DIRECTION OUTPUT ;
    USE SIGNAL ;
    PORT
      LAYER M4 ;
        RECT  21.462 45.072 21.546 45.096 ;
    END
  END q[314]
  PIN q[315]
    DIRECTION OUTPUT ;
    USE SIGNAL ;
    PORT
      LAYER M4 ;
        RECT  21.462 45.168 21.546 45.192 ;
    END
  END q[315]
  PIN q[316]
    DIRECTION OUTPUT ;
    USE SIGNAL ;
    PORT
      LAYER M4 ;
        RECT  21.462 45.312 21.546 45.336 ;
    END
  END q[316]
  PIN q[317]
    DIRECTION OUTPUT ;
    USE SIGNAL ;
    PORT
      LAYER M4 ;
        RECT  21.462 45.408 21.546 45.432 ;
    END
  END q[317]
  PIN q[318]
    DIRECTION OUTPUT ;
    USE SIGNAL ;
    PORT
      LAYER M4 ;
        RECT  21.462 45.552 21.546 45.576 ;
    END
  END q[318]
  PIN q[319]
    DIRECTION OUTPUT ;
    USE SIGNAL ;
    PORT
      LAYER M4 ;
        RECT  21.462 45.696 21.546 45.72 ;
    END
  END q[319]
  PIN q[31]
    DIRECTION OUTPUT ;
    USE SIGNAL ;
    PORT
      LAYER M4 ;
        RECT  21.462 9.312 21.546 9.336 ;
    END
  END q[31]
  PIN q[320]
    DIRECTION OUTPUT ;
    USE SIGNAL ;
    PORT
      LAYER M4 ;
        RECT  21.462 45.792 21.546 45.816 ;
    END
  END q[320]
  PIN q[321]
    DIRECTION OUTPUT ;
    USE SIGNAL ;
    PORT
      LAYER M4 ;
        RECT  21.462 45.936 21.546 45.96 ;
    END
  END q[321]
  PIN q[322]
    DIRECTION OUTPUT ;
    USE SIGNAL ;
    PORT
      LAYER M4 ;
        RECT  21.462 46.08 21.546 46.104 ;
    END
  END q[322]
  PIN q[323]
    DIRECTION OUTPUT ;
    USE SIGNAL ;
    PORT
      LAYER M4 ;
        RECT  21.462 46.176 21.546 46.2 ;
    END
  END q[323]
  PIN q[324]
    DIRECTION OUTPUT ;
    USE SIGNAL ;
    PORT
      LAYER M4 ;
        RECT  21.462 46.32 21.546 46.344 ;
    END
  END q[324]
  PIN q[325]
    DIRECTION OUTPUT ;
    USE SIGNAL ;
    PORT
      LAYER M4 ;
        RECT  21.462 46.464 21.546 46.488 ;
    END
  END q[325]
  PIN q[326]
    DIRECTION OUTPUT ;
    USE SIGNAL ;
    PORT
      LAYER M4 ;
        RECT  21.462 46.56 21.546 46.584 ;
    END
  END q[326]
  PIN q[327]
    DIRECTION OUTPUT ;
    USE SIGNAL ;
    PORT
      LAYER M4 ;
        RECT  21.462 46.704 21.546 46.728 ;
    END
  END q[327]
  PIN q[328]
    DIRECTION OUTPUT ;
    USE SIGNAL ;
    PORT
      LAYER M4 ;
        RECT  21.462 46.8 21.546 46.824 ;
    END
  END q[328]
  PIN q[329]
    DIRECTION OUTPUT ;
    USE SIGNAL ;
    PORT
      LAYER M4 ;
        RECT  21.462 46.944 21.546 46.968 ;
    END
  END q[329]
  PIN q[32]
    DIRECTION OUTPUT ;
    USE SIGNAL ;
    PORT
      LAYER M4 ;
        RECT  21.462 9.408 21.546 9.432 ;
    END
  END q[32]
  PIN q[330]
    DIRECTION OUTPUT ;
    USE SIGNAL ;
    PORT
      LAYER M4 ;
        RECT  21.462 47.088 21.546 47.112 ;
    END
  END q[330]
  PIN q[331]
    DIRECTION OUTPUT ;
    USE SIGNAL ;
    PORT
      LAYER M4 ;
        RECT  21.462 47.184 21.546 47.208 ;
    END
  END q[331]
  PIN q[332]
    DIRECTION OUTPUT ;
    USE SIGNAL ;
    PORT
      LAYER M4 ;
        RECT  21.462 47.328 21.546 47.352 ;
    END
  END q[332]
  PIN q[333]
    DIRECTION OUTPUT ;
    USE SIGNAL ;
    PORT
      LAYER M4 ;
        RECT  21.462 47.472 21.546 47.496 ;
    END
  END q[333]
  PIN q[334]
    DIRECTION OUTPUT ;
    USE SIGNAL ;
    PORT
      LAYER M4 ;
        RECT  21.462 47.568 21.546 47.592 ;
    END
  END q[334]
  PIN q[335]
    DIRECTION OUTPUT ;
    USE SIGNAL ;
    PORT
      LAYER M4 ;
        RECT  21.462 47.712 21.546 47.736 ;
    END
  END q[335]
  PIN q[336]
    DIRECTION OUTPUT ;
    USE SIGNAL ;
    PORT
      LAYER M4 ;
        RECT  21.462 47.808 21.546 47.832 ;
    END
  END q[336]
  PIN q[337]
    DIRECTION OUTPUT ;
    USE SIGNAL ;
    PORT
      LAYER M4 ;
        RECT  21.462 47.952 21.546 47.976 ;
    END
  END q[337]
  PIN q[338]
    DIRECTION OUTPUT ;
    USE SIGNAL ;
    PORT
      LAYER M4 ;
        RECT  21.462 48.096 21.546 48.12 ;
    END
  END q[338]
  PIN q[339]
    DIRECTION OUTPUT ;
    USE SIGNAL ;
    PORT
      LAYER M4 ;
        RECT  21.462 48.192 21.546 48.216 ;
    END
  END q[339]
  PIN q[33]
    DIRECTION OUTPUT ;
    USE SIGNAL ;
    PORT
      LAYER M4 ;
        RECT  21.462 9.552 21.546 9.576 ;
    END
  END q[33]
  PIN q[340]
    DIRECTION OUTPUT ;
    USE SIGNAL ;
    PORT
      LAYER M4 ;
        RECT  21.462 48.336 21.546 48.36 ;
    END
  END q[340]
  PIN q[341]
    DIRECTION OUTPUT ;
    USE SIGNAL ;
    PORT
      LAYER M4 ;
        RECT  21.462 48.48 21.546 48.504 ;
    END
  END q[341]
  PIN q[342]
    DIRECTION OUTPUT ;
    USE SIGNAL ;
    PORT
      LAYER M4 ;
        RECT  21.462 48.576 21.546 48.6 ;
    END
  END q[342]
  PIN q[343]
    DIRECTION OUTPUT ;
    USE SIGNAL ;
    PORT
      LAYER M4 ;
        RECT  21.462 48.72 21.546 48.744 ;
    END
  END q[343]
  PIN q[344]
    DIRECTION OUTPUT ;
    USE SIGNAL ;
    PORT
      LAYER M4 ;
        RECT  21.462 48.864 21.546 48.888 ;
    END
  END q[344]
  PIN q[345]
    DIRECTION OUTPUT ;
    USE SIGNAL ;
    PORT
      LAYER M4 ;
        RECT  21.462 48.96 21.546 48.984 ;
    END
  END q[345]
  PIN q[346]
    DIRECTION OUTPUT ;
    USE SIGNAL ;
    PORT
      LAYER M4 ;
        RECT  21.462 49.104 21.546 49.128 ;
    END
  END q[346]
  PIN q[347]
    DIRECTION OUTPUT ;
    USE SIGNAL ;
    PORT
      LAYER M4 ;
        RECT  21.462 49.2 21.546 49.224 ;
    END
  END q[347]
  PIN q[348]
    DIRECTION OUTPUT ;
    USE SIGNAL ;
    PORT
      LAYER M4 ;
        RECT  21.462 49.344 21.546 49.368 ;
    END
  END q[348]
  PIN q[349]
    DIRECTION OUTPUT ;
    USE SIGNAL ;
    PORT
      LAYER M4 ;
        RECT  21.462 49.488 21.546 49.512 ;
    END
  END q[349]
  PIN q[34]
    DIRECTION OUTPUT ;
    USE SIGNAL ;
    PORT
      LAYER M4 ;
        RECT  21.462 9.696 21.546 9.72 ;
    END
  END q[34]
  PIN q[350]
    DIRECTION OUTPUT ;
    USE SIGNAL ;
    PORT
      LAYER M4 ;
        RECT  21.462 49.584 21.546 49.608 ;
    END
  END q[350]
  PIN q[351]
    DIRECTION OUTPUT ;
    USE SIGNAL ;
    PORT
      LAYER M4 ;
        RECT  21.462 49.728 21.546 49.752 ;
    END
  END q[351]
  PIN q[352]
    DIRECTION OUTPUT ;
    USE SIGNAL ;
    PORT
      LAYER M4 ;
        RECT  21.462 49.872 21.546 49.896 ;
    END
  END q[352]
  PIN q[353]
    DIRECTION OUTPUT ;
    USE SIGNAL ;
    PORT
      LAYER M4 ;
        RECT  21.462 49.968 21.546 49.992 ;
    END
  END q[353]
  PIN q[354]
    DIRECTION OUTPUT ;
    USE SIGNAL ;
    PORT
      LAYER M4 ;
        RECT  21.462 50.112 21.546 50.136 ;
    END
  END q[354]
  PIN q[355]
    DIRECTION OUTPUT ;
    USE SIGNAL ;
    PORT
      LAYER M4 ;
        RECT  21.462 50.208 21.546 50.232 ;
    END
  END q[355]
  PIN q[356]
    DIRECTION OUTPUT ;
    USE SIGNAL ;
    PORT
      LAYER M4 ;
        RECT  21.462 50.352 21.546 50.376 ;
    END
  END q[356]
  PIN q[357]
    DIRECTION OUTPUT ;
    USE SIGNAL ;
    PORT
      LAYER M4 ;
        RECT  21.462 50.496 21.546 50.52 ;
    END
  END q[357]
  PIN q[358]
    DIRECTION OUTPUT ;
    USE SIGNAL ;
    PORT
      LAYER M4 ;
        RECT  21.462 50.592 21.546 50.616 ;
    END
  END q[358]
  PIN q[359]
    DIRECTION OUTPUT ;
    USE SIGNAL ;
    PORT
      LAYER M4 ;
        RECT  21.462 50.736 21.546 50.76 ;
    END
  END q[359]
  PIN q[35]
    DIRECTION OUTPUT ;
    USE SIGNAL ;
    PORT
      LAYER M4 ;
        RECT  21.462 9.792 21.546 9.816 ;
    END
  END q[35]
  PIN q[360]
    DIRECTION OUTPUT ;
    USE SIGNAL ;
    PORT
      LAYER M4 ;
        RECT  21.462 50.88 21.546 50.904 ;
    END
  END q[360]
  PIN q[361]
    DIRECTION OUTPUT ;
    USE SIGNAL ;
    PORT
      LAYER M4 ;
        RECT  21.462 50.976 21.546 51 ;
    END
  END q[361]
  PIN q[362]
    DIRECTION OUTPUT ;
    USE SIGNAL ;
    PORT
      LAYER M4 ;
        RECT  21.462 51.12 21.546 51.144 ;
    END
  END q[362]
  PIN q[363]
    DIRECTION OUTPUT ;
    USE SIGNAL ;
    PORT
      LAYER M4 ;
        RECT  21.462 51.264 21.546 51.288 ;
    END
  END q[363]
  PIN q[364]
    DIRECTION OUTPUT ;
    USE SIGNAL ;
    PORT
      LAYER M4 ;
        RECT  21.462 51.36 21.546 51.384 ;
    END
  END q[364]
  PIN q[365]
    DIRECTION OUTPUT ;
    USE SIGNAL ;
    PORT
      LAYER M4 ;
        RECT  21.462 51.504 21.546 51.528 ;
    END
  END q[365]
  PIN q[366]
    DIRECTION OUTPUT ;
    USE SIGNAL ;
    PORT
      LAYER M4 ;
        RECT  21.462 51.6 21.546 51.624 ;
    END
  END q[366]
  PIN q[367]
    DIRECTION OUTPUT ;
    USE SIGNAL ;
    PORT
      LAYER M4 ;
        RECT  21.462 51.744 21.546 51.768 ;
    END
  END q[367]
  PIN q[368]
    DIRECTION OUTPUT ;
    USE SIGNAL ;
    PORT
      LAYER M4 ;
        RECT  21.462 51.888 21.546 51.912 ;
    END
  END q[368]
  PIN q[369]
    DIRECTION OUTPUT ;
    USE SIGNAL ;
    PORT
      LAYER M4 ;
        RECT  21.462 51.984 21.546 52.008 ;
    END
  END q[369]
  PIN q[36]
    DIRECTION OUTPUT ;
    USE SIGNAL ;
    PORT
      LAYER M4 ;
        RECT  21.462 9.936 21.546 9.96 ;
    END
  END q[36]
  PIN q[370]
    DIRECTION OUTPUT ;
    USE SIGNAL ;
    PORT
      LAYER M4 ;
        RECT  21.462 52.128 21.546 52.152 ;
    END
  END q[370]
  PIN q[371]
    DIRECTION OUTPUT ;
    USE SIGNAL ;
    PORT
      LAYER M4 ;
        RECT  21.462 52.272 21.546 52.296 ;
    END
  END q[371]
  PIN q[372]
    DIRECTION OUTPUT ;
    USE SIGNAL ;
    PORT
      LAYER M4 ;
        RECT  21.462 52.368 21.546 52.392 ;
    END
  END q[372]
  PIN q[373]
    DIRECTION OUTPUT ;
    USE SIGNAL ;
    PORT
      LAYER M4 ;
        RECT  21.462 52.512 21.546 52.536 ;
    END
  END q[373]
  PIN q[374]
    DIRECTION OUTPUT ;
    USE SIGNAL ;
    PORT
      LAYER M4 ;
        RECT  21.462 52.608 21.546 52.632 ;
    END
  END q[374]
  PIN q[375]
    DIRECTION OUTPUT ;
    USE SIGNAL ;
    PORT
      LAYER M4 ;
        RECT  21.462 52.752 21.546 52.776 ;
    END
  END q[375]
  PIN q[376]
    DIRECTION OUTPUT ;
    USE SIGNAL ;
    PORT
      LAYER M4 ;
        RECT  21.462 52.896 21.546 52.92 ;
    END
  END q[376]
  PIN q[377]
    DIRECTION OUTPUT ;
    USE SIGNAL ;
    PORT
      LAYER M4 ;
        RECT  21.462 52.992 21.546 53.016 ;
    END
  END q[377]
  PIN q[378]
    DIRECTION OUTPUT ;
    USE SIGNAL ;
    PORT
      LAYER M4 ;
        RECT  21.462 53.136 21.546 53.16 ;
    END
  END q[378]
  PIN q[379]
    DIRECTION OUTPUT ;
    USE SIGNAL ;
    PORT
      LAYER M4 ;
        RECT  21.462 53.28 21.546 53.304 ;
    END
  END q[379]
  PIN q[37]
    DIRECTION OUTPUT ;
    USE SIGNAL ;
    PORT
      LAYER M4 ;
        RECT  21.462 10.08 21.546 10.104 ;
    END
  END q[37]
  PIN q[380]
    DIRECTION OUTPUT ;
    USE SIGNAL ;
    PORT
      LAYER M4 ;
        RECT  21.462 53.376 21.546 53.4 ;
    END
  END q[380]
  PIN q[381]
    DIRECTION OUTPUT ;
    USE SIGNAL ;
    PORT
      LAYER M4 ;
        RECT  21.462 53.52 21.546 53.544 ;
    END
  END q[381]
  PIN q[382]
    DIRECTION OUTPUT ;
    USE SIGNAL ;
    PORT
      LAYER M4 ;
        RECT  21.462 53.664 21.546 53.688 ;
    END
  END q[382]
  PIN q[383]
    DIRECTION OUTPUT ;
    USE SIGNAL ;
    PORT
      LAYER M4 ;
        RECT  21.462 53.76 21.546 53.784 ;
    END
  END q[383]
  PIN q[384]
    DIRECTION OUTPUT ;
    USE SIGNAL ;
    PORT
      LAYER M4 ;
        RECT  21.462 53.904 21.546 53.928 ;
    END
  END q[384]
  PIN q[385]
    DIRECTION OUTPUT ;
    USE SIGNAL ;
    PORT
      LAYER M4 ;
        RECT  21.462 54 21.546 54.024 ;
    END
  END q[385]
  PIN q[386]
    DIRECTION OUTPUT ;
    USE SIGNAL ;
    PORT
      LAYER M4 ;
        RECT  21.462 54.144 21.546 54.168 ;
    END
  END q[386]
  PIN q[387]
    DIRECTION OUTPUT ;
    USE SIGNAL ;
    PORT
      LAYER M4 ;
        RECT  21.462 54.288 21.546 54.312 ;
    END
  END q[387]
  PIN q[388]
    DIRECTION OUTPUT ;
    USE SIGNAL ;
    PORT
      LAYER M4 ;
        RECT  21.462 54.384 21.546 54.408 ;
    END
  END q[388]
  PIN q[389]
    DIRECTION OUTPUT ;
    USE SIGNAL ;
    PORT
      LAYER M4 ;
        RECT  21.462 54.528 21.546 54.552 ;
    END
  END q[389]
  PIN q[38]
    DIRECTION OUTPUT ;
    USE SIGNAL ;
    PORT
      LAYER M4 ;
        RECT  21.462 10.176 21.546 10.2 ;
    END
  END q[38]
  PIN q[390]
    DIRECTION OUTPUT ;
    USE SIGNAL ;
    PORT
      LAYER M4 ;
        RECT  21.462 54.672 21.546 54.696 ;
    END
  END q[390]
  PIN q[391]
    DIRECTION OUTPUT ;
    USE SIGNAL ;
    PORT
      LAYER M4 ;
        RECT  21.462 54.768 21.546 54.792 ;
    END
  END q[391]
  PIN q[392]
    DIRECTION OUTPUT ;
    USE SIGNAL ;
    PORT
      LAYER M4 ;
        RECT  21.462 54.912 21.546 54.936 ;
    END
  END q[392]
  PIN q[393]
    DIRECTION OUTPUT ;
    USE SIGNAL ;
    PORT
      LAYER M4 ;
        RECT  21.462 55.008 21.546 55.032 ;
    END
  END q[393]
  PIN q[394]
    DIRECTION OUTPUT ;
    USE SIGNAL ;
    PORT
      LAYER M4 ;
        RECT  21.462 55.152 21.546 55.176 ;
    END
  END q[394]
  PIN q[395]
    DIRECTION OUTPUT ;
    USE SIGNAL ;
    PORT
      LAYER M4 ;
        RECT  21.462 55.296 21.546 55.32 ;
    END
  END q[395]
  PIN q[396]
    DIRECTION OUTPUT ;
    USE SIGNAL ;
    PORT
      LAYER M4 ;
        RECT  21.462 55.392 21.546 55.416 ;
    END
  END q[396]
  PIN q[397]
    DIRECTION OUTPUT ;
    USE SIGNAL ;
    PORT
      LAYER M4 ;
        RECT  21.462 55.536 21.546 55.56 ;
    END
  END q[397]
  PIN q[398]
    DIRECTION OUTPUT ;
    USE SIGNAL ;
    PORT
      LAYER M4 ;
        RECT  21.462 55.68 21.546 55.704 ;
    END
  END q[398]
  PIN q[399]
    DIRECTION OUTPUT ;
    USE SIGNAL ;
    PORT
      LAYER M4 ;
        RECT  21.462 55.776 21.546 55.8 ;
    END
  END q[399]
  PIN q[39]
    DIRECTION OUTPUT ;
    USE SIGNAL ;
    PORT
      LAYER M4 ;
        RECT  21.462 10.32 21.546 10.344 ;
    END
  END q[39]
  PIN q[3]
    DIRECTION OUTPUT ;
    USE SIGNAL ;
    PORT
      LAYER M4 ;
        RECT  21.462 5.76 21.546 5.784 ;
    END
  END q[3]
  PIN q[400]
    DIRECTION OUTPUT ;
    USE SIGNAL ;
    PORT
      LAYER M4 ;
        RECT  21.462 55.92 21.546 55.944 ;
    END
  END q[400]
  PIN q[401]
    DIRECTION OUTPUT ;
    USE SIGNAL ;
    PORT
      LAYER M4 ;
        RECT  21.462 56.064 21.546 56.088 ;
    END
  END q[401]
  PIN q[402]
    DIRECTION OUTPUT ;
    USE SIGNAL ;
    PORT
      LAYER M4 ;
        RECT  21.462 56.16 21.546 56.184 ;
    END
  END q[402]
  PIN q[403]
    DIRECTION OUTPUT ;
    USE SIGNAL ;
    PORT
      LAYER M4 ;
        RECT  21.462 56.304 21.546 56.328 ;
    END
    PORT
      LAYER M4 ;
        RECT  21.516 56.304 21.593 56.328 ;
    END
  END q[403]
  PIN q[404]
    DIRECTION OUTPUT ;
    USE SIGNAL ;
    PORT
      LAYER M4 ;
        RECT  21.462 56.4 21.546 56.424 ;
    END
  END q[404]
  PIN q[405]
    DIRECTION OUTPUT ;
    USE SIGNAL ;
    PORT
      LAYER M4 ;
        RECT  21.462 56.544 21.546 56.568 ;
    END
  END q[405]
  PIN q[406]
    DIRECTION OUTPUT ;
    USE SIGNAL ;
    PORT
      LAYER M4 ;
        RECT  21.462 56.688 21.546 56.712 ;
    END
  END q[406]
  PIN q[407]
    DIRECTION OUTPUT ;
    USE SIGNAL ;
    PORT
      LAYER M4 ;
        RECT  21.462 56.784 21.546 56.808 ;
    END
  END q[407]
  PIN q[408]
    DIRECTION OUTPUT ;
    USE SIGNAL ;
    PORT
      LAYER M4 ;
        RECT  21.462 56.928 21.546 56.952 ;
    END
  END q[408]
  PIN q[409]
    DIRECTION OUTPUT ;
    USE SIGNAL ;
    PORT
      LAYER M4 ;
        RECT  21.462 57.072 21.546 57.096 ;
    END
  END q[409]
  PIN q[40]
    DIRECTION OUTPUT ;
    USE SIGNAL ;
    PORT
      LAYER M4 ;
        RECT  21.462 10.464 21.546 10.488 ;
    END
  END q[40]
  PIN q[410]
    DIRECTION OUTPUT ;
    USE SIGNAL ;
    PORT
      LAYER M4 ;
        RECT  21.462 57.168 21.546 57.192 ;
    END
  END q[410]
  PIN q[411]
    DIRECTION OUTPUT ;
    USE SIGNAL ;
    PORT
      LAYER M4 ;
        RECT  21.462 57.312 21.546 57.336 ;
    END
  END q[411]
  PIN q[412]
    DIRECTION OUTPUT ;
    USE SIGNAL ;
    PORT
      LAYER M4 ;
        RECT  21.462 57.408 21.546 57.432 ;
    END
    PORT
      LAYER M4 ;
        RECT  21.516 57.408 21.593 57.432 ;
    END
  END q[412]
  PIN q[413]
    DIRECTION OUTPUT ;
    USE SIGNAL ;
    PORT
      LAYER M4 ;
        RECT  21.462 57.552 21.546 57.576 ;
    END
  END q[413]
  PIN q[414]
    DIRECTION OUTPUT ;
    USE SIGNAL ;
    PORT
      LAYER M4 ;
        RECT  21.462 57.696 21.546 57.72 ;
    END
  END q[414]
  PIN q[415]
    DIRECTION OUTPUT ;
    USE SIGNAL ;
    PORT
      LAYER M4 ;
        RECT  21.462 57.792 21.546 57.816 ;
    END
  END q[415]
  PIN q[416]
    DIRECTION OUTPUT ;
    USE SIGNAL ;
    PORT
      LAYER M4 ;
        RECT  21.462 57.936 21.546 57.96 ;
    END
  END q[416]
  PIN q[417]
    DIRECTION OUTPUT ;
    USE SIGNAL ;
    PORT
      LAYER M4 ;
        RECT  21.462 58.08 21.546 58.104 ;
    END
  END q[417]
  PIN q[418]
    DIRECTION OUTPUT ;
    USE SIGNAL ;
    PORT
      LAYER M4 ;
        RECT  21.462 58.176 21.546 58.2 ;
    END
  END q[418]
  PIN q[419]
    DIRECTION OUTPUT ;
    USE SIGNAL ;
    PORT
      LAYER M4 ;
        RECT  21.462 58.32 21.546 58.344 ;
    END
  END q[419]
  PIN q[41]
    DIRECTION OUTPUT ;
    USE SIGNAL ;
    PORT
      LAYER M4 ;
        RECT  21.462 10.56 21.546 10.584 ;
    END
  END q[41]
  PIN q[420]
    DIRECTION OUTPUT ;
    USE SIGNAL ;
    PORT
      LAYER M4 ;
        RECT  21.462 58.464 21.546 58.488 ;
    END
  END q[420]
  PIN q[421]
    DIRECTION OUTPUT ;
    USE SIGNAL ;
    PORT
      LAYER M4 ;
        RECT  21.462 58.56 21.546 58.584 ;
    END
  END q[421]
  PIN q[422]
    DIRECTION OUTPUT ;
    USE SIGNAL ;
    PORT
      LAYER M4 ;
        RECT  21.462 58.704 21.546 58.728 ;
    END
  END q[422]
  PIN q[423]
    DIRECTION OUTPUT ;
    USE SIGNAL ;
    PORT
      LAYER M4 ;
        RECT  21.462 58.8 21.546 58.824 ;
    END
  END q[423]
  PIN q[424]
    DIRECTION OUTPUT ;
    USE SIGNAL ;
    PORT
      LAYER M4 ;
        RECT  21.462 58.944 21.546 58.968 ;
    END
  END q[424]
  PIN q[425]
    DIRECTION OUTPUT ;
    USE SIGNAL ;
    PORT
      LAYER M4 ;
        RECT  21.462 59.088 21.546 59.112 ;
    END
  END q[425]
  PIN q[426]
    DIRECTION OUTPUT ;
    USE SIGNAL ;
    PORT
      LAYER M4 ;
        RECT  21.462 59.184 21.546 59.208 ;
    END
  END q[426]
  PIN q[427]
    DIRECTION OUTPUT ;
    USE SIGNAL ;
    PORT
      LAYER M4 ;
        RECT  21.462 59.328 21.546 59.352 ;
    END
  END q[427]
  PIN q[428]
    DIRECTION OUTPUT ;
    USE SIGNAL ;
    PORT
      LAYER M4 ;
        RECT  21.462 59.472 21.546 59.496 ;
    END
  END q[428]
  PIN q[429]
    DIRECTION OUTPUT ;
    USE SIGNAL ;
    PORT
      LAYER M4 ;
        RECT  21.462 59.568 21.546 59.592 ;
    END
  END q[429]
  PIN q[42]
    DIRECTION OUTPUT ;
    USE SIGNAL ;
    PORT
      LAYER M4 ;
        RECT  21.462 10.704 21.546 10.728 ;
    END
  END q[42]
  PIN q[430]
    DIRECTION OUTPUT ;
    USE SIGNAL ;
    PORT
      LAYER M4 ;
        RECT  21.462 59.712 21.546 59.736 ;
    END
  END q[430]
  PIN q[431]
    DIRECTION OUTPUT ;
    USE SIGNAL ;
    PORT
      LAYER M4 ;
        RECT  21.462 59.808 21.546 59.832 ;
    END
  END q[431]
  PIN q[432]
    DIRECTION OUTPUT ;
    USE SIGNAL ;
    PORT
      LAYER M4 ;
        RECT  21.462 59.952 21.546 59.976 ;
    END
  END q[432]
  PIN q[433]
    DIRECTION OUTPUT ;
    USE SIGNAL ;
    PORT
      LAYER M4 ;
        RECT  21.462 60.096 21.546 60.12 ;
    END
  END q[433]
  PIN q[434]
    DIRECTION OUTPUT ;
    USE SIGNAL ;
    PORT
      LAYER M4 ;
        RECT  21.462 60.192 21.546 60.216 ;
    END
  END q[434]
  PIN q[435]
    DIRECTION OUTPUT ;
    USE SIGNAL ;
    PORT
      LAYER M4 ;
        RECT  21.462 60.336 21.546 60.36 ;
    END
  END q[435]
  PIN q[436]
    DIRECTION OUTPUT ;
    USE SIGNAL ;
    PORT
      LAYER M4 ;
        RECT  21.462 60.48 21.546 60.504 ;
    END
  END q[436]
  PIN q[437]
    DIRECTION OUTPUT ;
    USE SIGNAL ;
    PORT
      LAYER M4 ;
        RECT  21.462 60.576 21.546 60.6 ;
    END
  END q[437]
  PIN q[438]
    DIRECTION OUTPUT ;
    USE SIGNAL ;
    PORT
      LAYER M4 ;
        RECT  21.462 60.72 21.546 60.744 ;
    END
  END q[438]
  PIN q[439]
    DIRECTION OUTPUT ;
    USE SIGNAL ;
    PORT
      LAYER M4 ;
        RECT  21.462 60.864 21.546 60.888 ;
    END
  END q[439]
  PIN q[43]
    DIRECTION OUTPUT ;
    USE SIGNAL ;
    PORT
      LAYER M4 ;
        RECT  21.462 10.8 21.546 10.824 ;
    END
  END q[43]
  PIN q[440]
    DIRECTION OUTPUT ;
    USE SIGNAL ;
    PORT
      LAYER M4 ;
        RECT  21.462 60.96 21.546 60.984 ;
    END
  END q[440]
  PIN q[441]
    DIRECTION OUTPUT ;
    USE SIGNAL ;
    PORT
      LAYER M4 ;
        RECT  21.462 61.104 21.546 61.128 ;
    END
  END q[441]
  PIN q[442]
    DIRECTION OUTPUT ;
    USE SIGNAL ;
    PORT
      LAYER M4 ;
        RECT  21.462 61.2 21.546 61.224 ;
    END
  END q[442]
  PIN q[443]
    DIRECTION OUTPUT ;
    USE SIGNAL ;
    PORT
      LAYER M4 ;
        RECT  21.462 61.344 21.546 61.368 ;
    END
  END q[443]
  PIN q[444]
    DIRECTION OUTPUT ;
    USE SIGNAL ;
    PORT
      LAYER M4 ;
        RECT  21.462 61.488 21.546 61.512 ;
    END
  END q[444]
  PIN q[445]
    DIRECTION OUTPUT ;
    USE SIGNAL ;
    PORT
      LAYER M4 ;
        RECT  21.462 61.584 21.546 61.608 ;
    END
  END q[445]
  PIN q[446]
    DIRECTION OUTPUT ;
    USE SIGNAL ;
    PORT
      LAYER M4 ;
        RECT  21.462 61.728 21.546 61.752 ;
    END
  END q[446]
  PIN q[447]
    DIRECTION OUTPUT ;
    USE SIGNAL ;
    PORT
      LAYER M4 ;
        RECT  21.462 61.872 21.546 61.896 ;
    END
  END q[447]
  PIN q[448]
    DIRECTION OUTPUT ;
    USE SIGNAL ;
    PORT
      LAYER M4 ;
        RECT  21.462 61.968 21.546 61.992 ;
    END
    PORT
      LAYER M4 ;
        RECT  21.516 61.968 21.593 61.992 ;
    END
  END q[448]
  PIN q[449]
    DIRECTION OUTPUT ;
    USE SIGNAL ;
    PORT
      LAYER M4 ;
        RECT  21.462 62.112 21.546 62.136 ;
    END
  END q[449]
  PIN q[44]
    DIRECTION OUTPUT ;
    USE SIGNAL ;
    PORT
      LAYER M4 ;
        RECT  21.462 10.944 21.546 10.968 ;
    END
  END q[44]
  PIN q[450]
    DIRECTION OUTPUT ;
    USE SIGNAL ;
    PORT
      LAYER M4 ;
        RECT  21.462 62.208 21.546 62.232 ;
    END
  END q[450]
  PIN q[451]
    DIRECTION OUTPUT ;
    USE SIGNAL ;
    PORT
      LAYER M4 ;
        RECT  21.462 62.352 21.546 62.376 ;
    END
  END q[451]
  PIN q[452]
    DIRECTION OUTPUT ;
    USE SIGNAL ;
    PORT
      LAYER M4 ;
        RECT  21.462 62.496 21.546 62.52 ;
    END
  END q[452]
  PIN q[453]
    DIRECTION OUTPUT ;
    USE SIGNAL ;
    PORT
      LAYER M4 ;
        RECT  21.462 62.592 21.546 62.616 ;
    END
  END q[453]
  PIN q[454]
    DIRECTION OUTPUT ;
    USE SIGNAL ;
    PORT
      LAYER M4 ;
        RECT  21.462 62.736 21.546 62.76 ;
    END
  END q[454]
  PIN q[455]
    DIRECTION OUTPUT ;
    USE SIGNAL ;
    PORT
      LAYER M4 ;
        RECT  21.462 62.88 21.546 62.904 ;
    END
  END q[455]
  PIN q[456]
    DIRECTION OUTPUT ;
    USE SIGNAL ;
    PORT
      LAYER M4 ;
        RECT  21.462 62.976 21.546 63 ;
    END
  END q[456]
  PIN q[457]
    DIRECTION OUTPUT ;
    USE SIGNAL ;
    PORT
      LAYER M4 ;
        RECT  21.462 63.12 21.546 63.144 ;
    END
  END q[457]
  PIN q[458]
    DIRECTION OUTPUT ;
    USE SIGNAL ;
    PORT
      LAYER M4 ;
        RECT  21.462 63.264 21.546 63.288 ;
    END
  END q[458]
  PIN q[459]
    DIRECTION OUTPUT ;
    USE SIGNAL ;
    PORT
      LAYER M4 ;
        RECT  21.462 63.36 21.546 63.384 ;
    END
  END q[459]
  PIN q[45]
    DIRECTION OUTPUT ;
    USE SIGNAL ;
    PORT
      LAYER M4 ;
        RECT  21.462 11.088 21.546 11.112 ;
    END
  END q[45]
  PIN q[460]
    DIRECTION OUTPUT ;
    USE SIGNAL ;
    PORT
      LAYER M4 ;
        RECT  21.462 63.504 21.546 63.528 ;
    END
  END q[460]
  PIN q[461]
    DIRECTION OUTPUT ;
    USE SIGNAL ;
    PORT
      LAYER M4 ;
        RECT  21.462 63.6 21.546 63.624 ;
    END
  END q[461]
  PIN q[462]
    DIRECTION OUTPUT ;
    USE SIGNAL ;
    PORT
      LAYER M4 ;
        RECT  21.462 63.744 21.546 63.768 ;
    END
  END q[462]
  PIN q[463]
    DIRECTION OUTPUT ;
    USE SIGNAL ;
    PORT
      LAYER M4 ;
        RECT  21.462 63.888 21.546 63.912 ;
    END
  END q[463]
  PIN q[464]
    DIRECTION OUTPUT ;
    USE SIGNAL ;
    PORT
      LAYER M4 ;
        RECT  21.462 63.984 21.546 64.008 ;
    END
  END q[464]
  PIN q[465]
    DIRECTION OUTPUT ;
    USE SIGNAL ;
    PORT
      LAYER M4 ;
        RECT  21.462 64.128 21.546 64.152 ;
    END
  END q[465]
  PIN q[466]
    DIRECTION OUTPUT ;
    USE SIGNAL ;
    PORT
      LAYER M4 ;
        RECT  21.462 64.272 21.546 64.296 ;
    END
  END q[466]
  PIN q[467]
    DIRECTION OUTPUT ;
    USE SIGNAL ;
    PORT
      LAYER M4 ;
        RECT  21.462 64.368 21.546 64.392 ;
    END
  END q[467]
  PIN q[468]
    DIRECTION OUTPUT ;
    USE SIGNAL ;
    PORT
      LAYER M4 ;
        RECT  21.462 64.512 21.546 64.536 ;
    END
  END q[468]
  PIN q[469]
    DIRECTION OUTPUT ;
    USE SIGNAL ;
    PORT
      LAYER M4 ;
        RECT  21.462 64.608 21.546 64.632 ;
    END
  END q[469]
  PIN q[46]
    DIRECTION OUTPUT ;
    USE SIGNAL ;
    PORT
      LAYER M4 ;
        RECT  21.462 11.184 21.546 11.208 ;
    END
  END q[46]
  PIN q[470]
    DIRECTION OUTPUT ;
    USE SIGNAL ;
    PORT
      LAYER M4 ;
        RECT  21.462 64.752 21.546 64.776 ;
    END
  END q[470]
  PIN q[471]
    DIRECTION OUTPUT ;
    USE SIGNAL ;
    PORT
      LAYER M4 ;
        RECT  21.462 64.896 21.546 64.92 ;
    END
  END q[471]
  PIN q[472]
    DIRECTION OUTPUT ;
    USE SIGNAL ;
    PORT
      LAYER M4 ;
        RECT  21.462 64.992 21.546 65.016 ;
    END
  END q[472]
  PIN q[473]
    DIRECTION OUTPUT ;
    USE SIGNAL ;
    PORT
      LAYER M4 ;
        RECT  21.462 65.136 21.546 65.16 ;
    END
  END q[473]
  PIN q[474]
    DIRECTION OUTPUT ;
    USE SIGNAL ;
    PORT
      LAYER M4 ;
        RECT  21.462 65.28 21.546 65.304 ;
    END
  END q[474]
  PIN q[475]
    DIRECTION OUTPUT ;
    USE SIGNAL ;
    PORT
      LAYER M4 ;
        RECT  21.462 65.376 21.546 65.4 ;
    END
  END q[475]
  PIN q[476]
    DIRECTION OUTPUT ;
    USE SIGNAL ;
    PORT
      LAYER M4 ;
        RECT  21.462 65.52 21.546 65.544 ;
    END
  END q[476]
  PIN q[477]
    DIRECTION OUTPUT ;
    USE SIGNAL ;
    PORT
      LAYER M4 ;
        RECT  21.462 65.664 21.546 65.688 ;
    END
  END q[477]
  PIN q[478]
    DIRECTION OUTPUT ;
    USE SIGNAL ;
    PORT
      LAYER M4 ;
        RECT  21.462 65.76 21.546 65.784 ;
    END
  END q[478]
  PIN q[479]
    DIRECTION OUTPUT ;
    USE SIGNAL ;
    PORT
      LAYER M4 ;
        RECT  21.462 65.904 21.546 65.928 ;
    END
  END q[479]
  PIN q[47]
    DIRECTION OUTPUT ;
    USE SIGNAL ;
    PORT
      LAYER M4 ;
        RECT  21.462 11.328 21.546 11.352 ;
    END
  END q[47]
  PIN q[480]
    DIRECTION OUTPUT ;
    USE SIGNAL ;
    PORT
      LAYER M4 ;
        RECT  21.462 66 21.546 66.024 ;
    END
  END q[480]
  PIN q[481]
    DIRECTION OUTPUT ;
    USE SIGNAL ;
    PORT
      LAYER M4 ;
        RECT  21.462 66.144 21.546 66.168 ;
    END
  END q[481]
  PIN q[482]
    DIRECTION OUTPUT ;
    USE SIGNAL ;
    PORT
      LAYER M4 ;
        RECT  21.462 66.288 21.546 66.312 ;
    END
  END q[482]
  PIN q[483]
    DIRECTION OUTPUT ;
    USE SIGNAL ;
    PORT
      LAYER M4 ;
        RECT  21.462 66.384 21.546 66.408 ;
    END
  END q[483]
  PIN q[484]
    DIRECTION OUTPUT ;
    USE SIGNAL ;
    PORT
      LAYER M4 ;
        RECT  21.462 66.528 21.546 66.552 ;
    END
  END q[484]
  PIN q[485]
    DIRECTION OUTPUT ;
    USE SIGNAL ;
    PORT
      LAYER M4 ;
        RECT  21.462 66.672 21.546 66.696 ;
    END
  END q[485]
  PIN q[486]
    DIRECTION OUTPUT ;
    USE SIGNAL ;
    PORT
      LAYER M4 ;
        RECT  21.462 66.768 21.546 66.792 ;
    END
  END q[486]
  PIN q[487]
    DIRECTION OUTPUT ;
    USE SIGNAL ;
    PORT
      LAYER M4 ;
        RECT  21.462 66.912 21.546 66.936 ;
    END
  END q[487]
  PIN q[488]
    DIRECTION OUTPUT ;
    USE SIGNAL ;
    PORT
      LAYER M4 ;
        RECT  21.462 67.008 21.546 67.032 ;
    END
  END q[488]
  PIN q[489]
    DIRECTION OUTPUT ;
    USE SIGNAL ;
    PORT
      LAYER M4 ;
        RECT  21.462 67.152 21.546 67.176 ;
    END
  END q[489]
  PIN q[48]
    DIRECTION OUTPUT ;
    USE SIGNAL ;
    PORT
      LAYER M4 ;
        RECT  21.462 11.472 21.546 11.496 ;
    END
  END q[48]
  PIN q[490]
    DIRECTION OUTPUT ;
    USE SIGNAL ;
    PORT
      LAYER M4 ;
        RECT  21.462 67.296 21.546 67.32 ;
    END
  END q[490]
  PIN q[491]
    DIRECTION OUTPUT ;
    USE SIGNAL ;
    PORT
      LAYER M4 ;
        RECT  21.462 67.392 21.546 67.416 ;
    END
  END q[491]
  PIN q[492]
    DIRECTION OUTPUT ;
    USE SIGNAL ;
    PORT
      LAYER M4 ;
        RECT  21.462 67.536 21.546 67.56 ;
    END
  END q[492]
  PIN q[493]
    DIRECTION OUTPUT ;
    USE SIGNAL ;
    PORT
      LAYER M4 ;
        RECT  21.462 67.68 21.546 67.704 ;
    END
  END q[493]
  PIN q[494]
    DIRECTION OUTPUT ;
    USE SIGNAL ;
    PORT
      LAYER M4 ;
        RECT  21.462 67.776 21.546 67.8 ;
    END
  END q[494]
  PIN q[495]
    DIRECTION OUTPUT ;
    USE SIGNAL ;
    PORT
      LAYER M4 ;
        RECT  21.462 67.92 21.546 67.944 ;
    END
  END q[495]
  PIN q[496]
    DIRECTION OUTPUT ;
    USE SIGNAL ;
    PORT
      LAYER M4 ;
        RECT  21.462 68.064 21.546 68.088 ;
    END
  END q[496]
  PIN q[497]
    DIRECTION OUTPUT ;
    USE SIGNAL ;
    PORT
      LAYER M4 ;
        RECT  21.462 68.16 21.546 68.184 ;
    END
  END q[497]
  PIN q[498]
    DIRECTION OUTPUT ;
    USE SIGNAL ;
    PORT
      LAYER M4 ;
        RECT  21.462 68.304 21.546 68.328 ;
    END
  END q[498]
  PIN q[499]
    DIRECTION OUTPUT ;
    USE SIGNAL ;
    PORT
      LAYER M4 ;
        RECT  21.462 68.4 21.546 68.424 ;
    END
  END q[499]
  PIN q[49]
    DIRECTION OUTPUT ;
    USE SIGNAL ;
    PORT
      LAYER M4 ;
        RECT  21.462 11.568 21.546 11.592 ;
    END
  END q[49]
  PIN q[4]
    DIRECTION OUTPUT ;
    USE SIGNAL ;
    PORT
      LAYER M4 ;
        RECT  21.462 5.904 21.546 5.928 ;
    END
  END q[4]
  PIN q[500]
    DIRECTION OUTPUT ;
    USE SIGNAL ;
    PORT
      LAYER M4 ;
        RECT  21.462 68.544 21.546 68.568 ;
    END
  END q[500]
  PIN q[501]
    DIRECTION OUTPUT ;
    USE SIGNAL ;
    PORT
      LAYER M4 ;
        RECT  21.462 68.688 21.546 68.712 ;
    END
  END q[501]
  PIN q[502]
    DIRECTION OUTPUT ;
    USE SIGNAL ;
    PORT
      LAYER M4 ;
        RECT  21.462 68.784 21.546 68.808 ;
    END
  END q[502]
  PIN q[503]
    DIRECTION OUTPUT ;
    USE SIGNAL ;
    PORT
      LAYER M4 ;
        RECT  21.462 68.928 21.546 68.952 ;
    END
  END q[503]
  PIN q[504]
    DIRECTION OUTPUT ;
    USE SIGNAL ;
    PORT
      LAYER M4 ;
        RECT  21.462 69.072 21.546 69.096 ;
    END
  END q[504]
  PIN q[505]
    DIRECTION OUTPUT ;
    USE SIGNAL ;
    PORT
      LAYER M4 ;
        RECT  21.462 69.168 21.546 69.192 ;
    END
  END q[505]
  PIN q[506]
    DIRECTION OUTPUT ;
    USE SIGNAL ;
    PORT
      LAYER M4 ;
        RECT  21.462 69.312 21.546 69.336 ;
    END
  END q[506]
  PIN q[507]
    DIRECTION OUTPUT ;
    USE SIGNAL ;
    PORT
      LAYER M4 ;
        RECT  21.462 69.408 21.546 69.432 ;
    END
  END q[507]
  PIN q[508]
    DIRECTION OUTPUT ;
    USE SIGNAL ;
    PORT
      LAYER M4 ;
        RECT  21.462 69.552 21.546 69.576 ;
    END
  END q[508]
  PIN q[509]
    DIRECTION OUTPUT ;
    USE SIGNAL ;
    PORT
      LAYER M4 ;
        RECT  21.462 69.696 21.546 69.72 ;
    END
  END q[509]
  PIN q[50]
    DIRECTION OUTPUT ;
    USE SIGNAL ;
    PORT
      LAYER M4 ;
        RECT  21.462 11.712 21.546 11.736 ;
    END
  END q[50]
  PIN q[510]
    DIRECTION OUTPUT ;
    USE SIGNAL ;
    PORT
      LAYER M4 ;
        RECT  21.462 69.792 21.546 69.816 ;
    END
  END q[510]
  PIN q[511]
    DIRECTION OUTPUT ;
    USE SIGNAL ;
    PORT
      LAYER M4 ;
        RECT  21.462 69.936 21.546 69.96 ;
    END
  END q[511]
  PIN q[512]
    DIRECTION OUTPUT ;
    USE SIGNAL ;
    PORT
      LAYER M4 ;
        RECT  21.462 70.08 21.546 70.104 ;
    END
  END q[512]
  PIN q[513]
    DIRECTION OUTPUT ;
    USE SIGNAL ;
    PORT
      LAYER M4 ;
        RECT  21.462 70.176 21.546 70.2 ;
    END
  END q[513]
  PIN q[51]
    DIRECTION OUTPUT ;
    USE SIGNAL ;
    PORT
      LAYER M4 ;
        RECT  21.462 11.808 21.546 11.832 ;
    END
  END q[51]
  PIN q[52]
    DIRECTION OUTPUT ;
    USE SIGNAL ;
    PORT
      LAYER M4 ;
        RECT  21.462 11.952 21.546 11.976 ;
    END
  END q[52]
  PIN q[53]
    DIRECTION OUTPUT ;
    USE SIGNAL ;
    PORT
      LAYER M4 ;
        RECT  21.462 12.096 21.546 12.12 ;
    END
  END q[53]
  PIN q[54]
    DIRECTION OUTPUT ;
    USE SIGNAL ;
    PORT
      LAYER M4 ;
        RECT  21.462 12.192 21.546 12.216 ;
    END
  END q[54]
  PIN q[55]
    DIRECTION OUTPUT ;
    USE SIGNAL ;
    PORT
      LAYER M4 ;
        RECT  21.462 12.336 21.546 12.36 ;
    END
  END q[55]
  PIN q[56]
    DIRECTION OUTPUT ;
    USE SIGNAL ;
    PORT
      LAYER M4 ;
        RECT  21.462 12.48 21.546 12.504 ;
    END
  END q[56]
  PIN q[57]
    DIRECTION OUTPUT ;
    USE SIGNAL ;
    PORT
      LAYER M4 ;
        RECT  21.462 12.576 21.546 12.6 ;
    END
  END q[57]
  PIN q[58]
    DIRECTION OUTPUT ;
    USE SIGNAL ;
    PORT
      LAYER M4 ;
        RECT  21.462 12.72 21.546 12.744 ;
    END
  END q[58]
  PIN q[59]
    DIRECTION OUTPUT ;
    USE SIGNAL ;
    PORT
      LAYER M4 ;
        RECT  21.462 12.864 21.546 12.888 ;
    END
  END q[59]
  PIN q[5]
    DIRECTION OUTPUT ;
    USE SIGNAL ;
    PORT
      LAYER M4 ;
        RECT  21.462 6 21.546 6.024 ;
    END
  END q[5]
  PIN q[60]
    DIRECTION OUTPUT ;
    USE SIGNAL ;
    PORT
      LAYER M4 ;
        RECT  21.462 12.96 21.546 12.984 ;
    END
  END q[60]
  PIN q[61]
    DIRECTION OUTPUT ;
    USE SIGNAL ;
    PORT
      LAYER M4 ;
        RECT  21.462 13.104 21.546 13.128 ;
    END
  END q[61]
  PIN q[62]
    DIRECTION OUTPUT ;
    USE SIGNAL ;
    PORT
      LAYER M4 ;
        RECT  21.462 13.2 21.546 13.224 ;
    END
  END q[62]
  PIN q[63]
    DIRECTION OUTPUT ;
    USE SIGNAL ;
    PORT
      LAYER M4 ;
        RECT  21.462 13.344 21.546 13.368 ;
    END
  END q[63]
  PIN q[64]
    DIRECTION OUTPUT ;
    USE SIGNAL ;
    PORT
      LAYER M4 ;
        RECT  21.462 13.488 21.546 13.512 ;
    END
  END q[64]
  PIN q[65]
    DIRECTION OUTPUT ;
    USE SIGNAL ;
    PORT
      LAYER M4 ;
        RECT  21.462 13.584 21.546 13.608 ;
    END
  END q[65]
  PIN q[66]
    DIRECTION OUTPUT ;
    USE SIGNAL ;
    PORT
      LAYER M4 ;
        RECT  21.462 13.728 21.546 13.752 ;
    END
  END q[66]
  PIN q[67]
    DIRECTION OUTPUT ;
    USE SIGNAL ;
    PORT
      LAYER M4 ;
        RECT  21.462 13.872 21.546 13.896 ;
    END
  END q[67]
  PIN q[68]
    DIRECTION OUTPUT ;
    USE SIGNAL ;
    PORT
      LAYER M4 ;
        RECT  21.462 13.968 21.546 13.992 ;
    END
  END q[68]
  PIN q[69]
    DIRECTION OUTPUT ;
    USE SIGNAL ;
    PORT
      LAYER M4 ;
        RECT  21.462 14.112 21.546 14.136 ;
    END
  END q[69]
  PIN q[6]
    DIRECTION OUTPUT ;
    USE SIGNAL ;
    PORT
      LAYER M4 ;
        RECT  21.462 6.144 21.546 6.168 ;
    END
  END q[6]
  PIN q[70]
    DIRECTION OUTPUT ;
    USE SIGNAL ;
    PORT
      LAYER M4 ;
        RECT  21.462 14.208 21.546 14.232 ;
    END
  END q[70]
  PIN q[71]
    DIRECTION OUTPUT ;
    USE SIGNAL ;
    PORT
      LAYER M4 ;
        RECT  21.462 14.352 21.546 14.376 ;
    END
  END q[71]
  PIN q[72]
    DIRECTION OUTPUT ;
    USE SIGNAL ;
    PORT
      LAYER M4 ;
        RECT  21.462 14.496 21.546 14.52 ;
    END
  END q[72]
  PIN q[73]
    DIRECTION OUTPUT ;
    USE SIGNAL ;
    PORT
      LAYER M4 ;
        RECT  21.462 14.592 21.546 14.616 ;
    END
  END q[73]
  PIN q[74]
    DIRECTION OUTPUT ;
    USE SIGNAL ;
    PORT
      LAYER M4 ;
        RECT  21.462 14.736 21.546 14.76 ;
    END
  END q[74]
  PIN q[75]
    DIRECTION OUTPUT ;
    USE SIGNAL ;
    PORT
      LAYER M4 ;
        RECT  21.462 14.88 21.546 14.904 ;
    END
  END q[75]
  PIN q[76]
    DIRECTION OUTPUT ;
    USE SIGNAL ;
    PORT
      LAYER M4 ;
        RECT  21.462 14.976 21.546 15 ;
    END
  END q[76]
  PIN q[77]
    DIRECTION OUTPUT ;
    USE SIGNAL ;
    PORT
      LAYER M4 ;
        RECT  21.462 15.12 21.546 15.144 ;
    END
  END q[77]
  PIN q[78]
    DIRECTION OUTPUT ;
    USE SIGNAL ;
    PORT
      LAYER M4 ;
        RECT  21.462 15.264 21.546 15.288 ;
    END
  END q[78]
  PIN q[79]
    DIRECTION OUTPUT ;
    USE SIGNAL ;
    PORT
      LAYER M4 ;
        RECT  21.462 15.36 21.546 15.384 ;
    END
  END q[79]
  PIN q[7]
    DIRECTION OUTPUT ;
    USE SIGNAL ;
    PORT
      LAYER M4 ;
        RECT  21.462 6.288 21.546 6.312 ;
    END
  END q[7]
  PIN q[80]
    DIRECTION OUTPUT ;
    USE SIGNAL ;
    PORT
      LAYER M4 ;
        RECT  21.462 15.504 21.546 15.528 ;
    END
  END q[80]
  PIN q[81]
    DIRECTION OUTPUT ;
    USE SIGNAL ;
    PORT
      LAYER M4 ;
        RECT  21.462 15.6 21.546 15.624 ;
    END
  END q[81]
  PIN q[82]
    DIRECTION OUTPUT ;
    USE SIGNAL ;
    PORT
      LAYER M4 ;
        RECT  21.462 15.744 21.546 15.768 ;
    END
  END q[82]
  PIN q[83]
    DIRECTION OUTPUT ;
    USE SIGNAL ;
    PORT
      LAYER M4 ;
        RECT  21.462 15.888 21.546 15.912 ;
    END
  END q[83]
  PIN q[84]
    DIRECTION OUTPUT ;
    USE SIGNAL ;
    PORT
      LAYER M4 ;
        RECT  21.462 15.984 21.546 16.008 ;
    END
  END q[84]
  PIN q[85]
    DIRECTION OUTPUT ;
    USE SIGNAL ;
    PORT
      LAYER M4 ;
        RECT  21.462 16.128 21.546 16.152 ;
    END
  END q[85]
  PIN q[86]
    DIRECTION OUTPUT ;
    USE SIGNAL ;
    PORT
      LAYER M4 ;
        RECT  21.462 16.272 21.546 16.296 ;
    END
  END q[86]
  PIN q[87]
    DIRECTION OUTPUT ;
    USE SIGNAL ;
    PORT
      LAYER M4 ;
        RECT  21.462 16.368 21.546 16.392 ;
    END
  END q[87]
  PIN q[88]
    DIRECTION OUTPUT ;
    USE SIGNAL ;
    PORT
      LAYER M4 ;
        RECT  21.462 16.512 21.546 16.536 ;
    END
  END q[88]
  PIN q[89]
    DIRECTION OUTPUT ;
    USE SIGNAL ;
    PORT
      LAYER M4 ;
        RECT  21.462 16.608 21.546 16.632 ;
    END
  END q[89]
  PIN q[8]
    DIRECTION OUTPUT ;
    USE SIGNAL ;
    PORT
      LAYER M4 ;
        RECT  21.462 6.384 21.546 6.408 ;
    END
  END q[8]
  PIN q[90]
    DIRECTION OUTPUT ;
    USE SIGNAL ;
    PORT
      LAYER M4 ;
        RECT  21.462 16.752 21.546 16.776 ;
    END
  END q[90]
  PIN q[91]
    DIRECTION OUTPUT ;
    USE SIGNAL ;
    PORT
      LAYER M4 ;
        RECT  21.462 16.896 21.546 16.92 ;
    END
  END q[91]
  PIN q[92]
    DIRECTION OUTPUT ;
    USE SIGNAL ;
    PORT
      LAYER M4 ;
        RECT  21.462 16.992 21.546 17.016 ;
    END
  END q[92]
  PIN q[93]
    DIRECTION OUTPUT ;
    USE SIGNAL ;
    PORT
      LAYER M4 ;
        RECT  21.462 17.136 21.546 17.16 ;
    END
  END q[93]
  PIN q[94]
    DIRECTION OUTPUT ;
    USE SIGNAL ;
    PORT
      LAYER M4 ;
        RECT  21.462 17.28 21.546 17.304 ;
    END
  END q[94]
  PIN q[95]
    DIRECTION OUTPUT ;
    USE SIGNAL ;
    PORT
      LAYER M4 ;
        RECT  21.462 17.376 21.546 17.4 ;
    END
  END q[95]
  PIN q[96]
    DIRECTION OUTPUT ;
    USE SIGNAL ;
    PORT
      LAYER M4 ;
        RECT  21.462 17.52 21.546 17.544 ;
    END
  END q[96]
  PIN q[97]
    DIRECTION OUTPUT ;
    USE SIGNAL ;
    PORT
      LAYER M4 ;
        RECT  21.462 17.664 21.546 17.688 ;
    END
  END q[97]
  PIN q[98]
    DIRECTION OUTPUT ;
    USE SIGNAL ;
    PORT
      LAYER M4 ;
        RECT  21.462 17.76 21.546 17.784 ;
    END
  END q[98]
  PIN q[99]
    DIRECTION OUTPUT ;
    USE SIGNAL ;
    PORT
      LAYER M4 ;
        RECT  21.462 17.904 21.546 17.928 ;
    END
  END q[99]
  PIN q[9]
    DIRECTION OUTPUT ;
    USE SIGNAL ;
    PORT
      LAYER M4 ;
        RECT  21.462 6.528 21.546 6.552 ;
    END
  END q[9]
  PIN rst_n
    DIRECTION INPUT ;
    USE SIGNAL ;
    PORT
      LAYER M5 ;
        RECT  9.696 0.054 9.72 0.138 ;
    END
    PORT
      LAYER M5 ;
        RECT  9.696 0.08 9.72 2.137 ;
    END
  END rst_n
  PIN VDD
    DIRECTION INOUT ;
    USE POWER ;
    PORT
      LAYER M5 ;
        RECT  18.792 2.151 18.912 73.449 ;
        RECT  16.092 2.151 16.212 73.449 ;
        RECT  13.392 2.151 13.512 73.449 ;
        RECT  10.692 2.151 10.812 73.449 ;
        RECT  7.992 2.151 8.112 73.449 ;
        RECT  5.292 2.151 5.412 73.449 ;
        RECT  2.592 2.151 2.712 73.449 ;
    END
  END VDD
  PIN VSS
    DIRECTION INOUT ;
    USE GROUND ;
    PORT
      LAYER M5 ;
        RECT  18.6 2.137 18.72 73.463 ;
        RECT  15.9 2.137 16.02 73.463 ;
        RECT  13.2 2.137 13.32 73.463 ;
        RECT  10.5 2.137 10.62 73.463 ;
        RECT  7.8 2.137 7.92 73.463 ;
        RECT  5.1 2.137 5.22 73.463 ;
        RECT  2.4 2.137 2.52 73.463 ;
    END
  END VSS
  # OT_OBS_CLOSED layer=M5 d_um=1.536 added=77
  OBS
    LAYER RVTN ;
     RECT  2.16 2.16 19.44 2.295 ;
     RECT  2.16 2.565 19.44 2.835 ;
     RECT  2.16 3.105 19.44 3.375 ;
     RECT  2.16 3.645 19.44 3.915 ;
     RECT  2.16 4.185 19.44 4.455 ;
     RECT  2.16 4.725 19.44 4.995 ;
     RECT  2.16 5.265 19.44 5.535 ;
     RECT  2.16 5.805 19.44 6.075 ;
     RECT  2.16 6.345 19.44 6.615 ;
     RECT  2.16 6.885 19.44 7.155 ;
     RECT  2.16 7.425 19.44 7.695 ;
     RECT  2.16 7.965 19.44 8.235 ;
     RECT  2.16 8.505 19.44 8.775 ;
     RECT  2.16 9.045 19.44 9.315 ;
     RECT  2.16 9.585 19.44 9.855 ;
     RECT  2.16 10.125 19.44 10.395 ;
     RECT  2.16 10.665 19.44 10.935 ;
     RECT  2.16 11.205 19.44 11.475 ;
     RECT  2.16 11.745 19.44 12.015 ;
     RECT  2.16 12.285 19.44 12.555 ;
     RECT  2.16 12.825 19.44 13.095 ;
     RECT  2.16 13.365 19.44 13.635 ;
     RECT  2.16 13.905 19.44 14.175 ;
     RECT  2.16 14.445 19.44 14.715 ;
     RECT  2.16 14.985 19.44 15.255 ;
     RECT  2.16 15.525 19.44 15.795 ;
     RECT  2.16 16.065 19.44 16.335 ;
     RECT  2.16 16.605 19.44 16.875 ;
     RECT  2.16 17.145 19.44 17.415 ;
     RECT  2.16 17.685 19.44 17.955 ;
     RECT  2.16 18.225 19.44 18.495 ;
     RECT  2.16 18.765 19.44 19.035 ;
     RECT  2.16 19.305 19.44 19.575 ;
     RECT  2.16 19.845 19.44 20.115 ;
     RECT  2.16 20.385 19.44 20.655 ;
     RECT  2.16 20.925 19.44 21.195 ;
     RECT  2.16 21.465 19.44 21.735 ;
     RECT  2.16 22.005 19.44 22.275 ;
     RECT  2.16 22.545 19.44 22.815 ;
     RECT  2.16 23.085 19.44 23.355 ;
     RECT  2.16 23.625 19.44 23.895 ;
     RECT  2.16 24.165 19.44 24.435 ;
     RECT  2.16 24.705 19.44 24.975 ;
     RECT  2.16 25.245 19.44 25.515 ;
     RECT  2.16 25.785 19.44 26.055 ;
     RECT  2.16 26.325 19.44 26.595 ;
     RECT  2.16 26.865 19.44 27.135 ;
     RECT  2.16 27.405 19.44 27.675 ;
     RECT  2.16 27.945 19.44 28.215 ;
     RECT  2.16 28.485 19.44 28.755 ;
     RECT  2.16 29.025 19.44 29.295 ;
     RECT  2.16 29.565 19.44 29.835 ;
     RECT  2.16 30.105 19.44 30.375 ;
     RECT  2.16 30.645 19.44 30.915 ;
     RECT  2.16 31.185 19.44 31.455 ;
     RECT  2.16 31.725 19.44 31.995 ;
     RECT  2.16 32.265 19.44 32.535 ;
     RECT  2.16 32.805 19.44 33.075 ;
     RECT  2.16 33.345 19.44 33.615 ;
     RECT  2.16 33.885 19.44 34.155 ;
     RECT  2.16 34.425 19.44 34.695 ;
     RECT  2.16 34.965 19.44 35.235 ;
     RECT  2.16 35.505 19.44 35.775 ;
     RECT  2.16 36.045 19.44 36.315 ;
     RECT  2.16 36.585 19.44 36.855 ;
     RECT  2.16 37.125 19.44 37.395 ;
     RECT  2.16 37.665 19.44 37.935 ;
     RECT  2.16 38.205 19.44 38.475 ;
     RECT  2.16 38.745 19.44 39.015 ;
     RECT  2.16 39.285 19.44 39.555 ;
     RECT  2.16 39.825 19.44 40.095 ;
     RECT  2.16 40.365 19.44 40.635 ;
     RECT  2.16 40.905 19.44 41.175 ;
     RECT  2.16 41.445 19.44 41.715 ;
     RECT  2.16 41.985 19.44 42.255 ;
     RECT  2.16 42.525 19.44 42.795 ;
     RECT  2.16 43.065 19.44 43.335 ;
     RECT  2.16 43.605 19.44 43.875 ;
     RECT  2.16 44.145 19.44 44.415 ;
     RECT  2.16 44.685 19.44 44.955 ;
     RECT  2.16 45.225 19.44 45.495 ;
     RECT  2.16 45.765 19.44 46.035 ;
     RECT  2.16 46.305 19.44 46.575 ;
     RECT  2.16 46.845 19.44 47.115 ;
     RECT  2.16 47.385 19.44 47.655 ;
     RECT  2.16 47.925 19.44 48.195 ;
     RECT  2.16 48.465 19.44 48.735 ;
     RECT  2.16 49.005 19.44 49.275 ;
     RECT  2.16 49.545 19.44 49.815 ;
     RECT  2.16 50.085 19.44 50.355 ;
     RECT  2.16 50.625 19.44 50.895 ;
     RECT  2.16 51.165 19.44 51.435 ;
     RECT  2.16 51.705 19.44 51.975 ;
     RECT  2.16 52.245 19.44 52.515 ;
     RECT  2.16 52.785 19.44 53.055 ;
     RECT  2.16 53.325 19.44 53.595 ;
     RECT  2.16 53.865 19.44 54.135 ;
     RECT  2.16 54.405 19.44 54.675 ;
     RECT  2.16 54.945 19.44 55.215 ;
     RECT  2.16 55.485 19.44 55.755 ;
     RECT  2.16 56.025 19.44 56.295 ;
     RECT  2.16 56.565 19.44 56.835 ;
     RECT  2.16 57.105 19.44 57.375 ;
     RECT  2.16 57.645 19.44 57.915 ;
     RECT  2.16 58.185 19.44 58.455 ;
     RECT  2.16 58.725 19.44 58.995 ;
     RECT  2.16 59.265 19.44 59.535 ;
     RECT  2.16 59.805 19.44 60.075 ;
     RECT  2.16 60.345 19.44 60.615 ;
     RECT  2.16 60.885 19.44 61.155 ;
     RECT  2.16 61.425 19.44 61.695 ;
     RECT  2.16 61.965 19.44 62.235 ;
     RECT  2.16 62.505 19.44 62.775 ;
     RECT  2.16 63.045 19.44 63.315 ;
     RECT  2.16 63.585 19.44 63.855 ;
     RECT  2.16 64.125 19.44 64.395 ;
     RECT  2.16 64.665 19.44 64.935 ;
     RECT  2.16 65.205 19.44 65.475 ;
     RECT  2.16 65.745 19.44 66.015 ;
     RECT  2.16 66.285 19.44 66.555 ;
     RECT  2.16 66.825 19.44 67.095 ;
     RECT  2.16 67.365 19.44 67.635 ;
     RECT  2.16 67.905 19.44 68.175 ;
     RECT  2.16 68.445 19.44 68.715 ;
     RECT  2.16 68.985 19.44 69.255 ;
     RECT  2.16 69.525 19.44 69.795 ;
     RECT  2.16 70.065 19.44 70.335 ;
     RECT  2.16 70.605 19.44 70.875 ;
     RECT  2.16 71.145 19.44 71.415 ;
     RECT  2.16 71.685 19.44 71.955 ;
     RECT  2.16 72.225 19.44 72.495 ;
     RECT  2.16 72.765 19.44 73.035 ;
     RECT  2.16 73.305 19.44 73.44 ;
    LAYER RVTP ;
     RECT  2.16 2.295 19.44 2.565 ;
     RECT  2.16 2.835 19.44 3.105 ;
     RECT  2.16 3.375 19.44 3.645 ;
     RECT  2.16 3.915 19.44 4.185 ;
     RECT  2.16 4.455 19.44 4.725 ;
     RECT  2.16 4.995 19.44 5.265 ;
     RECT  2.16 5.535 19.44 5.805 ;
     RECT  2.16 6.075 19.44 6.345 ;
     RECT  2.16 6.615 19.44 6.885 ;
     RECT  2.16 7.155 19.44 7.425 ;
     RECT  2.16 7.695 19.44 7.965 ;
     RECT  2.16 8.235 19.44 8.505 ;
     RECT  2.16 8.775 19.44 9.045 ;
     RECT  2.16 9.315 19.44 9.585 ;
     RECT  2.16 9.855 19.44 10.125 ;
     RECT  2.16 10.395 19.44 10.665 ;
     RECT  2.16 10.935 19.44 11.205 ;
     RECT  2.16 11.475 19.44 11.745 ;
     RECT  2.16 12.015 19.44 12.285 ;
     RECT  2.16 12.555 19.44 12.825 ;
     RECT  2.16 13.095 19.44 13.365 ;
     RECT  2.16 13.635 19.44 13.905 ;
     RECT  2.16 14.175 19.44 14.445 ;
     RECT  2.16 14.715 19.44 14.985 ;
     RECT  2.16 15.255 19.44 15.525 ;
     RECT  2.16 15.795 19.44 16.065 ;
     RECT  2.16 16.335 19.44 16.605 ;
     RECT  2.16 16.875 19.44 17.145 ;
     RECT  2.16 17.415 19.44 17.685 ;
     RECT  2.16 17.955 19.44 18.225 ;
     RECT  2.16 18.495 19.44 18.765 ;
     RECT  2.16 19.035 19.44 19.305 ;
     RECT  2.16 19.575 19.44 19.845 ;
     RECT  2.16 20.115 19.44 20.385 ;
     RECT  2.16 20.655 19.44 20.925 ;
     RECT  2.16 21.195 19.44 21.465 ;
     RECT  2.16 21.735 19.44 22.005 ;
     RECT  2.16 22.275 19.44 22.545 ;
     RECT  2.16 22.815 19.44 23.085 ;
     RECT  2.16 23.355 19.44 23.625 ;
     RECT  2.16 23.895 19.44 24.165 ;
     RECT  2.16 24.435 19.44 24.705 ;
     RECT  2.16 24.975 19.44 25.245 ;
     RECT  2.16 25.515 19.44 25.785 ;
     RECT  2.16 26.055 19.44 26.325 ;
     RECT  2.16 26.595 19.44 26.865 ;
     RECT  2.16 27.135 19.44 27.405 ;
     RECT  2.16 27.675 19.44 27.945 ;
     RECT  2.16 28.215 19.44 28.485 ;
     RECT  2.16 28.755 19.44 29.025 ;
     RECT  2.16 29.295 19.44 29.565 ;
     RECT  2.16 29.835 19.44 30.105 ;
     RECT  2.16 30.375 19.44 30.645 ;
     RECT  2.16 30.915 19.44 31.185 ;
     RECT  2.16 31.455 19.44 31.725 ;
     RECT  2.16 31.995 19.44 32.265 ;
     RECT  2.16 32.535 19.44 32.805 ;
     RECT  2.16 33.075 19.44 33.345 ;
     RECT  2.16 33.615 19.44 33.885 ;
     RECT  2.16 34.155 19.44 34.425 ;
     RECT  2.16 34.695 19.44 34.965 ;
     RECT  2.16 35.235 19.44 35.505 ;
     RECT  2.16 35.775 19.44 36.045 ;
     RECT  2.16 36.315 19.44 36.585 ;
     RECT  2.16 36.855 19.44 37.125 ;
     RECT  2.16 37.395 19.44 37.665 ;
     RECT  2.16 37.935 19.44 38.205 ;
     RECT  2.16 38.475 19.44 38.745 ;
     RECT  2.16 39.015 19.44 39.285 ;
     RECT  2.16 39.555 19.44 39.825 ;
     RECT  2.16 40.095 19.44 40.365 ;
     RECT  2.16 40.635 19.44 40.905 ;
     RECT  2.16 41.175 19.44 41.445 ;
     RECT  2.16 41.715 19.44 41.985 ;
     RECT  2.16 42.255 19.44 42.525 ;
     RECT  2.16 42.795 19.44 43.065 ;
     RECT  2.16 43.335 19.44 43.605 ;
     RECT  2.16 43.875 19.44 44.145 ;
     RECT  2.16 44.415 19.44 44.685 ;
     RECT  2.16 44.955 19.44 45.225 ;
     RECT  2.16 45.495 19.44 45.765 ;
     RECT  2.16 46.035 19.44 46.305 ;
     RECT  2.16 46.575 19.44 46.845 ;
     RECT  2.16 47.115 19.44 47.385 ;
     RECT  2.16 47.655 19.44 47.925 ;
     RECT  2.16 48.195 19.44 48.465 ;
     RECT  2.16 48.735 19.44 49.005 ;
     RECT  2.16 49.275 19.44 49.545 ;
     RECT  2.16 49.815 19.44 50.085 ;
     RECT  2.16 50.355 19.44 50.625 ;
     RECT  2.16 50.895 19.44 51.165 ;
     RECT  2.16 51.435 19.44 51.705 ;
     RECT  2.16 51.975 19.44 52.245 ;
     RECT  2.16 52.515 19.44 52.785 ;
     RECT  2.16 53.055 19.44 53.325 ;
     RECT  2.16 53.595 19.44 53.865 ;
     RECT  2.16 54.135 19.44 54.405 ;
     RECT  2.16 54.675 19.44 54.945 ;
     RECT  2.16 55.215 19.44 55.485 ;
     RECT  2.16 55.755 19.44 56.025 ;
     RECT  2.16 56.295 19.44 56.565 ;
     RECT  2.16 56.835 19.44 57.105 ;
     RECT  2.16 57.375 19.44 57.645 ;
     RECT  2.16 57.915 19.44 58.185 ;
     RECT  2.16 58.455 19.44 58.725 ;
     RECT  2.16 58.995 19.44 59.265 ;
     RECT  2.16 59.535 19.44 59.805 ;
     RECT  2.16 60.075 19.44 60.345 ;
     RECT  2.16 60.615 19.44 60.885 ;
     RECT  2.16 61.155 19.44 61.425 ;
     RECT  2.16 61.695 19.44 61.965 ;
     RECT  2.16 62.235 19.44 62.505 ;
     RECT  2.16 62.775 19.44 63.045 ;
     RECT  2.16 63.315 19.44 63.585 ;
     RECT  2.16 63.855 19.44 64.125 ;
     RECT  2.16 64.395 19.44 64.665 ;
     RECT  2.16 64.935 19.44 65.205 ;
     RECT  2.16 65.475 19.44 65.745 ;
     RECT  2.16 66.015 19.44 66.285 ;
     RECT  2.16 66.555 19.44 66.825 ;
     RECT  2.16 67.095 19.44 67.365 ;
     RECT  2.16 67.635 19.44 67.905 ;
     RECT  2.16 68.175 19.44 68.445 ;
     RECT  2.16 68.715 19.44 68.985 ;
     RECT  2.16 69.255 19.44 69.525 ;
     RECT  2.16 69.795 19.44 70.065 ;
     RECT  2.16 70.335 19.44 70.605 ;
     RECT  2.16 70.875 19.44 71.145 ;
     RECT  2.16 71.415 19.44 71.685 ;
     RECT  2.16 71.955 19.44 72.225 ;
     RECT  2.16 72.495 19.44 72.765 ;
     RECT  2.16 73.035 19.44 73.305 ;
    LAYER M1 ;
     RECT  2.16 2.151 19.44 73.449 ;
    LAYER M2 ;
     RECT  0.031 29.034 0.131 29.052 ;
     RECT  0.031 6.624 0.139 6.642 ;
     RECT  0.031 11.952 0.139 11.97 ;
     RECT  0.031 19.62 0.139 19.638 ;
     RECT  0.031 24.786 0.139 24.804 ;
     RECT  0.031 29.844 0.139 29.862 ;
     RECT  0.031 33.156 0.139 33.57 ;
     RECT  0.031 38.556 0.139 38.574 ;
     RECT  0.139 4.77 0.175 4.788 ;
     RECT  0.139 42.3 0.175 42.318 ;
     RECT  0.175 4.5 0.211 4.788 ;
     RECT  0.139 5.58 0.211 5.598 ;
     RECT  0.139 19.242 0.239 19.638 ;
     RECT  0.139 23.67 0.239 24.804 ;
     RECT  0.139 29.844 0.239 30.096 ;
     RECT  0.031 37.332 0.239 37.35 ;
     RECT  0.031 52.83 0.239 52.848 ;
     RECT  0.031 69.876 0.239 69.894 ;
     RECT  0.031 16.236 0.283 16.254 ;
     RECT  0.283 16.236 0.311 16.326 ;
     RECT  0.139 33.084 0.311 33.57 ;
     RECT  0.031 43.272 0.311 43.29 ;
     RECT  0.311 33.084 0.383 33.444 ;
     RECT  0.311 16.308 0.535 16.326 ;
     RECT  0.139 17.46 0.535 17.478 ;
     RECT  0.139 22.716 0.535 22.734 ;
     RECT  0.239 23.67 0.535 24.462 ;
     RECT  0.139 40.41 0.535 40.428 ;
     RECT  0.139 44.892 0.535 44.91 ;
     RECT  0.139 58.122 0.535 58.68 ;
     RECT  0.211 4.5 2.16 5.598 ;
     RECT  0.139 6.624 2.16 8.46 ;
     RECT  0.139 11.25 2.16 11.97 ;
     RECT  0.139 13.032 2.16 13.05 ;
     RECT  0.535 16.308 2.16 17.478 ;
     RECT  0.239 19.242 2.16 19.26 ;
     RECT  0.535 22.716 2.16 24.462 ;
     RECT  0.139 27.918 2.16 28.44 ;
     RECT  0.239 30.078 2.16 30.096 ;
     RECT  0.383 33.426 2.16 33.444 ;
     RECT  0.535 34.632 2.16 34.65 ;
     RECT  0.535 36.63 2.16 36.648 ;
     RECT  0.139 38.556 2.16 39.24 ;
     RECT  0.535 40.374 2.16 40.428 ;
     RECT  0.175 42.228 2.16 42.318 ;
     RECT  0.535 44.424 2.16 45.018 ;
     RECT  0.139 47.16 2.16 48.186 ;
     RECT  0.139 51.246 2.16 51.264 ;
     RECT  0.139 54.108 2.16 54.126 ;
     RECT  0.535 55.26 2.16 55.278 ;
     RECT  0.535 56.88 2.16 56.898 ;
     RECT  0.535 57.996 2.16 58.68 ;
     RECT  0.535 60.39 2.16 60.408 ;
     RECT  0.535 62.01 2.16 62.028 ;
     RECT  0.535 63.666 2.16 63.684 ;
     RECT  1.147 71.352 2.16 71.37 ;
     RECT  2.16 2.151 19.44 73.449 ;
     RECT  19.44 6.012 19.931 12.114 ;
     RECT  19.44 12.996 19.931 71.334 ;
     RECT  19.931 12.996 19.967 71.064 ;
     RECT  19.967 46.314 20.399 71.064 ;
     RECT  19.931 10.206 20.435 12.114 ;
     RECT  20.399 46.314 20.435 70.524 ;
     RECT  19.967 12.996 20.471 45.522 ;
     RECT  20.435 46.314 20.471 70.254 ;
     RECT  19.931 6.012 20.507 9.234 ;
     RECT  20.435 10.476 20.507 12.114 ;
     RECT  20.471 12.996 20.507 14.274 ;
     RECT  20.471 15.264 20.507 45.522 ;
     RECT  20.471 46.746 20.507 48.654 ;
     RECT  20.471 49.518 20.507 64.854 ;
     RECT  20.471 65.826 20.507 69.984 ;
     RECT  19.44 4.266 20.543 5.094 ;
     RECT  20.507 6.012 20.543 8.532 ;
     RECT  20.507 10.476 20.543 11.808 ;
     RECT  20.507 13.536 20.543 14.274 ;
     RECT  20.507 18.774 20.543 20.142 ;
     RECT  20.507 21.096 20.543 24.264 ;
     RECT  20.507 25.02 20.543 27.774 ;
     RECT  20.507 28.8 20.543 29.394 ;
     RECT  20.507 30.654 20.543 33.174 ;
     RECT  20.507 34.596 20.543 37.044 ;
     RECT  20.507 38.016 20.543 40.392 ;
     RECT  20.507 41.418 20.543 43.704 ;
     RECT  20.507 46.746 20.543 47.988 ;
     RECT  20.507 49.518 20.543 58.788 ;
     RECT  20.507 64.17 20.543 64.854 ;
     RECT  20.543 4.428 20.579 5.094 ;
     RECT  20.543 7.164 20.579 7.992 ;
     RECT  20.543 19.242 20.579 20.142 ;
     RECT  20.543 23.634 20.579 24.12 ;
     RECT  20.543 28.8 20.579 29.286 ;
     RECT  20.543 31.086 20.579 33.174 ;
     RECT  20.543 34.866 20.579 37.044 ;
     RECT  20.543 53.298 20.579 53.316 ;
     RECT  20.543 57.276 20.579 57.474 ;
     RECT  20.543 22.788 20.615 22.806 ;
     RECT  20.543 46.746 20.615 47.88 ;
     RECT  20.507 15.264 20.651 17.676 ;
     RECT  20.543 6.012 21.371 6.264 ;
     RECT  20.579 7.164 21.371 7.956 ;
     RECT  20.543 25.02 21.371 26.964 ;
     RECT  20.507 59.616 21.371 63.27 ;
     RECT  20.543 64.17 21.371 64.458 ;
     RECT  20.543 39.6 21.379 40.392 ;
     RECT  20.579 57.276 21.379 57.294 ;
     RECT  20.579 4.806 21.407 5.094 ;
     RECT  21.371 7.938 21.407 7.956 ;
     RECT  20.651 15.264 21.407 16.398 ;
     RECT  20.579 19.242 21.407 19.404 ;
     RECT  20.579 23.904 21.407 24.12 ;
     RECT  21.371 25.02 21.407 25.704 ;
     RECT  21.371 26.496 21.407 26.964 ;
     RECT  20.579 28.8 21.407 29.214 ;
     RECT  20.579 31.086 21.407 32.598 ;
     RECT  20.579 35.244 21.407 37.044 ;
     RECT  20.543 41.886 21.407 43.632 ;
     RECT  20.543 49.518 21.407 52.164 ;
     RECT  20.543 54.216 21.407 54.666 ;
     RECT  21.371 59.616 21.407 60.3 ;
     RECT  21.371 61.128 21.407 62.424 ;
     RECT  21.371 63.252 21.407 63.27 ;
     RECT  21.371 64.17 21.407 64.386 ;
     RECT  20.507 66.906 21.407 67.392 ;
     RECT  20.507 69.336 21.407 69.444 ;
     RECT  21.407 4.806 21.443 4.824 ;
     RECT  21.371 6.246 21.443 6.264 ;
     RECT  21.371 7.164 21.443 7.182 ;
     RECT  20.543 10.71 21.443 11.808 ;
     RECT  20.543 13.536 21.443 14.166 ;
     RECT  21.407 15.264 21.443 16.362 ;
     RECT  20.651 17.658 21.443 17.676 ;
     RECT  21.407 19.386 21.443 19.404 ;
     RECT  20.543 21.096 21.443 22.032 ;
     RECT  21.407 23.904 21.443 23.922 ;
     RECT  21.407 26.496 21.443 26.514 ;
     RECT  20.543 27.756 21.443 27.774 ;
     RECT  21.407 29.196 21.443 29.214 ;
     RECT  21.407 31.086 21.443 31.104 ;
     RECT  21.407 31.896 21.443 32.598 ;
     RECT  21.407 35.784 21.443 37.044 ;
     RECT  20.543 38.214 21.443 38.232 ;
     RECT  21.379 39.06 21.443 40.392 ;
     RECT  21.407 41.886 21.443 42.822 ;
     RECT  21.407 43.614 21.443 43.632 ;
     RECT  20.507 44.496 21.443 45.522 ;
     RECT  20.615 46.746 21.443 46.764 ;
     RECT  20.615 47.862 21.443 47.88 ;
     RECT  21.407 50.364 21.443 52.164 ;
     RECT  21.407 54.216 21.443 54.234 ;
     RECT  20.543 55.8 21.443 56.484 ;
     RECT  21.379 57.276 21.443 57.519 ;
     RECT  20.543 58.77 21.443 58.788 ;
     RECT  21.407 59.616 21.443 59.634 ;
     RECT  21.407 61.398 21.443 62.424 ;
     RECT  21.407 64.17 21.443 64.188 ;
     RECT  20.507 65.826 21.443 65.844 ;
     RECT  21.407 69.426 21.443 69.444 ;
     RECT  19.44 72.666 21.551 72.684 ;
     RECT  21.443 39.06 21.587 39.078 ;
     RECT  21.443 56.466 21.587 56.484 ;
     RECT  21.443 57.501 21.587 57.519 ;
     RECT  21.443 62.136 21.587 62.154 ;
    LAYER M3 ;
     RECT  2.415 2.143 2.505 2.413 ;
     RECT  5.115 2.143 5.205 2.413 ;
     RECT  7.815 2.143 7.905 2.413 ;
     RECT  10.515 2.143 10.605 2.413 ;
     RECT  13.215 2.143 13.305 2.413 ;
     RECT  15.915 2.143 16.005 2.413 ;
     RECT  18.615 2.143 18.705 2.413 ;
     RECT  18.615 2.413 18.897 2.641 ;
     RECT  5.115 2.413 5.397 2.803 ;
     RECT  18.216 2.641 18.897 2.803 ;
     RECT  5.115 2.803 5.706 2.861 ;
     RECT  18.216 2.803 18.99 3.145 ;
     RECT  18.216 3.145 19.134 3.181 ;
     RECT  4.104 2.767 4.122 3.307 ;
     RECT  17.784 3.181 19.134 3.343 ;
     RECT  17.784 3.343 19.206 3.541 ;
     RECT  10.515 2.413 10.797 3.613 ;
     RECT  11.556 3.577 11.574 3.613 ;
     RECT  4.068 3.307 4.122 3.685 ;
     RECT  14.832 3.613 14.922 3.713 ;
     RECT  17.568 3.541 19.206 3.721 ;
     RECT  14.832 3.713 14.85 3.749 ;
     RECT  10.515 3.613 11.574 3.811 ;
     RECT  3.996 3.685 4.122 3.847 ;
     RECT  5.115 2.861 5.49 3.955 ;
     RECT  6.264 3.685 6.282 3.955 ;
     RECT  3.996 3.847 4.194 4.225 ;
     RECT  17.568 3.721 19.278 4.261 ;
     RECT  10.152 3.811 11.574 4.423 ;
     RECT  20.52 4.261 20.538 4.423 ;
     RECT  3.852 4.225 4.194 4.531 ;
     RECT  5.115 3.955 6.282 4.531 ;
     RECT  2.415 2.413 2.697 4.621 ;
     RECT  3.42 4.531 6.282 4.621 ;
     RECT  0.18 4.495 0.198 4.729 ;
     RECT  0.18 4.729 0.558 4.765 ;
     RECT  2.415 4.621 6.282 4.765 ;
     RECT  7.815 2.413 8.097 4.765 ;
     RECT  17.244 4.261 19.278 4.801 ;
     RECT  2.376 4.765 6.282 4.919 ;
     RECT  15.915 2.413 16.197 4.999 ;
     RECT  17.064 4.801 19.278 4.999 ;
     RECT  7.38 4.765 8.097 5.071 ;
     RECT  21.42 4.801 21.438 5.071 ;
     RECT  14.832 5.197 14.85 5.233 ;
     RECT  7.236 5.071 8.097 5.305 ;
     RECT  2.415 4.919 6.282 5.341 ;
     RECT  2.415 5.341 6.354 5.467 ;
     RECT  7.2 5.305 8.097 5.467 ;
     RECT  14.832 5.233 14.886 5.503 ;
     RECT  15.915 4.999 19.278 5.503 ;
     RECT  0.144 4.765 0.558 5.693 ;
     RECT  14.832 5.503 19.278 5.729 ;
     RECT  2.415 5.467 8.097 5.737 ;
     RECT  8.82 5.467 8.838 5.737 ;
     RECT  2.415 5.737 8.838 5.773 ;
     RECT  2.415 5.773 8.982 5.845 ;
     RECT  10.152 4.423 11.754 5.971 ;
     RECT  10.152 5.971 11.79 6.007 ;
     RECT  21.384 5.071 21.438 6.007 ;
     RECT  14.832 5.729 14.886 6.071 ;
     RECT  2.304 5.845 8.982 6.079 ;
     RECT  15.915 5.729 19.278 6.079 ;
     RECT  20.52 4.423 20.574 6.079 ;
     RECT  14.832 6.071 14.85 6.179 ;
     RECT  10.152 6.007 12.186 6.269 ;
     RECT  0.144 5.693 0.27 6.317 ;
     RECT  21.348 6.007 21.438 6.413 ;
     RECT  10.152 6.269 10.797 6.421 ;
     RECT  21.348 6.413 21.366 6.557 ;
     RECT  2.304 6.079 9.306 6.575 ;
     RECT  0.144 6.317 0.162 6.619 ;
     RECT  8.82 6.575 9.306 6.619 ;
     RECT  10.044 6.421 10.797 6.619 ;
     RECT  15.915 6.079 20.574 6.701 ;
     RECT  8.82 6.619 10.797 6.809 ;
     RECT  8.82 6.809 9.702 6.845 ;
     RECT  15.915 6.701 20.538 6.941 ;
     RECT  8.928 6.845 9.702 6.953 ;
     RECT  11.736 6.269 12.186 7.079 ;
     RECT  2.304 6.575 8.097 7.223 ;
     RECT  14.832 7.159 14.85 7.231 ;
     RECT  2.34 7.223 8.097 7.321 ;
     RECT  21.42 7.159 21.438 7.321 ;
     RECT  11.772 7.079 12.186 7.349 ;
     RECT  14.544 7.231 14.85 7.349 ;
     RECT  2.34 7.321 8.154 7.373 ;
     RECT  14.796 7.349 14.85 7.385 ;
     RECT  8.928 6.953 9.666 7.727 ;
     RECT  10.515 6.809 10.797 7.735 ;
     RECT  2.34 7.373 8.097 7.763 ;
     RECT  8.928 7.727 9.306 7.763 ;
     RECT  0.036 6.619 0.162 7.771 ;
     RECT  11.844 7.349 12.186 7.889 ;
     RECT  10.116 7.735 10.797 7.925 ;
     RECT  0.036 7.771 0.234 7.949 ;
     RECT  2.34 7.763 6.642 7.949 ;
     RECT  21.348 7.321 21.438 7.949 ;
     RECT  15.915 6.941 20.502 7.969 ;
     RECT  8.928 7.763 9.162 8.005 ;
     RECT  10.44 7.925 10.797 8.041 ;
     RECT  2.34 7.949 6.282 8.059 ;
     RECT  12.168 7.889 12.186 8.159 ;
     RECT  15.915 7.969 20.574 8.311 ;
     RECT  2.304 8.059 6.282 8.312 ;
     RECT  21.348 7.949 21.402 8.333 ;
     RECT  8.892 8.005 9.162 8.465 ;
     RECT  10.44 8.041 10.854 8.465 ;
     RECT  10.515 8.465 10.854 8.473 ;
     RECT  0.144 7.949 0.162 8.573 ;
     RECT  15.732 8.311 20.574 8.581 ;
     RECT  13.215 2.413 13.497 8.671 ;
     RECT  7.38 7.763 8.097 8.707 ;
     RECT  8.892 8.465 8.91 8.707 ;
     RECT  21.348 8.333 21.366 8.717 ;
     RECT  12.528 8.671 13.497 8.969 ;
     RECT  15.624 8.581 20.574 8.969 ;
     RECT  14.796 7.385 14.814 9.041 ;
     RECT  7.38 8.707 8.91 9.121 ;
     RECT  10.515 8.473 11.43 9.121 ;
     RECT  2.304 8.312 6.246 9.163 ;
     RECT  7.308 9.121 8.91 9.247 ;
     RECT  2.268 9.163 6.246 9.349 ;
     RECT  7.308 9.247 8.946 9.355 ;
     RECT  2.268 9.349 6.426 9.383 ;
     RECT  13.215 8.969 13.497 9.391 ;
     RECT  2.304 9.383 6.426 9.451 ;
     RECT  7.308 9.355 9.594 9.451 ;
     RECT  13.215 9.391 13.626 9.509 ;
     RECT  15.915 8.969 20.574 9.509 ;
     RECT  17.208 9.509 20.574 9.545 ;
     RECT  10.515 9.121 11.754 9.653 ;
     RECT  17.424 9.545 20.574 9.959 ;
     RECT  2.304 9.451 9.594 10.021 ;
     RECT  13.215 9.509 13.497 10.093 ;
     RECT  2.304 10.021 9.63 10.165 ;
     RECT  10.515 9.653 11.322 10.165 ;
     RECT  2.304 10.165 11.322 10.229 ;
     RECT  12.564 10.093 13.497 10.291 ;
     RECT  14.832 10.057 14.85 10.291 ;
     RECT  15.915 9.509 16.362 10.291 ;
     RECT  12.348 10.291 13.497 10.319 ;
     RECT  14.832 10.291 16.362 10.349 ;
     RECT  20.412 9.959 20.574 10.349 ;
     RECT  15.588 10.349 16.362 10.399 ;
     RECT  15.588 10.399 16.434 10.435 ;
     RECT  15.588 10.435 16.506 10.471 ;
     RECT  17.424 9.959 19.35 10.471 ;
     RECT  15.588 10.471 19.35 10.589 ;
     RECT  12.348 10.319 12.366 10.661 ;
     RECT  15.912 10.589 19.35 10.733 ;
     RECT  2.304 10.229 11.214 10.795 ;
     RECT  13.215 10.319 13.497 10.939 ;
     RECT  2.268 10.795 11.214 10.967 ;
     RECT  15.915 10.733 19.35 11.011 ;
     RECT  12.276 11.011 12.294 11.129 ;
     RECT  14.832 10.349 14.85 11.173 ;
     RECT  15.915 11.011 19.422 11.173 ;
     RECT  14.832 11.173 14.922 11.201 ;
     RECT  20.412 10.349 20.538 11.281 ;
     RECT  0.144 11.245 0.162 11.5 ;
     RECT  20.412 11.281 20.574 11.597 ;
     RECT  14.868 11.201 14.922 11.669 ;
     RECT  15.915 11.173 19.494 11.713 ;
     RECT  20.412 11.597 20.502 11.713 ;
     RECT  0.144 11.5 0.198 11.803 ;
     RECT  13.215 10.939 13.77 11.813 ;
     RECT  0.144 11.803 0.234 11.821 ;
     RECT  15.084 11.713 15.102 11.821 ;
     RECT  15.915 11.713 20.502 11.821 ;
     RECT  21.42 10.075 21.438 11.837 ;
     RECT  12.06 11.551 12.078 11.939 ;
     RECT  0.144 11.821 0.558 11.947 ;
     RECT  15.084 11.821 20.502 11.981 ;
     RECT  0.036 11.947 0.558 11.984 ;
     RECT  12.348 12.253 12.366 12.361 ;
     RECT  15.084 11.981 19.422 12.365 ;
     RECT  15.084 12.365 19.386 12.451 ;
     RECT  12.348 12.361 12.474 12.479 ;
     RECT  12.348 12.479 12.366 12.515 ;
     RECT  14.832 12.451 19.386 12.515 ;
     RECT  14.832 12.515 16.83 12.551 ;
     RECT  0.144 11.984 0.558 12.893 ;
     RECT  20.484 11.981 20.502 12.955 ;
     RECT  20.448 12.955 20.502 13.019 ;
     RECT  17.676 12.515 19.386 13.195 ;
     RECT  20.448 13.019 20.466 13.195 ;
     RECT  15.372 12.551 16.83 13.261 ;
     RECT  17.676 13.195 20.466 13.261 ;
     RECT  15.372 13.261 20.466 13.361 ;
     RECT  0.144 12.893 0.162 13.373 ;
     RECT  14.292 13.441 14.31 13.559 ;
     RECT  15.372 13.361 19.206 13.661 ;
     RECT  15.372 13.661 19.098 13.667 ;
     RECT  2.304 10.967 11.214 13.703 ;
     RECT  2.304 13.703 9.306 13.963 ;
     RECT  19.944 13.361 20.466 13.963 ;
     RECT  2.268 13.963 9.306 14.009 ;
     RECT  15.588 13.667 19.098 14.099 ;
     RECT  21.42 13.531 21.438 14.237 ;
     RECT  19.944 13.963 20.502 14.251 ;
     RECT  19.944 14.251 20.538 14.381 ;
     RECT  15.624 14.099 18.954 14.477 ;
     RECT  2.304 14.009 9.306 14.521 ;
     RECT  10.044 13.703 11.214 14.521 ;
     RECT  14.76 14.635 14.778 14.675 ;
     RECT  15.915 14.477 18.954 14.875 ;
     RECT  19.944 14.381 20.502 14.875 ;
     RECT  2.304 14.521 11.214 15.005 ;
     RECT  15.915 14.875 20.502 15.017 ;
     RECT  2.304 15.005 6.966 15.019 ;
     RECT  2.268 15.019 6.966 15.149 ;
     RECT  14.292 15.025 14.454 15.179 ;
     RECT  15.915 15.017 18.99 15.295 ;
     RECT  14.328 15.179 14.454 15.323 ;
     RECT  14.4 15.323 14.454 15.359 ;
     RECT  21.42 15.259 21.438 15.787 ;
     RECT  15.696 15.295 18.99 15.799 ;
     RECT  2.304 15.149 6.966 15.871 ;
     RECT  7.74 15.005 11.214 15.871 ;
     RECT  19.944 15.017 20.502 15.961 ;
     RECT  15.696 15.799 19.098 15.979 ;
     RECT  19.944 15.961 20.574 15.979 ;
     RECT  21.384 15.787 21.438 15.979 ;
     RECT  19.944 15.979 21.438 15.997 ;
     RECT  15.12 15.979 19.098 16.141 ;
     RECT  19.908 15.997 21.438 16.157 ;
     RECT  0.216 15.787 0.234 16.171 ;
     RECT  0.216 16.171 0.306 16.231 ;
     RECT  0.036 16.231 0.306 16.301 ;
     RECT  15.048 16.141 19.134 16.331 ;
     RECT  21.384 16.157 21.438 16.367 ;
     RECT  21.384 16.367 21.402 16.403 ;
     RECT  14.652 16.363 14.85 16.501 ;
     RECT  14.58 16.501 14.85 16.541 ;
     RECT  19.908 16.157 20.646 16.541 ;
     RECT  2.304 15.871 11.214 16.835 ;
     RECT  0.288 16.301 0.306 16.843 ;
     RECT  13.215 11.813 13.497 16.843 ;
     RECT  12.816 16.843 13.497 16.915 ;
     RECT  15.876 16.331 19.134 16.915 ;
     RECT  20.484 16.541 20.646 17.069 ;
     RECT  15.876 16.915 19.314 17.113 ;
     RECT  15.3 17.113 19.314 17.309 ;
     RECT  12.096 16.915 13.497 17.339 ;
     RECT  20.484 17.069 20.574 17.371 ;
     RECT  0.288 16.843 0.558 17.405 ;
     RECT  21.42 17.653 21.438 17.693 ;
     RECT  15.3 17.309 19.134 17.725 ;
     RECT  2.304 16.835 10.854 17.752 ;
     RECT  20.196 17.371 20.574 17.933 ;
     RECT  20.196 17.933 20.502 17.987 ;
     RECT  0.144 17.455 0.162 18.029 ;
     RECT  15.156 17.725 19.134 18.031 ;
     RECT  14.832 18.031 19.242 18.193 ;
     RECT  12.096 17.339 12.114 18.301 ;
     RECT  12.096 18.301 12.33 18.419 ;
     RECT  14.832 18.193 19.314 18.491 ;
     RECT  0.216 18.379 0.234 18.509 ;
     RECT  2.268 17.752 10.854 18.527 ;
     RECT  15.3 18.491 19.314 18.667 ;
     RECT  2.304 18.527 10.854 18.725 ;
     RECT  15.3 18.667 19.422 18.763 ;
     RECT  20.448 17.987 20.502 18.763 ;
     RECT  15.3 18.763 20.502 18.769 ;
     RECT  15.3 18.769 20.538 18.869 ;
     RECT  12.096 18.419 12.114 18.931 ;
     RECT  2.304 18.725 5.454 18.995 ;
     RECT  6.192 18.725 10.854 19.039 ;
     RECT  11.592 18.931 12.114 19.039 ;
     RECT  6.192 19.039 12.114 19.139 ;
     RECT  15.3 18.869 19.422 19.229 ;
     RECT  21.384 19.237 21.402 19.291 ;
     RECT  15.372 19.229 19.422 19.337 ;
     RECT  11.592 19.139 12.114 19.373 ;
     RECT  15.372 19.337 18.99 19.373 ;
     RECT  0.144 19.237 0.162 19.387 ;
     RECT  21.384 19.291 21.438 19.409 ;
     RECT  0.144 19.387 0.234 19.531 ;
     RECT  6.192 19.139 10.854 19.531 ;
     RECT  21.384 19.409 21.402 19.565 ;
     RECT  6.156 19.531 10.854 19.613 ;
     RECT  0.036 19.531 0.234 19.643 ;
     RECT  6.156 19.613 10.797 19.643 ;
     RECT  13.215 17.339 13.497 19.651 ;
     RECT  0.144 19.643 0.234 19.661 ;
     RECT  13.215 19.651 14.094 19.769 ;
     RECT  7.668 19.643 10.797 19.841 ;
     RECT  2.304 18.995 5.397 19.849 ;
     RECT  6.156 19.643 6.93 19.849 ;
     RECT  7.74 19.841 10.797 19.901 ;
     RECT  2.304 19.849 6.93 19.913 ;
     RECT  20.484 18.869 20.538 19.915 ;
     RECT  19.908 19.915 20.538 20.119 ;
     RECT  0.144 19.661 0.162 20.189 ;
     RECT  15.408 19.373 18.99 20.191 ;
     RECT  7.815 19.901 10.797 20.333 ;
     RECT  15.408 20.191 19.17 20.345 ;
     RECT  7.815 20.333 9.738 20.381 ;
     RECT  10.476 20.333 10.797 20.635 ;
     RECT  15.408 20.345 19.098 20.635 ;
     RECT  14.22 20.587 14.238 20.659 ;
     RECT  15.084 20.635 19.098 20.659 ;
     RECT  2.304 19.913 6.858 20.695 ;
     RECT  13.215 19.769 13.497 20.821 ;
     RECT  14.22 20.659 19.098 20.821 ;
     RECT  10.476 20.635 10.962 20.827 ;
     RECT  13.215 20.821 19.098 20.885 ;
     RECT  2.304 20.695 7.002 20.893 ;
     RECT  12.096 19.373 12.114 20.893 ;
     RECT  13.215 20.885 19.062 20.921 ;
     RECT  10.476 20.827 11.07 20.957 ;
     RECT  19.908 20.119 20.574 20.957 ;
     RECT  2.304 20.893 7.038 20.971 ;
     RECT  7.815 20.381 9.666 20.971 ;
     RECT  14.904 20.921 19.062 21.005 ;
     RECT  2.304 20.971 9.666 21.067 ;
     RECT  2.268 21.067 9.666 21.127 ;
     RECT  10.476 20.957 10.926 21.127 ;
     RECT  11.988 20.893 12.114 21.199 ;
     RECT  11.664 21.199 12.114 21.389 ;
     RECT  20.484 20.957 20.574 21.433 ;
     RECT  2.268 21.127 10.926 21.569 ;
     RECT  20.484 21.433 20.61 21.725 ;
     RECT  13.215 20.921 13.842 21.901 ;
     RECT  2.268 21.569 10.797 21.965 ;
     RECT  21.42 20.923 21.438 22.037 ;
     RECT  15.084 21.005 19.062 22.081 ;
     RECT  20.484 21.725 20.574 22.171 ;
     RECT  2.268 21.965 8.982 22.205 ;
     RECT  13.215 21.901 14.022 22.207 ;
     RECT  15.084 22.081 19.098 22.207 ;
     RECT  13.215 22.207 19.098 22.441 ;
     RECT  9.72 21.965 10.797 22.585 ;
     RECT  13.215 22.441 19.17 22.648 ;
     RECT  2.304 22.205 8.982 22.747 ;
     RECT  9.72 22.585 10.854 22.747 ;
     RECT  13.215 22.648 19.206 22.748 ;
     RECT  20.448 22.171 20.574 22.783 ;
     RECT  13.215 22.748 19.17 22.811 ;
     RECT  0.144 22.711 0.162 22.829 ;
     RECT  20.448 22.783 20.61 22.939 ;
     RECT  2.304 22.747 10.854 23.161 ;
     RECT  20.412 22.939 20.61 23.179 ;
     RECT  13.215 22.811 19.026 23.279 ;
     RECT  19.908 23.179 20.61 23.279 ;
     RECT  2.304 23.161 10.926 23.351 ;
     RECT  15.084 23.279 19.026 23.387 ;
     RECT  19.944 23.279 20.61 23.501 ;
     RECT  0.54 23.161 0.558 23.665 ;
     RECT  2.304 23.351 10.854 23.803 ;
     RECT  15.084 23.387 18.99 23.819 ;
     RECT  2.268 23.803 10.854 23.963 ;
     RECT  21.42 23.899 21.438 24.097 ;
     RECT  20.412 23.501 20.61 24.197 ;
     RECT  20.448 24.197 20.61 24.221 ;
     RECT  20.448 24.221 20.538 24.269 ;
     RECT  2.304 23.963 10.854 24.331 ;
     RECT  2.304 24.331 10.926 24.503 ;
     RECT  15.408 23.819 18.99 24.637 ;
     RECT  15.336 24.637 18.99 24.709 ;
     RECT  12.096 21.389 12.114 24.745 ;
     RECT  13.215 23.279 13.77 24.745 ;
     RECT  0.144 23.665 0.558 24.781 ;
     RECT  14.832 24.709 18.99 24.781 ;
     RECT  14.832 24.781 19.134 24.935 ;
     RECT  20.448 24.269 20.502 24.943 ;
     RECT  14.832 24.935 19.098 24.971 ;
     RECT  0.036 24.781 0.558 24.989 ;
     RECT  12.096 24.745 13.77 25.007 ;
     RECT  0.54 24.989 0.558 25.133 ;
     RECT  20.412 24.943 20.502 25.195 ;
     RECT  12.096 25.007 12.15 25.313 ;
     RECT  19.908 25.195 20.502 25.339 ;
     RECT  19.872 25.339 20.502 25.547 ;
     RECT  19.908 25.547 20.502 25.619 ;
     RECT  2.304 24.503 10.854 25.825 ;
     RECT  15.408 24.971 19.098 25.951 ;
     RECT  20.196 25.619 20.502 25.963 ;
     RECT  2.232 25.825 10.854 25.997 ;
     RECT  21.384 24.097 21.438 26.095 ;
     RECT  21.348 26.095 21.438 26.381 ;
     RECT  2.268 25.997 10.854 26.395 ;
     RECT  21.384 26.381 21.438 26.519 ;
     RECT  15.408 25.951 19.17 26.527 ;
     RECT  20.196 25.963 20.538 26.563 ;
     RECT  2.268 26.395 10.89 26.573 ;
     RECT  14.832 26.527 19.17 26.599 ;
     RECT  13.215 25.007 13.77 26.671 ;
     RECT  14.796 26.599 19.17 26.671 ;
     RECT  20.196 26.563 20.574 26.671 ;
     RECT  21.384 26.519 21.402 26.969 ;
     RECT  13.215 26.671 20.574 27.005 ;
     RECT  13.215 27.005 20.538 27.059 ;
     RECT  14.796 27.059 20.538 27.131 ;
     RECT  2.268 26.573 10.854 27.329 ;
     RECT  2.268 27.329 10.797 27.365 ;
     RECT  14.976 27.131 20.538 27.533 ;
     RECT  12.132 25.313 12.15 27.679 ;
     RECT  13.215 27.059 13.986 27.679 ;
     RECT  12.132 27.679 13.986 27.985 ;
     RECT  14.976 27.533 20.502 27.985 ;
     RECT  2.304 27.365 10.797 28.123 ;
     RECT  12.132 27.985 20.502 28.247 ;
     RECT  2.304 28.123 10.854 28.253 ;
     RECT  13.068 28.247 20.502 28.409 ;
     RECT  13.068 28.409 13.77 28.679 ;
     RECT  21.42 27.751 21.438 28.795 ;
     RECT  0.144 27.913 0.162 28.891 ;
     RECT  0.144 28.891 0.234 28.987 ;
     RECT  2.304 28.253 10.797 29.021 ;
     RECT  14.868 28.409 20.502 29.165 ;
     RECT  21.384 28.795 21.438 29.219 ;
     RECT  20.484 29.165 20.502 29.263 ;
     RECT  21.384 29.219 21.402 29.309 ;
     RECT  14.868 29.165 19.314 29.489 ;
     RECT  20.484 29.263 20.574 29.549 ;
     RECT  2.304 29.021 9.774 29.633 ;
     RECT  9.756 29.633 9.774 29.767 ;
     RECT  10.515 29.021 10.797 29.767 ;
     RECT  14.868 29.489 14.886 29.767 ;
     RECT  2.304 29.633 8.91 29.789 ;
     RECT  14.796 29.767 14.886 29.831 ;
     RECT  0.036 28.987 0.234 29.867 ;
     RECT  14.796 29.831 14.814 29.867 ;
     RECT  0.144 29.867 0.234 29.885 ;
     RECT  20.484 29.549 20.502 30.136 ;
     RECT  0.144 29.885 0.162 30.317 ;
     RECT  15.915 29.489 19.314 30.343 ;
     RECT  20.448 30.136 20.502 30.343 ;
     RECT  15.915 30.343 20.502 30.557 ;
     RECT  20.16 30.557 20.502 30.649 ;
     RECT  15.915 30.557 19.386 30.721 ;
     RECT  21.384 30.763 21.402 30.893 ;
     RECT  2.304 29.789 8.838 30.955 ;
     RECT  2.268 30.955 8.982 31.051 ;
     RECT  9.756 29.767 10.797 31.051 ;
     RECT  15.732 30.721 19.386 31.081 ;
     RECT  2.268 31.051 10.797 31.181 ;
     RECT  15.66 31.081 19.386 31.181 ;
     RECT  15.66 31.181 19.026 31.195 ;
     RECT  20.16 30.649 20.538 31.289 ;
     RECT  15.516 31.195 19.026 31.415 ;
     RECT  15.516 31.415 18.99 31.459 ;
     RECT  13.215 28.679 13.77 31.483 ;
     RECT  0.216 30.763 0.234 31.565 ;
     RECT  15.372 31.459 18.99 31.649 ;
     RECT  21.42 31.081 21.438 31.729 ;
     RECT  12.132 28.247 12.15 31.801 ;
     RECT  13.215 31.483 13.986 31.801 ;
     RECT  15.372 31.649 18.897 31.801 ;
     RECT  15.192 31.801 18.897 31.891 ;
     RECT  12.132 31.801 13.986 31.919 ;
     RECT  14.94 31.891 18.897 31.949 ;
     RECT  20.448 31.289 20.538 31.999 ;
     RECT  20.448 31.999 20.574 32.189 ;
     RECT  12.924 31.919 13.77 32.297 ;
     RECT  2.304 31.181 10.797 32.395 ;
     RECT  14.976 31.949 18.897 32.431 ;
     RECT  2.268 32.395 10.797 32.491 ;
     RECT  2.268 32.491 10.998 32.531 ;
     RECT  2.268 32.531 10.797 32.567 ;
     RECT  21.384 31.729 21.438 32.603 ;
     RECT  14.976 32.431 19.098 32.881 ;
     RECT  14.976 32.881 19.422 32.999 ;
     RECT  0.216 32.923 0.234 33.067 ;
     RECT  15.915 32.999 19.422 33.101 ;
     RECT  0.144 33.067 0.378 33.151 ;
     RECT  12.132 31.919 12.15 33.305 ;
     RECT  2.304 32.567 10.797 33.313 ;
     RECT  0.036 33.151 0.378 33.421 ;
     RECT  13.215 32.297 13.77 33.421 ;
     RECT  20.484 32.189 20.574 33.437 ;
     RECT  14.976 32.999 15.102 33.547 ;
     RECT  0.036 33.421 0.558 33.584 ;
     RECT  20.484 33.437 20.502 33.619 ;
     RECT  14.904 33.547 15.102 33.719 ;
     RECT  2.304 33.313 10.854 33.817 ;
     RECT  21.384 32.603 21.402 33.821 ;
     RECT  2.304 33.817 10.962 33.917 ;
     RECT  15.915 33.101 19.062 34.195 ;
     RECT  2.304 33.917 10.926 34.205 ;
     RECT  19.944 33.619 20.502 34.231 ;
     RECT  13.032 33.421 13.77 34.349 ;
     RECT  13.032 34.349 13.497 34.357 ;
     RECT  12.492 34.357 13.497 34.393 ;
     RECT  15.48 34.195 19.062 34.465 ;
     RECT  15.48 34.465 19.134 34.501 ;
     RECT  14.868 34.501 19.134 34.555 ;
     RECT  19.908 34.231 20.502 34.555 ;
     RECT  12.06 34.393 13.497 34.591 ;
     RECT  14.868 34.555 20.502 34.591 ;
     RECT  14.868 34.591 20.538 34.771 ;
     RECT  11.988 34.591 13.497 34.772 ;
     RECT  2.304 34.205 9.126 34.799 ;
     RECT  14.832 34.771 20.538 34.861 ;
     RECT  12.024 34.772 13.497 34.961 ;
     RECT  0.54 33.584 0.558 34.973 ;
     RECT  2.304 34.799 9.054 35.005 ;
     RECT  2.268 35.005 9.054 35.021 ;
     RECT  14.832 34.861 20.574 35.041 ;
     RECT  14.508 35.041 20.574 35.069 ;
     RECT  14.508 35.069 14.85 35.231 ;
     RECT  15.732 35.069 20.574 35.311 ;
     RECT  14.508 35.231 14.706 35.429 ;
     RECT  9.864 34.205 10.926 35.437 ;
     RECT  9.864 35.437 10.998 35.741 ;
     RECT  15.732 35.311 20.61 35.741 ;
     RECT  2.268 35.021 8.874 35.744 ;
     RECT  14.4 35.509 14.49 35.771 ;
     RECT  21.384 35.239 21.402 35.779 ;
     RECT  10.188 35.741 10.998 35.803 ;
     RECT  2.304 35.744 8.874 35.815 ;
     RECT  15.732 35.741 20.502 35.837 ;
     RECT  10.188 35.803 11.106 35.879 ;
     RECT  15.732 35.837 19.386 36.085 ;
     RECT  10.188 35.879 10.926 36.149 ;
     RECT  20.484 35.837 20.502 36.239 ;
     RECT  21.384 35.779 21.438 36.365 ;
     RECT  15.408 36.085 19.386 36.391 ;
     RECT  2.304 35.815 9.45 36.481 ;
     RECT  10.188 36.149 10.89 36.481 ;
     RECT  12.672 34.961 13.497 36.481 ;
     RECT  14.4 35.771 14.418 36.481 ;
     RECT  12.672 36.481 14.418 36.509 ;
     RECT  0.54 36.625 0.558 36.715 ;
     RECT  15.372 36.391 19.386 36.749 ;
     RECT  11.844 36.481 11.862 36.763 ;
     RECT  12.672 36.509 14.022 36.763 ;
     RECT  11.844 36.763 14.022 36.815 ;
     RECT  15.372 36.749 19.206 36.859 ;
     RECT  20.52 36.853 20.538 36.893 ;
     RECT  12.492 36.815 14.022 37.085 ;
     RECT  0.216 36.715 0.558 37.133 ;
     RECT  21.42 36.365 21.438 37.133 ;
     RECT  2.304 36.481 10.89 37.165 ;
     RECT  15.264 36.859 19.206 37.165 ;
     RECT  14.868 37.165 19.206 37.291 ;
     RECT  0.216 37.133 0.234 37.327 ;
     RECT  12.6 37.085 14.022 37.327 ;
     RECT  0.036 37.327 0.234 37.355 ;
     RECT  0.036 37.355 0.054 37.373 ;
     RECT  12.6 37.327 14.058 37.391 ;
     RECT  14.832 37.291 19.206 37.421 ;
     RECT  2.268 37.165 10.89 37.471 ;
     RECT  14.976 37.421 19.206 37.483 ;
     RECT  20.484 37.195 20.502 37.483 ;
     RECT  12.672 37.391 14.058 37.589 ;
     RECT  21.384 37.435 21.402 37.613 ;
     RECT  14.976 37.483 20.502 37.757 ;
     RECT  19.944 37.757 20.502 38.011 ;
     RECT  2.268 37.471 10.926 38.209 ;
     RECT  21.42 37.867 21.438 38.237 ;
     RECT  19.944 38.011 20.538 38.381 ;
     RECT  12.672 37.589 13.986 38.515 ;
     RECT  2.268 38.209 10.962 38.573 ;
     RECT  20.34 38.381 20.538 38.579 ;
     RECT  14.976 37.757 19.098 38.587 ;
     RECT  12.492 38.515 13.986 38.677 ;
     RECT  2.268 38.573 8.622 38.705 ;
     RECT  12.348 38.677 13.986 38.713 ;
     RECT  12.348 38.713 14.058 38.765 ;
     RECT  0.036 38.551 0.054 38.875 ;
     RECT  9.36 38.573 10.962 38.911 ;
     RECT  21.384 38.875 21.402 38.971 ;
     RECT  12.672 38.765 14.058 38.975 ;
     RECT  0.036 38.875 0.234 39.005 ;
     RECT  9.36 38.911 11.034 39.053 ;
     RECT  21.384 38.971 21.582 39.083 ;
     RECT  2.304 38.705 8.622 39.325 ;
     RECT  9.36 39.053 10.962 39.325 ;
     RECT  14.976 38.587 19.386 39.361 ;
     RECT  14.94 39.361 19.386 39.479 ;
     RECT  0.144 39.005 0.162 39.533 ;
     RECT  2.304 39.325 10.962 39.533 ;
     RECT  20.484 38.579 20.538 39.533 ;
     RECT  15.228 39.479 19.386 39.749 ;
     RECT  15.408 39.749 19.386 39.785 ;
     RECT  21.384 39.083 21.438 39.869 ;
     RECT  12.672 38.975 13.95 39.883 ;
     RECT  2.304 39.533 10.89 39.979 ;
     RECT  12.492 39.883 13.95 39.991 ;
     RECT  15.768 39.785 19.386 39.991 ;
     RECT  2.268 39.979 10.89 40.055 ;
     RECT  12.492 39.991 14.31 40.091 ;
     RECT  12.672 40.091 14.31 40.199 ;
     RECT  15.768 39.991 19.422 40.301 ;
     RECT  12.708 40.199 14.31 40.325 ;
     RECT  21.42 39.869 21.438 40.397 ;
     RECT  0.54 40.369 0.558 40.405 ;
     RECT  2.304 40.055 10.89 40.531 ;
     RECT  14.256 40.325 14.31 40.531 ;
     RECT  0.144 40.405 0.558 40.541 ;
     RECT  20.484 39.533 20.502 40.603 ;
     RECT  0.216 40.541 0.558 40.637 ;
     RECT  14.256 40.531 14.742 40.639 ;
     RECT  15.768 40.301 19.35 40.639 ;
     RECT  20.448 40.603 20.502 40.711 ;
     RECT  14.256 40.639 19.35 40.781 ;
     RECT  2.304 40.531 10.962 40.873 ;
     RECT  0.216 40.637 0.234 41.021 ;
     RECT  14.256 40.781 19.17 41.099 ;
     RECT  20.412 40.711 20.502 41.275 ;
     RECT  2.304 40.873 10.998 41.377 ;
     RECT  19.908 41.275 20.502 41.413 ;
     RECT  14.868 41.099 19.17 41.441 ;
     RECT  15.372 41.441 19.17 41.521 ;
     RECT  19.908 41.413 20.538 41.521 ;
     RECT  2.268 41.377 10.998 41.549 ;
     RECT  15.372 41.521 20.538 41.549 ;
     RECT  2.304 41.549 10.998 41.909 ;
     RECT  2.304 41.909 10.962 42.089 ;
     RECT  2.304 42.089 10.797 42.215 ;
     RECT  0.18 42.223 0.198 42.295 ;
     RECT  0.144 42.295 0.198 42.379 ;
     RECT  15.372 41.549 20.502 42.601 ;
     RECT  9.972 42.215 10.797 42.961 ;
     RECT  9.972 42.961 10.89 43.033 ;
     RECT  15.372 42.601 20.61 43.105 ;
     RECT  21.42 41.659 21.438 43.141 ;
     RECT  15.3 43.105 20.61 43.181 ;
     RECT  0.144 42.379 0.234 43.195 ;
     RECT  12.708 40.325 13.497 43.231 ;
     RECT  21.384 43.141 21.438 43.231 ;
     RECT  0.144 43.195 0.306 43.267 ;
     RECT  2.304 42.215 9.234 43.267 ;
     RECT  9.972 43.033 10.998 43.267 ;
     RECT  0.036 43.267 0.306 43.295 ;
     RECT  0.036 43.295 0.234 43.325 ;
     RECT  20.484 43.181 20.61 43.325 ;
     RECT  12.708 43.231 13.842 43.375 ;
     RECT  2.304 43.267 10.998 43.673 ;
     RECT  12.384 43.375 13.842 43.799 ;
     RECT  21.348 43.231 21.438 43.805 ;
     RECT  12.384 43.799 12.402 43.901 ;
     RECT  13.176 43.799 13.842 43.907 ;
     RECT  20.484 43.325 20.538 43.949 ;
     RECT  15.3 43.181 19.314 43.951 ;
     RECT  14.652 43.951 19.314 44.069 ;
     RECT  14.832 44.069 19.314 44.141 ;
     RECT  15.3 44.141 19.314 44.185 ;
     RECT  20.484 43.949 20.502 44.221 ;
     RECT  2.304 43.673 9.198 44.299 ;
     RECT  20.448 44.221 20.502 44.333 ;
     RECT  2.268 44.299 9.198 44.375 ;
     RECT  2.304 44.375 9.198 44.617 ;
     RECT  9.972 43.673 10.998 44.617 ;
     RECT  2.304 44.617 10.998 44.689 ;
     RECT  15.3 44.185 19.422 44.717 ;
     RECT  20.484 44.333 20.502 44.725 ;
     RECT  2.304 44.689 11.034 44.765 ;
     RECT  0.54 44.419 0.558 44.779 ;
     RECT  2.304 44.765 10.962 44.879 ;
     RECT  0.216 44.779 0.558 44.887 ;
     RECT  20.484 44.725 20.538 44.923 ;
     RECT  15.3 44.717 19.17 45.031 ;
     RECT  0.144 44.887 0.558 45.101 ;
     RECT  14.832 45.031 19.17 45.149 ;
     RECT  0.144 45.101 0.234 45.197 ;
     RECT  20.484 44.923 20.574 45.197 ;
     RECT  0.216 45.197 0.234 45.533 ;
     RECT  14.94 45.149 19.17 45.547 ;
     RECT  2.304 44.879 10.926 45.769 ;
     RECT  14.94 45.547 19.386 45.797 ;
     RECT  20.484 45.197 20.538 45.821 ;
     RECT  2.304 45.769 10.998 45.869 ;
     RECT  20.484 45.821 20.502 46.003 ;
     RECT  14.94 45.797 19.134 46.273 ;
     RECT  19.908 46.003 20.502 46.499 ;
     RECT  2.304 45.869 10.962 46.535 ;
     RECT  19.944 46.499 20.502 46.589 ;
     RECT  19.98 46.589 20.502 46.733 ;
     RECT  21.42 43.805 21.438 46.769 ;
     RECT  20.16 46.733 20.502 46.795 ;
     RECT  14.832 46.273 19.134 46.805 ;
     RECT  20.16 46.795 20.538 46.849 ;
     RECT  21.384 46.939 21.402 47.069 ;
     RECT  20.16 46.849 20.574 47.116 ;
     RECT  14.832 46.805 19.098 47.119 ;
     RECT  14.796 47.119 19.098 47.219 ;
     RECT  2.304 46.535 10.926 47.425 ;
     RECT  20.16 47.116 20.61 47.501 ;
     RECT  15.156 47.219 19.098 47.695 ;
     RECT  2.232 47.425 10.926 47.731 ;
     RECT  15.156 47.695 19.314 47.731 ;
     RECT  20.16 47.501 20.538 47.731 ;
     RECT  2.232 47.731 10.962 47.821 ;
     RECT  2.232 47.821 11.43 47.857 ;
     RECT  2.196 47.857 11.43 47.957 ;
     RECT  21.42 47.857 21.438 47.981 ;
     RECT  15.156 47.731 20.538 48.127 ;
     RECT  14.832 48.127 20.538 48.227 ;
     RECT  13.215 43.907 13.842 48.505 ;
     RECT  2.304 47.957 11.43 48.659 ;
     RECT  15.408 48.227 20.538 48.749 ;
     RECT  19.872 48.749 20.538 48.989 ;
     RECT  19.872 48.989 20.502 49.199 ;
     RECT  19.944 49.199 20.502 49.229 ;
     RECT  0.144 47.155 0.162 49.373 ;
     RECT  12.06 49.351 12.078 49.505 ;
     RECT  21.42 49.483 21.438 49.513 ;
     RECT  2.304 48.659 10.926 49.621 ;
     RECT  13.215 48.505 14.382 49.621 ;
     RECT  15.408 48.749 19.098 49.621 ;
     RECT  2.304 49.621 10.998 49.723 ;
     RECT  2.268 49.723 10.998 49.775 ;
     RECT  13.215 49.621 19.098 49.775 ;
     RECT  13.215 49.775 16.758 49.919 ;
     RECT  21.384 49.513 21.438 49.919 ;
     RECT  20.448 49.229 20.502 49.963 ;
     RECT  2.304 49.775 10.998 50.081 ;
     RECT  2.304 50.081 10.854 50.153 ;
     RECT  17.604 49.775 19.098 50.251 ;
     RECT  19.908 49.963 20.502 50.251 ;
     RECT  17.604 50.251 20.502 50.381 ;
     RECT  15.156 49.919 16.758 50.521 ;
     RECT  17.604 50.381 19.17 50.521 ;
     RECT  19.908 50.381 20.502 50.521 ;
     RECT  13.215 49.919 14.202 50.549 ;
     RECT  15.156 50.521 19.17 50.549 ;
     RECT  15.156 50.549 15.174 50.621 ;
     RECT  15.915 50.549 19.17 50.621 ;
     RECT  13.215 50.549 13.95 50.701 ;
     RECT  19.908 50.521 20.646 50.729 ;
     RECT  13.104 50.701 13.95 50.819 ;
     RECT  20.448 50.729 20.646 51.005 ;
     RECT  15.915 50.621 19.098 51.125 ;
     RECT  2.304 50.153 10.797 51.133 ;
     RECT  0.144 51.241 0.162 51.293 ;
     RECT  20.448 51.005 20.538 51.293 ;
     RECT  14.868 50.971 14.886 51.709 ;
     RECT  15.915 51.125 19.026 51.709 ;
     RECT  0.216 51.643 0.234 51.773 ;
     RECT  14.868 51.709 19.026 51.781 ;
     RECT  21.42 49.919 21.438 51.781 ;
     RECT  2.304 51.133 10.854 51.883 ;
     RECT  19.944 51.511 20.25 52.123 ;
     RECT  2.268 51.883 10.854 52.141 ;
     RECT  19.944 52.123 20.502 52.213 ;
     RECT  2.268 52.141 10.926 52.219 ;
     RECT  14.796 51.781 19.026 52.219 ;
     RECT  19.944 52.213 20.538 52.219 ;
     RECT  13.215 50.819 13.95 52.267 ;
     RECT  14.796 52.219 20.538 52.267 ;
     RECT  2.268 52.219 10.962 52.397 ;
     RECT  13.215 52.267 20.538 52.439 ;
     RECT  2.304 52.397 10.962 52.445 ;
     RECT  21.384 51.781 21.438 52.637 ;
     RECT  12.348 52.411 12.366 52.709 ;
     RECT  0.216 52.795 0.234 52.825 ;
     RECT  14.796 52.439 14.814 52.853 ;
     RECT  11.592 52.753 11.61 52.889 ;
     RECT  13.215 52.439 13.95 52.951 ;
     RECT  0.036 52.825 0.234 53.021 ;
     RECT  15.696 52.439 20.538 53.021 ;
     RECT  2.304 52.445 10.797 53.221 ;
     RECT  12.6 52.951 13.95 53.249 ;
     RECT  14.832 53.221 14.922 53.293 ;
     RECT  15.696 53.021 19.422 53.293 ;
     RECT  20.52 53.021 20.538 53.293 ;
     RECT  12.78 53.249 13.95 53.519 ;
     RECT  14.832 53.293 19.422 53.519 ;
     RECT  20.52 53.293 20.574 53.549 ;
     RECT  20.52 53.549 20.538 53.693 ;
     RECT  14.94 53.519 19.422 53.789 ;
     RECT  2.304 53.221 10.854 53.797 ;
     RECT  2.304 53.797 11.286 53.981 ;
     RECT  21.42 52.637 21.438 53.995 ;
     RECT  6.948 53.981 11.286 54.059 ;
     RECT  15.084 53.789 19.422 54.067 ;
     RECT  21.384 53.995 21.438 54.239 ;
     RECT  0.144 54.103 0.162 54.317 ;
     RECT  12.096 54.103 12.114 54.373 ;
     RECT  15.084 54.067 20.502 54.571 ;
     RECT  12.024 54.373 12.114 54.599 ;
     RECT  21.384 54.239 21.402 54.671 ;
     RECT  15.084 54.571 20.61 54.701 ;
     RECT  2.304 53.981 6.138 54.877 ;
     RECT  6.948 54.059 10.797 54.877 ;
     RECT  13.215 53.519 13.95 54.877 ;
     RECT  13.215 54.877 14.238 54.905 ;
     RECT  2.304 54.877 10.797 54.949 ;
     RECT  14.22 54.905 14.238 54.985 ;
     RECT  15.084 54.701 20.538 54.985 ;
     RECT  14.22 54.985 20.538 55.049 ;
     RECT  2.304 54.949 10.926 55.139 ;
     RECT  14.22 55.049 19.422 55.175 ;
     RECT  14.796 55.175 19.422 55.247 ;
     RECT  14.796 55.247 14.85 55.283 ;
     RECT  0.54 55.255 0.558 55.325 ;
     RECT  15.588 55.247 19.422 55.565 ;
     RECT  20.412 55.049 20.538 55.679 ;
     RECT  14.796 55.283 14.814 55.949 ;
     RECT  15.588 55.565 19.134 56.011 ;
     RECT  21.42 55.771 21.438 56.059 ;
     RECT  2.304 55.139 10.797 56.065 ;
     RECT  2.268 56.065 10.797 56.189 ;
     RECT  13.215 54.905 13.497 56.191 ;
     RECT  13.104 56.191 13.497 56.237 ;
     RECT  14.832 56.011 19.134 56.291 ;
     RECT  21.384 56.059 21.438 56.299 ;
     RECT  21.384 56.299 21.582 56.333 ;
     RECT  21.42 56.333 21.582 56.489 ;
     RECT  2.304 56.189 10.797 57.001 ;
     RECT  15.192 56.291 19.134 57.029 ;
     RECT  20.448 55.679 20.538 57.073 ;
     RECT  0.54 56.875 0.558 57.101 ;
     RECT  15.915 57.029 19.134 57.181 ;
     RECT  19.944 57.073 20.538 57.181 ;
     RECT  21.42 56.489 21.438 57.298 ;
     RECT  21.384 57.298 21.438 57.403 ;
     RECT  15.915 57.181 20.538 57.451 ;
     RECT  21.384 57.403 21.582 57.524 ;
     RECT  21.384 57.524 21.402 57.533 ;
     RECT  2.304 57.001 10.854 57.721 ;
     RECT  13.215 56.237 13.497 57.811 ;
     RECT  15.915 57.451 20.574 57.821 ;
     RECT  14.832 57.541 14.85 57.847 ;
     RECT  15.915 57.821 20.538 57.847 ;
     RECT  14.832 57.847 20.538 57.965 ;
     RECT  19.908 57.965 20.538 58.019 ;
     RECT  12.96 57.811 13.497 58.109 ;
     RECT  0.54 57.991 0.558 58.117 ;
     RECT  2.268 57.721 10.926 58.117 ;
     RECT  2.232 58.117 10.926 58.217 ;
     RECT  14.832 57.965 19.062 58.253 ;
     RECT  0.144 58.117 0.558 58.349 ;
     RECT  20.484 58.019 20.538 58.349 ;
     RECT  2.304 58.217 10.926 58.649 ;
     RECT  0.144 58.349 0.198 58.733 ;
     RECT  20.484 58.349 20.502 58.927 ;
     RECT  15.336 58.253 19.062 58.939 ;
     RECT  15.336 58.939 19.098 59.233 ;
     RECT  0.18 58.733 0.198 59.357 ;
     RECT  14.796 59.233 19.098 59.459 ;
     RECT  14.832 59.459 19.098 59.575 ;
     RECT  2.304 58.649 10.854 59.701 ;
     RECT  2.304 59.701 10.926 59.837 ;
     RECT  14.832 59.575 19.422 59.947 ;
     RECT  20.448 58.927 20.502 59.947 ;
     RECT  14.832 59.947 20.502 59.999 ;
     RECT  15.915 59.999 20.502 60.125 ;
     RECT  21.42 58.699 21.438 60.277 ;
     RECT  13.215 58.109 13.497 60.313 ;
     RECT  15.915 60.125 19.962 60.377 ;
     RECT  14.832 59.999 14.85 60.539 ;
     RECT  0.54 60.385 0.558 60.605 ;
     RECT  2.304 59.837 10.854 60.655 ;
     RECT  21.384 60.277 21.438 60.691 ;
     RECT  2.304 60.655 10.89 60.719 ;
     RECT  15.915 60.377 19.098 60.853 ;
     RECT  15.732 60.853 19.098 60.893 ;
     RECT  15.876 60.893 19.098 61.195 ;
     RECT  13.104 60.313 13.497 61.231 ;
     RECT  15.876 61.195 19.134 61.231 ;
     RECT  19.908 60.377 19.962 61.231 ;
     RECT  15.876 61.231 19.962 61.339 ;
     RECT  13.032 61.231 13.497 61.349 ;
     RECT  21.312 60.691 21.438 61.517 ;
     RECT  14.94 61.123 14.958 61.591 ;
     RECT  15.876 61.339 20.502 61.619 ;
     RECT  15.876 61.619 19.926 61.727 ;
     RECT  14.832 61.591 14.958 61.771 ;
     RECT  14.76 61.771 14.958 61.861 ;
     RECT  15.876 61.727 19.422 61.861 ;
     RECT  21.348 61.517 21.438 61.963 ;
     RECT  2.304 60.719 10.854 62.069 ;
     RECT  2.304 62.069 9.198 62.107 ;
     RECT  14.76 61.861 19.422 62.159 ;
     RECT  21.348 61.963 21.582 62.159 ;
     RECT  13.215 61.349 13.497 62.203 ;
     RECT  0.54 62.005 0.558 62.237 ;
     RECT  15.696 62.159 19.422 62.237 ;
     RECT  13.215 62.203 13.59 62.311 ;
     RECT  20.52 62.347 20.538 62.491 ;
     RECT  13.215 62.311 13.698 62.573 ;
     RECT  20.52 62.491 20.574 62.587 ;
     RECT  19.944 62.587 20.574 62.609 ;
     RECT  15.696 62.237 19.206 62.771 ;
     RECT  11.736 62.707 11.754 62.779 ;
     RECT  2.268 62.107 9.198 62.815 ;
     RECT  9.972 62.069 10.854 62.815 ;
     RECT  11.664 62.779 11.754 62.851 ;
     RECT  11.592 62.851 12.042 62.969 ;
     RECT  14.796 62.159 14.922 62.969 ;
     RECT  14.832 62.969 14.922 62.971 ;
     RECT  15.696 62.771 19.098 62.971 ;
     RECT  14.832 62.971 19.098 63.005 ;
     RECT  12.024 62.969 12.042 63.013 ;
     RECT  19.944 62.609 20.502 63.112 ;
     RECT  12.024 63.013 12.366 63.113 ;
     RECT  14.832 63.005 19.062 63.113 ;
     RECT  21.348 62.159 21.438 63.113 ;
     RECT  15.408 63.113 19.062 63.239 ;
     RECT  2.268 62.815 10.854 63.311 ;
     RECT  12.348 63.113 12.366 63.481 ;
     RECT  2.268 63.311 9.018 63.739 ;
     RECT  2.232 63.739 9.018 63.815 ;
     RECT  12.348 63.481 12.474 63.815 ;
     RECT  15.912 63.239 19.062 63.859 ;
     RECT  19.908 63.112 20.502 63.859 ;
     RECT  13.215 62.573 13.497 63.931 ;
     RECT  0.54 63.661 0.558 64.013 ;
     RECT  14.796 63.859 14.85 64.027 ;
     RECT  12.78 63.931 13.497 64.049 ;
     RECT  9.792 63.311 10.854 64.057 ;
     RECT  2.304 63.815 9.018 64.093 ;
     RECT  9.792 64.057 11.43 64.093 ;
     RECT  21.384 63.113 21.438 64.123 ;
     RECT  2.304 64.093 11.43 64.157 ;
     RECT  14.724 64.027 14.85 64.157 ;
     RECT  2.304 64.157 11.394 64.229 ;
     RECT  15.912 63.859 20.502 64.301 ;
     RECT  15.912 64.301 19.422 64.397 ;
     RECT  20.448 64.301 20.502 64.399 ;
     RECT  21.348 64.123 21.438 64.463 ;
     RECT  15.912 64.397 19.098 64.471 ;
     RECT  15.768 64.471 19.098 64.589 ;
     RECT  15.915 64.589 19.098 64.625 ;
     RECT  2.304 64.229 10.797 64.741 ;
     RECT  12.42 64.561 12.438 64.769 ;
     RECT  13.215 64.049 13.497 65.011 ;
     RECT  13.215 65.011 13.554 65.129 ;
     RECT  20.448 64.399 20.538 65.131 ;
     RECT  15.915 64.625 19.062 65.371 ;
     RECT  0.216 65.371 0.234 65.501 ;
     RECT  14.796 65.407 14.85 65.543 ;
     RECT  19.908 65.131 20.538 65.549 ;
     RECT  15.915 65.371 19.134 65.713 ;
     RECT  21.42 64.463 21.438 65.755 ;
     RECT  13.215 65.129 13.497 65.821 ;
     RECT  15.624 65.713 19.134 65.821 ;
     RECT  21.384 65.755 21.438 65.849 ;
     RECT  2.268 64.741 10.797 65.911 ;
     RECT  2.268 65.911 10.854 65.933 ;
     RECT  11.772 65.515 11.79 65.939 ;
     RECT  12.816 65.821 13.497 65.939 ;
     RECT  19.908 65.549 20.502 65.995 ;
     RECT  15.336 65.821 19.134 66.011 ;
     RECT  2.304 65.933 10.854 66.091 ;
     RECT  15.552 66.011 19.134 66.091 ;
     RECT  19.872 65.995 20.502 66.091 ;
     RECT  0.216 66.379 0.234 66.509 ;
     RECT  2.304 66.091 10.926 66.551 ;
     RECT  11.844 66.559 11.862 66.631 ;
     RECT  11.844 66.631 12.258 66.749 ;
     RECT  15.552 66.091 20.502 66.749 ;
     RECT  2.304 66.551 10.797 66.865 ;
     RECT  15.915 66.749 20.502 67.019 ;
     RECT  14.832 66.829 14.958 67.027 ;
     RECT  14.724 67.027 14.958 67.055 ;
     RECT  14.724 67.055 14.922 67.091 ;
     RECT  21.384 65.849 21.402 67.147 ;
     RECT  14.724 67.091 14.85 67.199 ;
     RECT  21.384 67.147 21.438 67.397 ;
     RECT  2.268 66.865 10.797 67.559 ;
     RECT  2.268 67.559 9.738 67.595 ;
     RECT  10.515 67.559 10.797 67.639 ;
     RECT  10.515 67.639 10.818 67.711 ;
     RECT  14.832 67.199 14.85 67.739 ;
     RECT  2.304 67.595 9.738 67.757 ;
     RECT  10.515 67.711 11.322 67.829 ;
     RECT  12.24 67.531 12.258 67.829 ;
     RECT  15.915 67.019 19.386 68.155 ;
     RECT  20.412 67.019 20.502 68.155 ;
     RECT  2.304 67.757 9.63 68.395 ;
     RECT  10.515 67.829 10.797 68.449 ;
     RECT  2.268 68.395 9.63 68.521 ;
     RECT  10.368 68.449 10.797 68.521 ;
     RECT  15.915 68.155 20.502 68.521 ;
     RECT  2.268 68.521 10.797 68.639 ;
     RECT  2.268 68.639 9.63 68.747 ;
     RECT  11.736 68.215 11.754 68.791 ;
     RECT  2.268 68.747 9.486 68.909 ;
     RECT  10.515 68.639 10.797 69.061 ;
     RECT  2.268 68.909 9.234 69.163 ;
     RECT  15.3 68.521 20.502 69.187 ;
     RECT  2.232 69.163 9.234 69.215 ;
     RECT  14.832 69.187 20.502 69.287 ;
     RECT  21.42 67.397 21.438 69.331 ;
     RECT  2.268 69.215 8.19 69.449 ;
     RECT  10.515 69.061 10.926 69.449 ;
     RECT  21.384 69.331 21.438 69.449 ;
     RECT  11.736 68.791 12.006 69.565 ;
     RECT  2.268 69.449 4.338 69.755 ;
     RECT  0.216 69.691 0.234 69.787 ;
     RECT  21.384 69.449 21.402 69.821 ;
     RECT  11.736 69.565 12.474 69.871 ;
     RECT  13.215 65.939 13.497 69.871 ;
     RECT  0.036 69.787 0.234 69.899 ;
     RECT  0.216 69.899 0.234 69.917 ;
     RECT  10.515 69.449 10.797 69.961 ;
     RECT  15.372 69.287 20.502 69.989 ;
     RECT  5.112 69.449 8.19 69.997 ;
     RECT  9 69.215 9.234 69.997 ;
     RECT  0.288 69.931 0.306 70.061 ;
     RECT  5.112 69.997 9.234 70.061 ;
     RECT  11.736 69.871 13.497 70.133 ;
     RECT  11.772 70.133 13.497 70.169 ;
     RECT  15.372 69.989 20.466 70.259 ;
     RECT  2.304 69.755 4.338 70.267 ;
     RECT  5.112 70.061 8.097 70.267 ;
     RECT  15.372 70.259 20.43 70.267 ;
     RECT  21.42 70.171 21.438 70.267 ;
     RECT  8.82 70.061 8.838 70.295 ;
     RECT  21.42 70.267 21.546 70.301 ;
     RECT  14.832 70.267 20.43 70.331 ;
     RECT  10.188 69.961 10.797 70.375 ;
     RECT  15.915 70.331 20.43 70.529 ;
     RECT  2.304 70.267 8.097 71.069 ;
     RECT  15.915 70.529 20.394 71.069 ;
     RECT  15.915 71.069 19.926 71.339 ;
     RECT  1.152 69.067 1.17 71.375 ;
     RECT  15.915 71.339 19.206 71.375 ;
     RECT  2.304 71.069 6.39 71.447 ;
     RECT  9.612 70.375 10.797 71.609 ;
     RECT  14.832 70.331 14.85 71.789 ;
     RECT  2.304 71.447 4.302 71.879 ;
     RECT  11.988 70.169 13.497 71.879 ;
     RECT  2.304 71.879 3.078 71.915 ;
     RECT  5.115 71.447 6.39 71.915 ;
     RECT  7.128 71.069 8.097 71.915 ;
     RECT  12.024 71.879 13.497 71.915 ;
     RECT  14.868 71.887 14.886 71.923 ;
     RECT  9.792 71.609 10.797 71.951 ;
     RECT  17.064 71.375 19.206 71.951 ;
     RECT  14.868 71.923 14.958 72.023 ;
     RECT  14.94 72.023 14.958 72.059 ;
     RECT  2.304 71.915 2.934 72.149 ;
     RECT  3.888 71.879 4.302 72.149 ;
     RECT  17.676 71.951 19.206 72.149 ;
     RECT  2.304 72.149 2.697 72.185 ;
     RECT  12.528 71.915 13.497 72.419 ;
     RECT  17.712 72.149 19.206 72.419 ;
     RECT  5.115 71.915 5.922 72.455 ;
     RECT  17.712 72.419 19.17 72.599 ;
     RECT  3.888 72.149 3.906 72.689 ;
     RECT  21.528 70.301 21.546 72.689 ;
     RECT  18.396 72.599 19.17 72.725 ;
     RECT  18.396 72.725 19.026 72.959 ;
     RECT  18.396 72.959 18.897 72.995 ;
     RECT  2.415 72.185 2.697 73.187 ;
     RECT  5.115 72.455 5.397 73.187 ;
     RECT  7.815 71.915 8.097 73.187 ;
     RECT  10.515 71.951 10.797 73.187 ;
     RECT  13.215 72.419 13.497 73.187 ;
     RECT  15.915 71.375 16.197 73.187 ;
     RECT  18.615 72.995 18.897 73.187 ;
     RECT  2.415 73.187 2.505 73.457 ;
     RECT  5.115 73.187 5.205 73.457 ;
     RECT  7.815 73.187 7.905 73.457 ;
     RECT  10.515 73.187 10.605 73.457 ;
     RECT  13.215 73.187 13.305 73.457 ;
     RECT  15.915 73.187 16.005 73.457 ;
     RECT  18.615 73.187 18.705 73.457 ;
    LAYER M4 ;
     RECT  0.025 28.992 0.108 29.784 ;
     RECT  0.025 33.168 0.108 33.576 ;
     RECT  0.108 5.424 0.173 70.2 ;
     RECT  0.173 5.52 0.209 70.2 ;
     RECT  0.209 5.664 0.569 70.2 ;
     RECT  0.569 5.904 2.408 70.2 ;
     RECT  2.408 2.148 2.512 73.452 ;
     RECT  2.512 2.418 2.704 73.182 ;
     RECT  2.704 49.008 2.729 57.48 ;
     RECT  2.704 6.672 2.765 13.128 ;
     RECT  2.765 7.92 2.837 12.84 ;
     RECT  2.704 45.552 2.837 47.88 ;
     RECT  2.729 50.352 2.837 57.48 ;
     RECT  2.704 69.456 2.845 70.872 ;
     RECT  2.704 21.408 2.867 29.592 ;
     RECT  2.704 31.104 2.873 39.384 ;
     RECT  2.867 21.408 2.909 26.28 ;
     RECT  2.704 44.4 2.981 44.424 ;
     RECT  2.837 45.792 2.981 47.88 ;
     RECT  2.909 21.504 3.017 26.28 ;
     RECT  2.873 31.152 3.089 39.384 ;
     RECT  2.845 69.456 3.089 70.056 ;
     RECT  3.089 31.152 3.269 35.928 ;
     RECT  2.704 58.512 3.341 60.936 ;
     RECT  2.837 7.92 3.377 10.632 ;
     RECT  2.765 6.672 3.449 6.888 ;
     RECT  2.867 27.84 3.449 29.592 ;
     RECT  2.837 50.352 3.485 55.992 ;
     RECT  3.269 33.936 3.491 34.92 ;
     RECT  3.377 8.304 3.521 10.632 ;
     RECT  3.485 54.096 3.521 55.992 ;
     RECT  3.521 55.968 3.532 55.992 ;
     RECT  3.341 58.512 3.557 59.256 ;
     RECT  2.704 63.744 3.557 67.704 ;
     RECT  3.341 60.384 3.587 60.936 ;
     RECT  2.837 11.664 3.593 12.84 ;
     RECT  3.089 69.456 3.629 69.48 ;
     RECT  3.089 36.912 3.733 39.384 ;
     RECT  2.704 40.368 3.733 43.32 ;
     RECT  2.704 61.968 3.733 62.664 ;
     RECT  3.557 63.744 3.733 65.064 ;
     RECT  3.485 50.352 3.845 53.064 ;
     RECT  2.704 14.736 3.913 16.92 ;
     RECT  2.981 45.792 3.913 47.304 ;
     RECT  3.557 66.48 3.913 67.704 ;
     RECT  3.733 36.912 3.925 43.32 ;
     RECT  2.837 57.024 3.925 57.48 ;
     RECT  3.521 9.696 3.949 10.632 ;
     RECT  3.593 11.664 3.949 12.36 ;
     RECT  3.913 14.736 3.949 17.112 ;
     RECT  3.913 45.696 3.949 47.304 ;
     RECT  3.925 56.256 3.949 57.48 ;
     RECT  3.557 58.512 3.949 58.584 ;
     RECT  3.017 21.696 3.971 26.28 ;
     RECT  3.913 66.48 4.025 67.848 ;
     RECT  3.449 27.84 4.057 29.496 ;
     RECT  3.269 31.152 4.061 32.808 ;
     RECT  3.971 23.952 4.093 26.28 ;
     RECT  4.057 27.456 4.093 29.496 ;
     RECT  3.269 35.904 4.093 35.928 ;
     RECT  3.925 36.912 4.093 43.368 ;
     RECT  3.521 54.096 4.097 54.696 ;
     RECT  3.949 14.592 4.345 17.112 ;
     RECT  4.093 35.904 4.345 43.368 ;
     RECT  3.733 61.968 4.345 65.064 ;
     RECT  4.061 31.152 4.381 32.52 ;
     RECT  4.345 35.904 4.417 43.416 ;
     RECT  4.237 44.448 4.417 44.472 ;
     RECT  4.417 35.904 4.453 44.472 ;
     RECT  3.949 45.696 4.453 47.4 ;
     RECT  4.345 14.4 4.489 17.112 ;
     RECT  2.704 18.144 4.489 20.136 ;
     RECT  3.521 8.304 4.525 8.328 ;
     RECT  2.729 49.008 4.597 49.032 ;
     RECT  3.845 50.352 4.597 53.016 ;
     RECT  4.489 14.4 4.633 20.136 ;
     RECT  4.345 61.632 4.633 65.064 ;
     RECT  4.633 14.4 4.669 20.616 ;
     RECT  3.949 56.256 4.741 58.584 ;
     RECT  4.525 7.92 4.921 8.328 ;
     RECT  3.949 9.696 4.921 12.36 ;
     RECT  4.417 60 4.957 60.024 ;
     RECT  4.633 61.44 4.957 65.064 ;
     RECT  4.025 66.48 4.993 66.504 ;
     RECT  4.813 5.76 5.108 5.784 ;
     RECT  3.449 6.864 5.108 6.888 ;
     RECT  4.921 7.92 5.108 12.36 ;
     RECT  4.669 14.112 5.108 20.616 ;
     RECT  3.971 21.696 5.108 22.824 ;
     RECT  4.093 23.952 5.108 29.496 ;
     RECT  4.381 30.672 5.108 32.52 ;
     RECT  3.491 34.08 5.108 34.92 ;
     RECT  4.453 35.904 5.108 47.4 ;
     RECT  4.597 49.008 5.108 53.016 ;
     RECT  4.097 54.096 5.108 54.6 ;
     RECT  4.741 56.016 5.108 58.584 ;
     RECT  4.957 60 5.108 65.064 ;
     RECT  4.993 66.048 5.108 66.504 ;
     RECT  4.025 67.536 5.108 67.848 ;
     RECT  4.741 68.928 5.108 68.952 ;
     RECT  4.993 70.272 5.108 70.296 ;
     RECT  5.108 2.148 5.212 73.452 ;
     RECT  5.212 2.418 5.404 73.182 ;
     RECT  5.404 55.872 5.465 66.072 ;
     RECT  5.465 63.552 5.555 66.072 ;
     RECT  5.404 2.832 5.717 2.856 ;
     RECT  5.465 55.872 5.795 62.568 ;
     RECT  5.404 5.328 5.825 5.784 ;
     RECT  5.404 7.392 5.825 7.416 ;
     RECT  5.555 63.552 5.933 63.576 ;
     RECT  5.404 43.632 5.939 49.032 ;
     RECT  5.939 43.632 5.969 47.448 ;
     RECT  5.404 8.976 6.083 12.504 ;
     RECT  5.795 55.872 6.227 56.52 ;
     RECT  6.083 8.976 6.257 10.68 ;
     RECT  5.969 44.064 6.275 47.448 ;
     RECT  5.404 67.488 6.275 70.152 ;
     RECT  5.404 14.112 6.293 22.824 ;
     RECT  6.275 70.128 6.365 70.152 ;
     RECT  5.825 5.76 6.437 5.784 ;
     RECT  5.404 50.304 6.469 50.664 ;
     RECT  6.293 22.176 6.517 22.824 ;
     RECT  5.404 23.808 6.517 28.728 ;
     RECT  6.293 14.112 6.613 21.144 ;
     RECT  6.517 22.176 6.613 28.728 ;
     RECT  5.404 29.952 6.613 42.168 ;
     RECT  6.469 50.064 6.613 50.664 ;
     RECT  5.404 51.744 6.613 54.696 ;
     RECT  6.083 11.712 6.649 12.504 ;
     RECT  6.565 7.92 6.653 7.944 ;
     RECT  5.795 57.6 6.653 62.568 ;
     RECT  6.649 11.712 6.661 12.744 ;
     RECT  6.613 13.872 6.661 21.144 ;
     RECT  6.661 11.712 6.707 21.144 ;
     RECT  5.939 48.816 6.865 49.032 ;
     RECT  6.613 50.064 6.865 54.696 ;
     RECT  6.613 22.176 7.045 42.168 ;
     RECT  7.045 22.176 7.117 43.032 ;
     RECT  6.275 44.064 7.117 44.76 ;
     RECT  6.257 9.36 7.225 10.68 ;
     RECT  6.865 48.816 7.297 54.696 ;
     RECT  6.275 46.08 7.333 47.448 ;
     RECT  7.297 48.432 7.333 54.696 ;
     RECT  6.653 57.936 7.333 62.568 ;
     RECT  6.275 67.488 7.333 69 ;
     RECT  7.333 57.936 7.429 63 ;
     RECT  5.555 64.656 7.429 65.592 ;
     RECT  7.429 57.936 7.549 65.592 ;
     RECT  7.549 57.936 7.621 66.264 ;
     RECT  7.333 67.344 7.621 69 ;
     RECT  6.707 12.192 7.765 21.144 ;
     RECT  7.117 22.176 7.765 44.76 ;
     RECT  6.937 7.344 7.808 7.752 ;
     RECT  7.225 9.36 7.808 11.208 ;
     RECT  7.765 12.192 7.808 45 ;
     RECT  7.333 46.08 7.808 54.696 ;
     RECT  6.227 55.968 7.808 56.52 ;
     RECT  7.621 57.936 7.808 69 ;
     RECT  7.808 2.148 7.912 73.452 ;
     RECT  7.912 2.418 8.104 73.182 ;
     RECT  8.104 6.288 8.165 28.44 ;
     RECT  8.104 69.984 8.201 70.008 ;
     RECT  8.165 6.528 8.243 28.44 ;
     RECT  8.243 9.504 8.309 28.44 ;
     RECT  8.309 9.552 8.381 28.44 ;
     RECT  8.104 48.912 8.561 50.856 ;
     RECT  8.104 57.6 8.849 69 ;
     RECT  8.104 29.76 8.921 47.832 ;
     RECT  8.849 57.6 8.921 68.616 ;
     RECT  8.921 30.672 8.963 47.832 ;
     RECT  8.381 10.176 8.993 28.44 ;
     RECT  8.243 6.528 9.029 7.464 ;
     RECT  8.963 31.056 9.029 47.832 ;
     RECT  8.921 57.6 9.029 68.52 ;
     RECT  8.993 10.32 9.065 28.44 ;
     RECT  9.029 40.896 9.065 47.832 ;
     RECT  9.065 10.32 9.137 18.216 ;
     RECT  9.029 62.208 9.137 68.52 ;
     RECT  9.065 19.248 9.169 28.44 ;
     RECT  9.169 19.248 9.173 28.728 ;
     RECT  9.029 57.6 9.203 61.032 ;
     RECT  9.173 24.144 9.209 28.728 ;
     RECT  8.104 51.936 9.209 56.52 ;
     RECT  9.137 62.208 9.209 67.848 ;
     RECT  8.561 49.008 9.245 50.856 ;
     RECT  9.065 40.896 9.251 47.736 ;
     RECT  9.209 62.208 9.251 67.752 ;
     RECT  9.251 66.384 9.273 67.752 ;
     RECT  9.209 24.624 9.301 28.728 ;
     RECT  9.029 7.44 9.317 7.464 ;
     RECT  9.029 31.056 9.347 39.768 ;
     RECT  9.251 62.208 9.353 65.304 ;
     RECT  9.301 24.624 9.388 28.824 ;
     RECT  9.245 49.536 9.389 50.856 ;
     RECT  9.353 64.272 9.389 65.304 ;
     RECT  9.203 57.744 9.395 61.032 ;
     RECT  9.137 10.32 9.425 18.168 ;
     RECT  9.425 10.32 9.461 18.072 ;
     RECT  9.461 13.872 9.497 18.072 ;
     RECT  9.389 49.872 10.069 50.856 ;
     RECT  9.209 51.936 10.069 53.4 ;
     RECT  9.251 40.896 10.213 42.168 ;
     RECT  9.251 43.536 10.213 47.736 ;
     RECT  9.347 31.152 10.357 39.768 ;
     RECT  9.685 7.968 10.508 7.992 ;
     RECT  9.461 10.32 10.508 12.648 ;
     RECT  9.497 13.872 10.508 17.976 ;
     RECT  9.173 19.248 10.508 23.016 ;
     RECT  9.388 24.624 10.508 28.728 ;
     RECT  10.357 30.96 10.508 39.768 ;
     RECT  10.213 40.896 10.508 47.736 ;
     RECT  10.069 49.872 10.508 53.4 ;
     RECT  9.209 54.672 10.508 56.52 ;
     RECT  9.395 57.744 10.508 60.936 ;
     RECT  9.353 62.208 10.508 63.288 ;
     RECT  9.389 64.656 10.508 65.304 ;
     RECT  9.273 66.384 10.508 66.696 ;
     RECT  9.273 67.728 10.508 67.752 ;
     RECT  10.508 2.148 10.612 73.452 ;
     RECT  10.612 2.418 10.804 73.182 ;
     RECT  10.804 67.68 10.829 67.704 ;
     RECT  10.804 19.488 10.865 21 ;
     RECT  10.804 28.128 10.865 28.248 ;
     RECT  10.804 51.888 10.865 53.928 ;
     RECT  10.804 57.888 10.865 57.96 ;
     RECT  10.804 40.896 10.901 42.072 ;
     RECT  10.804 46.752 10.901 47.064 ;
     RECT  10.865 57.888 10.937 57.912 ;
     RECT  10.804 38.448 10.973 39.768 ;
     RECT  10.804 43.872 11.045 44.76 ;
     RECT  10.865 51.936 11.045 53.928 ;
     RECT  10.804 35.808 11.117 37.416 ;
     RECT  10.973 39.024 12.337 39.768 ;
     RECT  12.337 38.736 12.437 39.768 ;
     RECT  10.804 10.32 13.208 10.344 ;
     RECT  10.804 12.336 13.208 12.504 ;
     RECT  10.804 13.872 13.208 14.664 ;
     RECT  10.804 15.984 13.208 17.976 ;
     RECT  10.865 19.584 13.208 21 ;
     RECT  10.804 24.624 13.208 26.616 ;
     RECT  10.865 28.176 13.208 28.248 ;
     RECT  10.804 31.2 13.208 32.76 ;
     RECT  10.804 34.368 13.208 34.776 ;
     RECT  11.117 36.624 13.208 37.416 ;
     RECT  12.437 38.736 13.208 39.912 ;
     RECT  10.901 40.896 13.208 41.976 ;
     RECT  11.045 43.872 13.208 44.376 ;
     RECT  10.901 46.8 13.208 47.064 ;
     RECT  11.045 51.936 13.208 53.4 ;
     RECT  10.804 54.912 13.208 54.936 ;
     RECT  10.804 56.016 13.208 56.376 ;
     RECT  10.804 60 13.208 60.936 ;
     RECT  10.804 62.208 13.208 63 ;
     RECT  10.804 64.128 13.208 64.68 ;
     RECT  13.208 2.148 13.312 73.452 ;
     RECT  13.312 2.418 13.504 73.182 ;
     RECT  13.504 62.208 13.601 63 ;
     RECT  13.504 44.352 13.637 44.424 ;
     RECT  13.504 36.624 13.853 37.464 ;
     RECT  13.504 28.176 14.321 28.248 ;
     RECT  13.504 13.872 14.465 17.976 ;
     RECT  13.504 34.704 14.677 34.776 ;
     RECT  13.504 64.128 14.713 64.68 ;
     RECT  14.677 34.704 14.761 35.352 ;
     RECT  14.465 13.872 14.789 14.664 ;
     RECT  13.853 36.624 14.821 37.32 ;
     RECT  13.601 62.304 14.861 63 ;
     RECT  14.713 64.032 14.861 64.68 ;
     RECT  13.504 19.584 14.933 21 ;
     RECT  14.821 36.624 15.829 37.416 ;
     RECT  14.861 62.448 15.901 63 ;
     RECT  14.861 64.128 15.901 64.68 ;
     RECT  13.504 10.32 15.908 10.344 ;
     RECT  13.504 12.336 15.908 12.504 ;
     RECT  14.789 13.872 15.908 14.472 ;
     RECT  14.465 15.984 15.908 17.976 ;
     RECT  14.933 19.584 15.908 20.952 ;
     RECT  13.504 24.624 15.908 26.616 ;
     RECT  14.321 28.176 15.908 28.2 ;
     RECT  13.504 31.2 15.908 32.76 ;
     RECT  14.761 34.704 15.908 34.776 ;
     RECT  15.829 36.624 15.908 37.656 ;
     RECT  15.649 38.736 15.908 38.76 ;
     RECT  13.504 39.744 15.908 39.768 ;
     RECT  13.504 40.896 15.908 41.976 ;
     RECT  13.637 44.352 15.908 44.376 ;
     RECT  13.504 46.8 15.908 47.064 ;
     RECT  13.504 51.936 15.908 53.4 ;
     RECT  13.504 54.912 15.908 54.936 ;
     RECT  13.504 56.016 15.908 56.376 ;
     RECT  13.504 60 15.908 60.936 ;
     RECT  15.901 62.448 15.908 64.68 ;
     RECT  15.908 2.148 16.012 73.452 ;
     RECT  16.012 2.418 16.204 73.182 ;
     RECT  16.204 40.896 16.301 42.024 ;
     RECT  16.204 38.736 16.337 39.288 ;
     RECT  16.204 31.92 16.373 33.672 ;
     RECT  16.204 60.912 16.373 60.936 ;
     RECT  16.301 40.896 16.409 40.92 ;
     RECT  16.204 56.064 16.517 57.432 ;
     RECT  16.204 62.208 16.589 62.472 ;
     RECT  16.204 19.248 16.805 20.376 ;
     RECT  16.204 14.256 17.197 14.28 ;
     RECT  16.204 15.264 17.197 17.688 ;
     RECT  17.197 14.256 17.233 17.688 ;
     RECT  16.805 19.248 17.233 20.184 ;
     RECT  17.233 21.504 17.269 21.528 ;
     RECT  16.204 22.752 17.269 23.256 ;
     RECT  16.301 42 17.269 42.024 ;
     RECT  16.373 31.92 17.305 31.944 ;
     RECT  16.204 28.8 17.341 29.544 ;
     RECT  16.204 44.976 17.341 45.096 ;
     RECT  16.204 10.56 17.377 10.584 ;
     RECT  16.204 11.904 17.377 11.928 ;
     RECT  17.305 31.008 17.413 31.944 ;
     RECT  16.373 32.928 17.413 33.672 ;
     RECT  16.204 51.12 17.449 52.44 ;
     RECT  17.449 50.544 17.453 52.44 ;
     RECT  17.377 10.56 17.485 11.928 ;
     RECT  16.204 13.056 17.485 13.08 ;
     RECT  17.233 14.112 17.485 17.688 ;
     RECT  17.269 41.136 17.485 42.024 ;
     RECT  16.204 43.008 17.485 43.032 ;
     RECT  16.337 39.264 17.521 39.288 ;
     RECT  16.204 46.8 17.557 48.456 ;
     RECT  16.204 37.584 17.593 37.656 ;
     RECT  17.485 41.136 17.593 43.032 ;
     RECT  17.557 46.8 17.593 49.56 ;
     RECT  17.453 50.544 17.593 52.296 ;
     RECT  17.413 54.672 17.593 54.696 ;
     RECT  16.204 58.656 17.593 59.736 ;
     RECT  16.204 63.84 17.593 64.2 ;
     RECT  17.341 44.976 17.629 45.48 ;
     RECT  17.269 21.504 17.665 23.256 ;
     RECT  16.204 25.776 17.665 26.664 ;
     RECT  17.485 10.416 17.701 11.928 ;
     RECT  17.629 44.976 17.701 45.72 ;
     RECT  16.204 34.8 17.737 35.64 ;
     RECT  17.665 21.408 17.773 23.256 ;
     RECT  17.773 21.408 17.809 23.448 ;
     RECT  17.665 24.912 17.809 26.664 ;
     RECT  16.517 56.304 17.809 57.432 ;
     RECT  17.593 58.656 17.809 59.784 ;
     RECT  17.593 54.672 17.845 55.32 ;
     RECT  17.341 28.8 17.953 29.832 ;
     RECT  17.413 31.008 17.953 33.672 ;
     RECT  17.737 34.656 17.953 35.64 ;
     RECT  17.593 36.912 17.953 38.184 ;
     RECT  17.521 39.264 18.025 39.624 ;
     RECT  17.809 56.304 18.025 59.784 ;
     RECT  17.809 21.408 18.061 26.664 ;
     RECT  18.061 21.408 18.205 26.904 ;
     RECT  16.589 62.208 18.241 62.232 ;
     RECT  17.953 34.656 18.385 38.184 ;
     RECT  18.025 39.264 18.385 40.056 ;
     RECT  17.953 6.672 18.469 6.696 ;
     RECT  18.469 5.28 18.608 6.696 ;
     RECT  18.457 8.496 18.608 8.52 ;
     RECT  17.701 9.792 18.608 11.928 ;
     RECT  17.485 13.056 18.608 17.688 ;
     RECT  17.233 18.672 18.608 20.184 ;
     RECT  18.205 21.408 18.608 27.672 ;
     RECT  17.953 28.8 18.608 33.672 ;
     RECT  18.385 34.656 18.608 40.056 ;
     RECT  17.593 41.136 18.608 43.32 ;
     RECT  17.701 44.496 18.608 45.72 ;
     RECT  17.593 46.8 18.608 52.296 ;
     RECT  16.204 53.52 18.608 53.544 ;
     RECT  17.845 54.624 18.608 55.32 ;
     RECT  18.025 56.304 18.608 60.312 ;
     RECT  18.241 61.968 18.608 62.232 ;
     RECT  17.593 63.216 18.608 64.2 ;
     RECT  18.205 68.208 18.608 68.232 ;
     RECT  18.608 2.148 18.712 73.452 ;
     RECT  18.712 2.418 18.904 73.182 ;
     RECT  18.904 24.192 18.929 24.216 ;
     RECT  18.904 26.88 18.929 33.096 ;
     RECT  18.904 47.04 18.929 52.296 ;
     RECT  18.904 5.136 19.073 16.008 ;
     RECT  18.929 28.512 19.109 33.096 ;
     RECT  18.929 50.208 19.181 52.296 ;
     RECT  18.904 22.656 19.217 23.16 ;
     RECT  19.073 5.52 19.897 16.008 ;
     RECT  18.904 17.136 19.897 19.272 ;
     RECT  18.904 20.688 19.897 20.808 ;
     RECT  18.904 25.344 19.897 25.368 ;
     RECT  19.109 28.512 19.897 31.8 ;
     RECT  18.904 34.56 19.897 35.256 ;
     RECT  18.904 44.4 19.897 45.72 ;
     RECT  18.929 47.04 19.897 49.128 ;
     RECT  19.181 50.208 19.897 50.376 ;
     RECT  18.904 61.968 19.897 62.232 ;
     RECT  18.904 63.6 19.897 64.632 ;
     RECT  18.904 66 19.897 69.72 ;
     RECT  19.897 23.184 19.933 23.208 ;
     RECT  18.929 26.88 19.933 26.904 ;
     RECT  19.897 27.984 19.933 31.8 ;
     RECT  19.109 32.784 19.933 33.096 ;
     RECT  19.897 34.56 19.933 35.352 ;
     RECT  18.904 36.576 19.933 42.792 ;
     RECT  19.181 51.36 19.933 52.296 ;
     RECT  18.904 53.376 19.933 56.328 ;
     RECT  18.904 57.408 19.933 60.888 ;
     RECT  19.897 61.968 19.933 70.104 ;
     RECT  19.933 32.784 20.005 43.032 ;
     RECT  19.897 25.2 20.185 25.368 ;
     RECT  19.933 26.736 20.185 31.8 ;
     RECT  19.933 23.184 20.401 23.496 ;
     RECT  20.185 25.2 20.401 31.8 ;
     RECT  20.401 22.944 20.437 23.496 ;
     RECT  20.401 24.96 20.437 31.8 ;
     RECT  20.005 32.784 20.437 43.176 ;
     RECT  19.897 44.4 20.437 50.376 ;
     RECT  19.933 51.36 20.437 70.104 ;
     RECT  19.897 5.52 20.473 20.808 ;
     RECT  20.437 22.176 20.473 23.496 ;
     RECT  20.437 24.864 20.473 43.176 ;
     RECT  20.437 44.304 20.473 70.104 ;
     RECT  20.473 5.52 20.509 43.176 ;
     RECT  20.473 44.16 20.509 70.104 ;
     RECT  20.509 5.424 21.409 70.104 ;
     RECT  21.409 5.424 21.516 70.296 ;
     RECT  21.516 70.272 21.557 70.296 ;
    LAYER M5 ;
     RECT  2.4 2.137 2.52 2.151 ;
     RECT  5.1 2.137 5.22 2.151 ;
     RECT  7.8 2.137 7.92 2.151 ;
     RECT  9.696 2.137 10.62 2.151 ;
     RECT  13.2 2.137 13.32 2.151 ;
     RECT  15.9 2.137 16.02 2.151 ;
     RECT  18.6 2.137 18.72 2.151 ;
     RECT  5.1 2.151 5.412 2.821 ;
     RECT  18.6 2.151 18.912 5.269 ;
     RECT  18.48 5.269 18.912 5.747 ;
     RECT  7.8 2.151 8.112 7.429 ;
     RECT  5.1 2.821 5.688 7.909 ;
     RECT  9.696 2.151 10.812 8.003 ;
     RECT  2.4 2.151 2.712 8.437 ;
     RECT  7.8 7.429 8.232 9.011 ;
     RECT  5.1 7.909 6.6 9.155 ;
     RECT  6.576 9.155 6.6 9.395 ;
     RECT  2.4 8.437 3.432 9.731 ;
     RECT  7.8 9.011 8.112 10.597 ;
     RECT  6.672 10.645 6.696 11.029 ;
     RECT  7.8 10.597 8.616 11.029 ;
     RECT  5.1 9.155 5.412 11.365 ;
     RECT  6.672 11.029 8.616 11.365 ;
     RECT  2.4 9.731 3.384 12.035 ;
     RECT  5.1 11.365 8.616 12.755 ;
     RECT  5.1 12.755 8.112 13.139 ;
     RECT  7.344 13.139 8.112 14.101 ;
     RECT  5.1 13.139 6.072 14.677 ;
     RECT  7.344 14.101 8.232 14.677 ;
     RECT  5.1 14.677 8.232 15.443 ;
     RECT  2.4 12.035 2.712 15.877 ;
     RECT  7.344 15.443 8.232 16.067 ;
     RECT  2.4 15.877 3.672 16.309 ;
     RECT  5.1 15.443 6.072 16.309 ;
     RECT  0.336 1.285 0.36 16.357 ;
     RECT  0.24 16.357 0.36 16.499 ;
     RECT  7.488 16.067 8.232 16.883 ;
     RECT  7.8 16.883 8.232 17.027 ;
     RECT  2.4 16.309 6.072 17.699 ;
     RECT  4.896 17.699 6.072 18.181 ;
     RECT  7.8 17.027 8.112 18.181 ;
     RECT  9.36 16.981 9.384 18.181 ;
     RECT  4.896 18.181 6.792 18.707 ;
     RECT  2.4 17.699 3.672 19.139 ;
     RECT  6.768 18.707 6.792 19.283 ;
     RECT  7.8 18.181 9.384 20.053 ;
     RECT  6.816 20.053 9.384 20.675 ;
     RECT  4.896 18.707 5.412 21.971 ;
     RECT  5.1 21.971 5.412 22.165 ;
     RECT  7.8 20.675 9.384 22.741 ;
     RECT  5.1 22.165 6.264 22.835 ;
     RECT  3.936 22.741 3.96 23.555 ;
     RECT  7.536 22.741 9.384 23.651 ;
     RECT  6.528 23.605 6.552 23.893 ;
     RECT  7.536 23.651 8.112 23.987 ;
     RECT  9.12 23.651 9.384 24.131 ;
     RECT  7.8 23.987 8.112 25.237 ;
     RECT  9.36 24.131 9.384 25.237 ;
     RECT  7.8 25.237 9.384 26.243 ;
     RECT  3.936 25.621 3.96 26.291 ;
     RECT  5.1 22.835 5.412 26.629 ;
     RECT  2.4 19.139 2.712 27.061 ;
     RECT  4.992 26.629 5.412 27.395 ;
     RECT  9.36 26.243 9.384 27.395 ;
     RECT  2.4 27.061 2.856 27.875 ;
     RECT  6.432 23.893 6.552 29.269 ;
     RECT  7.8 26.243 8.112 29.269 ;
     RECT  6.432 29.269 8.112 29.459 ;
     RECT  5.1 27.395 5.412 30.037 ;
     RECT  6.432 29.459 6.648 30.037 ;
     RECT  7.8 29.459 8.112 30.661 ;
     RECT  9.312 28.789 9.336 30.661 ;
     RECT  5.1 30.037 6.648 31.139 ;
     RECT  6.432 31.139 6.648 31.379 ;
     RECT  3.984 31.141 4.008 31.955 ;
     RECT  7.8 30.661 9.336 32.723 ;
     RECT  2.4 27.875 2.712 32.773 ;
     RECT  6.432 31.379 6.552 33.109 ;
     RECT  7.8 32.723 8.112 33.109 ;
     RECT  9.312 32.723 9.336 34.357 ;
     RECT  13.2 2.151 13.512 34.357 ;
     RECT  6.432 33.109 8.112 34.787 ;
     RECT  2.4 32.773 3.48 34.835 ;
     RECT  7.8 34.787 8.112 34.981 ;
     RECT  9.312 34.357 9.48 34.981 ;
     RECT  14.688 34.741 14.712 35.363 ;
     RECT  7.8 34.981 9.48 35.939 ;
     RECT  7.8 35.939 9.096 36.515 ;
     RECT  12.48 34.357 13.512 36.803 ;
     RECT  0.336 16.499 0.36 37.427 ;
     RECT  6.432 34.787 6.456 37.573 ;
     RECT  6.432 37.573 6.648 37.619 ;
     RECT  7.8 36.515 8.112 38.533 ;
     RECT  5.1 31.139 5.412 38.677 ;
     RECT  13.2 36.803 13.512 38.725 ;
     RECT  4.512 38.677 5.412 38.917 ;
     RECT  6.624 37.619 6.648 38.917 ;
     RECT  7.8 38.533 8.952 38.963 ;
     RECT  4.512 38.917 6.648 39.587 ;
     RECT  12.48 38.725 13.512 39.923 ;
     RECT  7.8 38.963 8.112 41.413 ;
     RECT  7.632 41.413 8.112 42.565 ;
     RECT  7.632 42.565 8.232 42.803 ;
     RECT  3.936 40.981 3.96 42.853 ;
     RECT  5.1 39.587 6.648 42.853 ;
     RECT  3.936 42.853 6.648 43.379 ;
     RECT  4.56 43.379 6.648 44.437 ;
     RECT  7.8 42.803 8.232 44.437 ;
     RECT  4.56 44.437 8.232 44.483 ;
     RECT  5.1 44.483 8.232 45.011 ;
     RECT  9.216 42.133 9.24 45.155 ;
     RECT  5.1 45.011 8.112 45.637 ;
     RECT  4.56 45.637 8.112 46.693 ;
     RECT  4.512 46.693 8.112 47.363 ;
     RECT  5.1 47.363 8.112 49.043 ;
     RECT  5.1 49.043 5.412 49.525 ;
     RECT  2.4 34.835 2.712 50.629 ;
     RECT  4.992 49.525 5.412 51.347 ;
     RECT  6.624 49.043 8.112 51.347 ;
     RECT  2.4 50.629 3.432 52.019 ;
     RECT  7.008 51.347 8.112 53.557 ;
     RECT  9.36 47.173 9.384 53.557 ;
     RECT  5.1 51.347 5.412 53.893 ;
     RECT  7.008 53.557 9.384 53.893 ;
     RECT  5.1 53.893 9.384 55.907 ;
     RECT  2.4 52.019 2.712 55.957 ;
     RECT  2.4 55.957 3.48 56.341 ;
     RECT  7.008 55.907 9.384 56.483 ;
     RECT  2.4 56.341 3.96 57.059 ;
     RECT  5.1 55.907 5.412 57.397 ;
     RECT  9.168 56.483 9.384 57.635 ;
     RECT  5.1 57.397 5.784 58.597 ;
     RECT  7.008 56.483 8.112 58.597 ;
     RECT  5.1 58.597 8.112 59.315 ;
     RECT  2.4 57.059 2.712 60.901 ;
     RECT  7.008 59.315 8.112 60.949 ;
     RECT  9.36 57.635 9.384 60.949 ;
     RECT  7.008 60.949 9.384 61.043 ;
     RECT  2.4 60.901 3.576 62.195 ;
     RECT  5.1 59.315 5.412 62.533 ;
     RECT  7.008 61.043 8.664 62.579 ;
     RECT  7.8 62.579 8.664 62.771 ;
     RECT  7.8 62.771 8.232 63.251 ;
     RECT  7.8 63.251 8.112 63.781 ;
     RECT  5.1 62.533 5.544 63.875 ;
     RECT  7.44 63.781 8.112 65.027 ;
     RECT  5.1 63.875 5.412 65.509 ;
     RECT  5.1 65.509 5.544 66.083 ;
     RECT  9.216 65.509 9.24 66.899 ;
     RECT  7.8 65.027 8.112 67.333 ;
     RECT  7.344 67.333 8.112 68.435 ;
     RECT  5.1 66.083 5.412 68.629 ;
     RECT  5.1 68.629 6.264 69.587 ;
     RECT  2.4 62.195 2.712 70.165 ;
     RECT  2.4 70.165 2.808 70.883 ;
     RECT  2.4 70.883 2.712 73.449 ;
     RECT  5.1 69.587 5.412 73.449 ;
     RECT  7.8 68.435 8.112 73.449 ;
     RECT  10.5 8.003 10.812 73.449 ;
     RECT  13.2 39.923 13.512 73.449 ;
     RECT  15.9 2.151 16.212 73.449 ;
     RECT  18.6 5.747 18.912 73.449 ;
     RECT  2.4 73.449 2.52 73.463 ;
     RECT  5.1 73.449 5.22 73.463 ;
     RECT  7.8 73.449 7.92 73.463 ;
     RECT  10.5 73.449 10.62 73.463 ;
     RECT  13.2 73.449 13.32 73.463 ;
     RECT  15.9 73.449 16.02 73.463 ;
     RECT  18.6 73.449 18.72 73.463 ;
     RECT  8.232 7.429 9.696 8.003 ;
     RECT  6.6 7.909 7.8 9.395 ;
     RECT  5.412 9.155 6.576 9.395 ;
     RECT  5.412 9.395 7.8 10.645 ;
     RECT  5.412 10.645 6.672 11.365 ;
     RECT  6.696 10.645 7.8 11.029 ;
     RECT  8.112 12.755 8.232 14.101 ;
     RECT  6.072 13.139 7.344 14.677 ;
     RECT  6.072 15.443 7.344 16.067 ;
     RECT  3.672 15.877 5.1 16.309 ;
     RECT  6.072 16.067 7.488 16.883 ;
     RECT  6.072 16.883 7.8 18.181 ;
     RECT  8.232 16.981 9.36 17.027 ;
     RECT  9.384 16.981 10.5 27.395 ;
     RECT  8.112 17.027 9.36 18.181 ;
     RECT  3.672 17.699 4.896 19.139 ;
     RECT  6.792 18.181 7.8 19.283 ;
     RECT  5.412 18.707 6.768 19.283 ;
     RECT  5.412 19.283 7.8 20.053 ;
     RECT  5.412 20.053 6.816 20.675 ;
     RECT  5.412 20.675 6.264 22.165 ;
     RECT  4.896 21.971 5.1 22.741 ;
     RECT  2.712 22.741 3.936 23.555 ;
     RECT  3.96 22.741 5.1 23.555 ;
     RECT  6.264 22.741 7.536 22.835 ;
     RECT  5.412 22.835 7.536 23.605 ;
     RECT  5.412 23.605 6.528 23.893 ;
     RECT  6.552 23.605 7.536 23.987 ;
     RECT  8.112 23.651 9.12 24.131 ;
     RECT  5.412 23.893 6.432 30.037 ;
     RECT  6.552 23.987 7.8 29.269 ;
     RECT  8.112 24.131 9.36 25.237 ;
     RECT  2.712 25.621 3.936 26.291 ;
     RECT  3.96 25.621 5.1 26.291 ;
     RECT  8.112 26.243 9.36 27.395 ;
     RECT  2.712 26.291 2.856 27.061 ;
     RECT  4.992 26.291 5.1 26.629 ;
     RECT  8.112 27.395 10.5 28.789 ;
     RECT  8.112 28.789 9.312 30.661 ;
     RECT  9.336 28.789 10.5 34.357 ;
     RECT  6.648 29.459 7.8 31.379 ;
     RECT  5.412 31.139 6.432 37.619 ;
     RECT  2.712 31.141 3.984 31.955 ;
     RECT  4.008 31.141 5.1 31.955 ;
     RECT  6.552 31.379 7.8 33.109 ;
     RECT  2.712 31.955 3.48 32.773 ;
     RECT  8.112 32.723 9.312 34.981 ;
     RECT  9.48 34.357 10.5 35.939 ;
     RECT  13.512 34.741 14.688 35.363 ;
     RECT  14.712 34.741 15.9 35.363 ;
     RECT  6.456 34.787 7.8 37.573 ;
     RECT  9.096 35.939 10.5 36.515 ;
     RECT  6.648 37.573 7.8 41.413 ;
     RECT  5.412 37.619 6.624 38.917 ;
     RECT  4.512 39.587 5.1 40.981 ;
     RECT  2.712 40.981 3.936 43.379 ;
     RECT  3.96 40.981 5.1 42.853 ;
     RECT  6.648 41.413 7.632 42.803 ;
     RECT  8.112 42.133 9.216 42.565 ;
     RECT  9.24 42.133 10.5 45.155 ;
     RECT  8.232 42.565 9.216 45.011 ;
     RECT  6.648 42.803 7.8 44.437 ;
     RECT  4.56 44.483 5.1 45.637 ;
     RECT  8.112 45.011 9.216 45.155 ;
     RECT  8.112 47.173 9.36 53.557 ;
     RECT  9.384 47.173 10.5 61.043 ;
     RECT  5.412 49.043 6.624 51.347 ;
     RECT  5.412 55.907 7.008 57.397 ;
     RECT  3.96 56.341 5.1 57.059 ;
     RECT  8.112 56.483 9.168 57.635 ;
     RECT  5.784 57.397 7.008 58.597 ;
     RECT  8.112 57.635 9.36 60.949 ;
     RECT  3.576 60.901 5.1 62.195 ;
     RECT  5.544 62.533 7.008 62.579 ;
     RECT  7.44 62.579 7.8 63.781 ;
     RECT  8.112 65.509 9.216 66.899 ;
     RECT  9.24 65.509 10.5 66.899 ;
  END
END qwen_glue_v514
END LIBRARY
